# Generated by FakeRAM 2.0 (routing-friendly)
VERSION 5.7 ;
BUSBITCHARS "[]" ;
PROPERTYDEFINITIONS
  MACRO width INTEGER ;
  MACRO depth INTEGER ;
  MACRO banks INTEGER ;
END PROPERTYDEFINITIONS
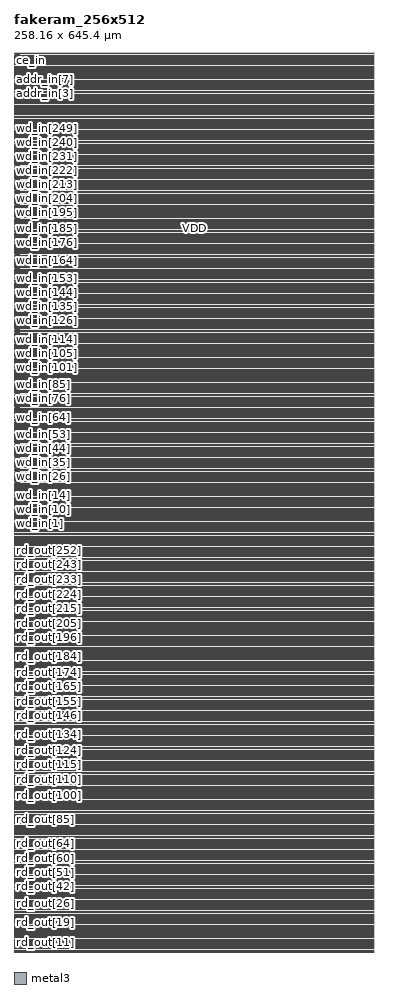
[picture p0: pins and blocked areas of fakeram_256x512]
MACRO fakeram_256x512
  PROPERTY width 256 ;
  PROPERTY depth 512 ;
  PROPERTY banks 2 ;
  FOREIGN fakeram_256x512 0 0 ;
  SYMMETRY X Y R90 ;
  SIZE 258.160 BY 645.400 ;
  CLASS BLOCK ;
  PIN rd_out[0]
    DIRECTION OUTPUT ;
    USE SIGNAL ;
    PORT
      LAYER metal3 ;
      RECT 1.000 0.140 3.000 0.210 ;
    END
    PORT
      LAYER metal3 ;
      RECT 1.000 0.105 4.000 0.245 ;
    END
  END rd_out[0]
  PIN rd_out[1]
    DIRECTION OUTPUT ;
    USE SIGNAL ;
    PORT
      LAYER metal3 ;
      RECT 1.000 1.260 3.000 1.330 ;
    END
    PORT
      LAYER metal3 ;
      RECT 1.000 1.225 4.000 1.365 ;
    END
  END rd_out[1]
  PIN rd_out[2]
    DIRECTION OUTPUT ;
    USE SIGNAL ;
    PORT
      LAYER metal3 ;
      RECT 1.000 2.380 3.000 2.450 ;
    END
    PORT
      LAYER metal3 ;
      RECT 1.000 2.345 4.000 2.485 ;
    END
  END rd_out[2]
  PIN rd_out[3]
    DIRECTION OUTPUT ;
    USE SIGNAL ;
    PORT
      LAYER metal3 ;
      RECT 1.000 3.500 3.000 3.570 ;
    END
    PORT
      LAYER metal3 ;
      RECT 1.000 3.465 4.000 3.605 ;
    END
  END rd_out[3]
  PIN rd_out[4]
    DIRECTION OUTPUT ;
    USE SIGNAL ;
    PORT
      LAYER metal3 ;
      RECT 1.000 4.620 3.000 4.690 ;
    END
    PORT
      LAYER metal3 ;
      RECT 1.000 4.585 4.000 4.725 ;
    END
  END rd_out[4]
  PIN rd_out[5]
    DIRECTION OUTPUT ;
    USE SIGNAL ;
    PORT
      LAYER metal3 ;
      RECT 1.000 5.740 3.000 5.810 ;
    END
    PORT
      LAYER metal3 ;
      RECT 1.000 5.705 4.000 5.845 ;
    END
  END rd_out[5]
  PIN rd_out[6]
    DIRECTION OUTPUT ;
    USE SIGNAL ;
    PORT
      LAYER metal3 ;
      RECT 1.000 6.860 3.000 6.930 ;
    END
    PORT
      LAYER metal3 ;
      RECT 1.000 6.825 4.000 6.965 ;
    END
  END rd_out[6]
  PIN rd_out[7]
    DIRECTION OUTPUT ;
    USE SIGNAL ;
    PORT
      LAYER metal3 ;
      RECT 1.000 7.980 3.000 8.050 ;
    END
    PORT
      LAYER metal3 ;
      RECT 1.000 7.945 4.000 8.085 ;
    END
  END rd_out[7]
  PIN rd_out[8]
    DIRECTION OUTPUT ;
    USE SIGNAL ;
    PORT
      LAYER metal3 ;
      RECT 1.000 9.100 3.000 9.170 ;
    END
    PORT
      LAYER metal3 ;
      RECT 1.000 9.065 4.000 9.205 ;
    END
  END rd_out[8]
  PIN rd_out[9]
    DIRECTION OUTPUT ;
    USE SIGNAL ;
    PORT
      LAYER metal3 ;
      RECT 1.000 10.220 3.000 10.290 ;
    END
    PORT
      LAYER metal3 ;
      RECT 1.000 10.185 4.000 10.325 ;
    END
  END rd_out[9]
  PIN rd_out[10]
    DIRECTION OUTPUT ;
    USE SIGNAL ;
    PORT
      LAYER metal3 ;
      RECT 1.000 11.340 3.000 11.410 ;
    END
    PORT
      LAYER metal3 ;
      RECT 1.000 11.305 4.000 11.445 ;
    END
  END rd_out[10]
  PIN rd_out[11]
    DIRECTION OUTPUT ;
    USE SIGNAL ;
    PORT
      LAYER metal3 ;
      RECT 1.000 12.460 3.000 12.530 ;
    END
    PORT
      LAYER metal3 ;
      RECT 1.000 12.425 4.000 12.565 ;
    END
  END rd_out[11]
  PIN rd_out[12]
    DIRECTION OUTPUT ;
    USE SIGNAL ;
    PORT
      LAYER metal3 ;
      RECT 1.000 13.580 3.000 13.650 ;
    END
    PORT
      LAYER metal3 ;
      RECT 1.000 13.545 4.000 13.685 ;
    END
  END rd_out[12]
  PIN rd_out[13]
    DIRECTION OUTPUT ;
    USE SIGNAL ;
    PORT
      LAYER metal3 ;
      RECT 1.000 14.700 3.000 14.770 ;
    END
    PORT
      LAYER metal3 ;
      RECT 1.000 14.665 4.000 14.805 ;
    END
  END rd_out[13]
  PIN rd_out[14]
    DIRECTION OUTPUT ;
    USE SIGNAL ;
    PORT
      LAYER metal3 ;
      RECT 1.000 15.820 3.000 15.890 ;
    END
    PORT
      LAYER metal3 ;
      RECT 1.000 15.785 4.000 15.925 ;
    END
  END rd_out[14]
  PIN rd_out[15]
    DIRECTION OUTPUT ;
    USE SIGNAL ;
    PORT
      LAYER metal3 ;
      RECT 1.000 16.940 3.000 17.010 ;
    END
    PORT
      LAYER metal3 ;
      RECT 1.000 16.905 4.000 17.045 ;
    END
  END rd_out[15]
  PIN rd_out[16]
    DIRECTION OUTPUT ;
    USE SIGNAL ;
    PORT
      LAYER metal3 ;
      RECT 1.000 18.060 3.000 18.130 ;
    END
    PORT
      LAYER metal3 ;
      RECT 1.000 18.025 4.000 18.165 ;
    END
  END rd_out[16]
  PIN rd_out[17]
    DIRECTION OUTPUT ;
    USE SIGNAL ;
    PORT
      LAYER metal3 ;
      RECT 1.000 19.180 3.000 19.250 ;
    END
    PORT
      LAYER metal3 ;
      RECT 1.000 19.145 4.000 19.285 ;
    END
  END rd_out[17]
  PIN rd_out[18]
    DIRECTION OUTPUT ;
    USE SIGNAL ;
    PORT
      LAYER metal3 ;
      RECT 1.000 20.300 3.000 20.370 ;
    END
    PORT
      LAYER metal3 ;
      RECT 1.000 20.265 4.000 20.405 ;
    END
  END rd_out[18]
  PIN rd_out[19]
    DIRECTION OUTPUT ;
    USE SIGNAL ;
    PORT
      LAYER metal3 ;
      RECT 1.000 21.420 3.000 21.490 ;
    END
    PORT
      LAYER metal3 ;
      RECT 1.000 21.385 4.000 21.525 ;
    END
  END rd_out[19]
  PIN rd_out[20]
    DIRECTION OUTPUT ;
    USE SIGNAL ;
    PORT
      LAYER metal3 ;
      RECT 1.000 22.540 3.000 22.610 ;
    END
    PORT
      LAYER metal3 ;
      RECT 1.000 22.505 4.000 22.645 ;
    END
  END rd_out[20]
  PIN rd_out[21]
    DIRECTION OUTPUT ;
    USE SIGNAL ;
    PORT
      LAYER metal3 ;
      RECT 1.000 23.660 3.000 23.730 ;
    END
    PORT
      LAYER metal3 ;
      RECT 1.000 23.625 4.000 23.765 ;
    END
  END rd_out[21]
  PIN rd_out[22]
    DIRECTION OUTPUT ;
    USE SIGNAL ;
    PORT
      LAYER metal3 ;
      RECT 1.000 24.780 3.000 24.850 ;
    END
    PORT
      LAYER metal3 ;
      RECT 1.000 24.745 4.000 24.885 ;
    END
  END rd_out[22]
  PIN rd_out[23]
    DIRECTION OUTPUT ;
    USE SIGNAL ;
    PORT
      LAYER metal3 ;
      RECT 1.000 25.900 3.000 25.970 ;
    END
    PORT
      LAYER metal3 ;
      RECT 1.000 25.865 4.000 26.005 ;
    END
  END rd_out[23]
  PIN rd_out[24]
    DIRECTION OUTPUT ;
    USE SIGNAL ;
    PORT
      LAYER metal3 ;
      RECT 1.000 27.020 3.000 27.090 ;
    END
    PORT
      LAYER metal3 ;
      RECT 1.000 26.985 4.000 27.125 ;
    END
  END rd_out[24]
  PIN rd_out[25]
    DIRECTION OUTPUT ;
    USE SIGNAL ;
    PORT
      LAYER metal3 ;
      RECT 1.000 28.140 3.000 28.210 ;
    END
    PORT
      LAYER metal3 ;
      RECT 1.000 28.105 4.000 28.245 ;
    END
  END rd_out[25]
  PIN rd_out[26]
    DIRECTION OUTPUT ;
    USE SIGNAL ;
    PORT
      LAYER metal3 ;
      RECT 1.000 29.260 3.000 29.330 ;
    END
    PORT
      LAYER metal3 ;
      RECT 1.000 29.225 4.000 29.365 ;
    END
  END rd_out[26]
  PIN rd_out[27]
    DIRECTION OUTPUT ;
    USE SIGNAL ;
    PORT
      LAYER metal3 ;
      RECT 1.000 30.380 3.000 30.450 ;
    END
    PORT
      LAYER metal3 ;
      RECT 1.000 30.345 4.000 30.485 ;
    END
  END rd_out[27]
  PIN rd_out[28]
    DIRECTION OUTPUT ;
    USE SIGNAL ;
    PORT
      LAYER metal3 ;
      RECT 1.000 31.500 3.000 31.570 ;
    END
    PORT
      LAYER metal3 ;
      RECT 1.000 31.465 4.000 31.605 ;
    END
  END rd_out[28]
  PIN rd_out[29]
    DIRECTION OUTPUT ;
    USE SIGNAL ;
    PORT
      LAYER metal3 ;
      RECT 1.000 32.620 3.000 32.690 ;
    END
    PORT
      LAYER metal3 ;
      RECT 1.000 32.585 4.000 32.725 ;
    END
  END rd_out[29]
  PIN rd_out[30]
    DIRECTION OUTPUT ;
    USE SIGNAL ;
    PORT
      LAYER metal3 ;
      RECT 1.000 33.740 3.000 33.810 ;
    END
    PORT
      LAYER metal3 ;
      RECT 1.000 33.705 4.000 33.845 ;
    END
  END rd_out[30]
  PIN rd_out[31]
    DIRECTION OUTPUT ;
    USE SIGNAL ;
    PORT
      LAYER metal3 ;
      RECT 1.000 34.860 3.000 34.930 ;
    END
    PORT
      LAYER metal3 ;
      RECT 1.000 34.825 4.000 34.965 ;
    END
  END rd_out[31]
  PIN rd_out[32]
    DIRECTION OUTPUT ;
    USE SIGNAL ;
    PORT
      LAYER metal3 ;
      RECT 1.000 35.980 3.000 36.050 ;
    END
    PORT
      LAYER metal3 ;
      RECT 1.000 35.945 4.000 36.085 ;
    END
  END rd_out[32]
  PIN rd_out[33]
    DIRECTION OUTPUT ;
    USE SIGNAL ;
    PORT
      LAYER metal3 ;
      RECT 1.000 37.100 3.000 37.170 ;
    END
    PORT
      LAYER metal3 ;
      RECT 1.000 37.065 4.000 37.205 ;
    END
  END rd_out[33]
  PIN rd_out[34]
    DIRECTION OUTPUT ;
    USE SIGNAL ;
    PORT
      LAYER metal3 ;
      RECT 1.000 38.220 3.000 38.290 ;
    END
    PORT
      LAYER metal3 ;
      RECT 1.000 38.185 4.000 38.325 ;
    END
  END rd_out[34]
  PIN rd_out[35]
    DIRECTION OUTPUT ;
    USE SIGNAL ;
    PORT
      LAYER metal3 ;
      RECT 1.000 39.340 3.000 39.410 ;
    END
    PORT
      LAYER metal3 ;
      RECT 1.000 39.305 4.000 39.445 ;
    END
  END rd_out[35]
  PIN rd_out[36]
    DIRECTION OUTPUT ;
    USE SIGNAL ;
    PORT
      LAYER metal3 ;
      RECT 1.000 40.460 3.000 40.530 ;
    END
    PORT
      LAYER metal3 ;
      RECT 1.000 40.425 4.000 40.565 ;
    END
  END rd_out[36]
  PIN rd_out[37]
    DIRECTION OUTPUT ;
    USE SIGNAL ;
    PORT
      LAYER metal3 ;
      RECT 1.000 41.580 3.000 41.650 ;
    END
    PORT
      LAYER metal3 ;
      RECT 1.000 41.545 4.000 41.685 ;
    END
  END rd_out[37]
  PIN rd_out[38]
    DIRECTION OUTPUT ;
    USE SIGNAL ;
    PORT
      LAYER metal3 ;
      RECT 1.000 42.700 3.000 42.770 ;
    END
    PORT
      LAYER metal3 ;
      RECT 1.000 42.665 4.000 42.805 ;
    END
  END rd_out[38]
  PIN rd_out[39]
    DIRECTION OUTPUT ;
    USE SIGNAL ;
    PORT
      LAYER metal3 ;
      RECT 1.000 43.820 3.000 43.890 ;
    END
    PORT
      LAYER metal3 ;
      RECT 1.000 43.785 4.000 43.925 ;
    END
  END rd_out[39]
  PIN rd_out[40]
    DIRECTION OUTPUT ;
    USE SIGNAL ;
    PORT
      LAYER metal3 ;
      RECT 1.000 44.940 3.000 45.010 ;
    END
    PORT
      LAYER metal3 ;
      RECT 1.000 44.905 4.000 45.045 ;
    END
  END rd_out[40]
  PIN rd_out[41]
    DIRECTION OUTPUT ;
    USE SIGNAL ;
    PORT
      LAYER metal3 ;
      RECT 1.000 46.060 3.000 46.130 ;
    END
    PORT
      LAYER metal3 ;
      RECT 1.000 46.025 4.000 46.165 ;
    END
  END rd_out[41]
  PIN rd_out[42]
    DIRECTION OUTPUT ;
    USE SIGNAL ;
    PORT
      LAYER metal3 ;
      RECT 1.000 47.180 3.000 47.250 ;
    END
    PORT
      LAYER metal3 ;
      RECT 1.000 47.145 4.000 47.285 ;
    END
  END rd_out[42]
  PIN rd_out[43]
    DIRECTION OUTPUT ;
    USE SIGNAL ;
    PORT
      LAYER metal3 ;
      RECT 1.000 48.300 3.000 48.370 ;
    END
    PORT
      LAYER metal3 ;
      RECT 1.000 48.265 4.000 48.405 ;
    END
  END rd_out[43]
  PIN rd_out[44]
    DIRECTION OUTPUT ;
    USE SIGNAL ;
    PORT
      LAYER metal3 ;
      RECT 1.000 49.420 3.000 49.490 ;
    END
    PORT
      LAYER metal3 ;
      RECT 1.000 49.385 4.000 49.525 ;
    END
  END rd_out[44]
  PIN rd_out[45]
    DIRECTION OUTPUT ;
    USE SIGNAL ;
    PORT
      LAYER metal3 ;
      RECT 1.000 50.540 3.000 50.610 ;
    END
    PORT
      LAYER metal3 ;
      RECT 1.000 50.505 4.000 50.645 ;
    END
  END rd_out[45]
  PIN rd_out[46]
    DIRECTION OUTPUT ;
    USE SIGNAL ;
    PORT
      LAYER metal3 ;
      RECT 1.000 51.660 3.000 51.730 ;
    END
    PORT
      LAYER metal3 ;
      RECT 1.000 51.625 4.000 51.765 ;
    END
  END rd_out[46]
  PIN rd_out[47]
    DIRECTION OUTPUT ;
    USE SIGNAL ;
    PORT
      LAYER metal3 ;
      RECT 1.000 52.780 3.000 52.850 ;
    END
    PORT
      LAYER metal3 ;
      RECT 1.000 52.745 4.000 52.885 ;
    END
  END rd_out[47]
  PIN rd_out[48]
    DIRECTION OUTPUT ;
    USE SIGNAL ;
    PORT
      LAYER metal3 ;
      RECT 1.000 53.900 3.000 53.970 ;
    END
    PORT
      LAYER metal3 ;
      RECT 1.000 53.865 4.000 54.005 ;
    END
  END rd_out[48]
  PIN rd_out[49]
    DIRECTION OUTPUT ;
    USE SIGNAL ;
    PORT
      LAYER metal3 ;
      RECT 1.000 55.020 3.000 55.090 ;
    END
    PORT
      LAYER metal3 ;
      RECT 1.000 54.985 4.000 55.125 ;
    END
  END rd_out[49]
  PIN rd_out[50]
    DIRECTION OUTPUT ;
    USE SIGNAL ;
    PORT
      LAYER metal3 ;
      RECT 1.000 56.140 3.000 56.210 ;
    END
    PORT
      LAYER metal3 ;
      RECT 1.000 56.105 4.000 56.245 ;
    END
  END rd_out[50]
  PIN rd_out[51]
    DIRECTION OUTPUT ;
    USE SIGNAL ;
    PORT
      LAYER metal3 ;
      RECT 1.000 57.260 3.000 57.330 ;
    END
    PORT
      LAYER metal3 ;
      RECT 1.000 57.225 4.000 57.365 ;
    END
  END rd_out[51]
  PIN rd_out[52]
    DIRECTION OUTPUT ;
    USE SIGNAL ;
    PORT
      LAYER metal3 ;
      RECT 1.000 58.380 3.000 58.450 ;
    END
    PORT
      LAYER metal3 ;
      RECT 1.000 58.345 4.000 58.485 ;
    END
  END rd_out[52]
  PIN rd_out[53]
    DIRECTION OUTPUT ;
    USE SIGNAL ;
    PORT
      LAYER metal3 ;
      RECT 1.000 59.500 3.000 59.570 ;
    END
    PORT
      LAYER metal3 ;
      RECT 1.000 59.465 4.000 59.605 ;
    END
  END rd_out[53]
  PIN rd_out[54]
    DIRECTION OUTPUT ;
    USE SIGNAL ;
    PORT
      LAYER metal3 ;
      RECT 1.000 60.620 3.000 60.690 ;
    END
    PORT
      LAYER metal3 ;
      RECT 1.000 60.585 4.000 60.725 ;
    END
  END rd_out[54]
  PIN rd_out[55]
    DIRECTION OUTPUT ;
    USE SIGNAL ;
    PORT
      LAYER metal3 ;
      RECT 1.000 61.740 3.000 61.810 ;
    END
    PORT
      LAYER metal3 ;
      RECT 1.000 61.705 4.000 61.845 ;
    END
  END rd_out[55]
  PIN rd_out[56]
    DIRECTION OUTPUT ;
    USE SIGNAL ;
    PORT
      LAYER metal3 ;
      RECT 1.000 62.860 3.000 62.930 ;
    END
    PORT
      LAYER metal3 ;
      RECT 1.000 62.825 4.000 62.965 ;
    END
  END rd_out[56]
  PIN rd_out[57]
    DIRECTION OUTPUT ;
    USE SIGNAL ;
    PORT
      LAYER metal3 ;
      RECT 1.000 63.980 3.000 64.050 ;
    END
    PORT
      LAYER metal3 ;
      RECT 1.000 63.945 4.000 64.085 ;
    END
  END rd_out[57]
  PIN rd_out[58]
    DIRECTION OUTPUT ;
    USE SIGNAL ;
    PORT
      LAYER metal3 ;
      RECT 1.000 65.100 3.000 65.170 ;
    END
    PORT
      LAYER metal3 ;
      RECT 1.000 65.065 4.000 65.205 ;
    END
  END rd_out[58]
  PIN rd_out[59]
    DIRECTION OUTPUT ;
    USE SIGNAL ;
    PORT
      LAYER metal3 ;
      RECT 1.000 66.220 3.000 66.290 ;
    END
    PORT
      LAYER metal3 ;
      RECT 1.000 66.185 4.000 66.325 ;
    END
  END rd_out[59]
  PIN rd_out[60]
    DIRECTION OUTPUT ;
    USE SIGNAL ;
    PORT
      LAYER metal3 ;
      RECT 1.000 67.340 3.000 67.410 ;
    END
    PORT
      LAYER metal3 ;
      RECT 1.000 67.305 4.000 67.445 ;
    END
  END rd_out[60]
  PIN rd_out[61]
    DIRECTION OUTPUT ;
    USE SIGNAL ;
    PORT
      LAYER metal3 ;
      RECT 1.000 68.460 3.000 68.530 ;
    END
    PORT
      LAYER metal3 ;
      RECT 1.000 68.425 4.000 68.565 ;
    END
  END rd_out[61]
  PIN rd_out[62]
    DIRECTION OUTPUT ;
    USE SIGNAL ;
    PORT
      LAYER metal3 ;
      RECT 1.000 69.580 3.000 69.650 ;
    END
    PORT
      LAYER metal3 ;
      RECT 1.000 69.545 4.000 69.685 ;
    END
  END rd_out[62]
  PIN rd_out[63]
    DIRECTION OUTPUT ;
    USE SIGNAL ;
    PORT
      LAYER metal3 ;
      RECT 1.000 70.700 3.000 70.770 ;
    END
    PORT
      LAYER metal3 ;
      RECT 1.000 70.665 4.000 70.805 ;
    END
  END rd_out[63]
  PIN rd_out[64]
    DIRECTION OUTPUT ;
    USE SIGNAL ;
    PORT
      LAYER metal3 ;
      RECT 1.000 71.820 3.000 71.890 ;
    END
    PORT
      LAYER metal3 ;
      RECT 1.000 71.785 4.000 71.925 ;
    END
  END rd_out[64]
  PIN rd_out[65]
    DIRECTION OUTPUT ;
    USE SIGNAL ;
    PORT
      LAYER metal3 ;
      RECT 1.000 72.940 3.000 73.010 ;
    END
    PORT
      LAYER metal3 ;
      RECT 1.000 72.905 4.000 73.045 ;
    END
  END rd_out[65]
  PIN rd_out[66]
    DIRECTION OUTPUT ;
    USE SIGNAL ;
    PORT
      LAYER metal3 ;
      RECT 1.000 74.060 3.000 74.130 ;
    END
    PORT
      LAYER metal3 ;
      RECT 1.000 74.025 4.000 74.165 ;
    END
  END rd_out[66]
  PIN rd_out[67]
    DIRECTION OUTPUT ;
    USE SIGNAL ;
    PORT
      LAYER metal3 ;
      RECT 1.000 75.180 3.000 75.250 ;
    END
    PORT
      LAYER metal3 ;
      RECT 1.000 75.145 4.000 75.285 ;
    END
  END rd_out[67]
  PIN rd_out[68]
    DIRECTION OUTPUT ;
    USE SIGNAL ;
    PORT
      LAYER metal3 ;
      RECT 1.000 76.300 3.000 76.370 ;
    END
    PORT
      LAYER metal3 ;
      RECT 1.000 76.265 4.000 76.405 ;
    END
  END rd_out[68]
  PIN rd_out[69]
    DIRECTION OUTPUT ;
    USE SIGNAL ;
    PORT
      LAYER metal3 ;
      RECT 1.000 77.420 3.000 77.490 ;
    END
    PORT
      LAYER metal3 ;
      RECT 1.000 77.385 4.000 77.525 ;
    END
  END rd_out[69]
  PIN rd_out[70]
    DIRECTION OUTPUT ;
    USE SIGNAL ;
    PORT
      LAYER metal3 ;
      RECT 1.000 78.540 3.000 78.610 ;
    END
    PORT
      LAYER metal3 ;
      RECT 1.000 78.505 4.000 78.645 ;
    END
  END rd_out[70]
  PIN rd_out[71]
    DIRECTION OUTPUT ;
    USE SIGNAL ;
    PORT
      LAYER metal3 ;
      RECT 1.000 79.660 3.000 79.730 ;
    END
    PORT
      LAYER metal3 ;
      RECT 1.000 79.625 4.000 79.765 ;
    END
  END rd_out[71]
  PIN rd_out[72]
    DIRECTION OUTPUT ;
    USE SIGNAL ;
    PORT
      LAYER metal3 ;
      RECT 1.000 80.780 3.000 80.850 ;
    END
    PORT
      LAYER metal3 ;
      RECT 1.000 80.745 4.000 80.885 ;
    END
  END rd_out[72]
  PIN rd_out[73]
    DIRECTION OUTPUT ;
    USE SIGNAL ;
    PORT
      LAYER metal3 ;
      RECT 1.000 81.900 3.000 81.970 ;
    END
    PORT
      LAYER metal3 ;
      RECT 1.000 81.865 4.000 82.005 ;
    END
  END rd_out[73]
  PIN rd_out[74]
    DIRECTION OUTPUT ;
    USE SIGNAL ;
    PORT
      LAYER metal3 ;
      RECT 1.000 83.020 3.000 83.090 ;
    END
    PORT
      LAYER metal3 ;
      RECT 1.000 82.985 4.000 83.125 ;
    END
  END rd_out[74]
  PIN rd_out[75]
    DIRECTION OUTPUT ;
    USE SIGNAL ;
    PORT
      LAYER metal3 ;
      RECT 1.000 84.140 3.000 84.210 ;
    END
    PORT
      LAYER metal3 ;
      RECT 1.000 84.105 4.000 84.245 ;
    END
  END rd_out[75]
  PIN rd_out[76]
    DIRECTION OUTPUT ;
    USE SIGNAL ;
    PORT
      LAYER metal3 ;
      RECT 1.000 85.260 3.000 85.330 ;
    END
    PORT
      LAYER metal3 ;
      RECT 1.000 85.225 4.000 85.365 ;
    END
  END rd_out[76]
  PIN rd_out[77]
    DIRECTION OUTPUT ;
    USE SIGNAL ;
    PORT
      LAYER metal3 ;
      RECT 1.000 86.380 3.000 86.450 ;
    END
    PORT
      LAYER metal3 ;
      RECT 1.000 86.345 4.000 86.485 ;
    END
  END rd_out[77]
  PIN rd_out[78]
    DIRECTION OUTPUT ;
    USE SIGNAL ;
    PORT
      LAYER metal3 ;
      RECT 1.000 87.500 3.000 87.570 ;
    END
    PORT
      LAYER metal3 ;
      RECT 1.000 87.465 4.000 87.605 ;
    END
  END rd_out[78]
  PIN rd_out[79]
    DIRECTION OUTPUT ;
    USE SIGNAL ;
    PORT
      LAYER metal3 ;
      RECT 1.000 88.620 3.000 88.690 ;
    END
    PORT
      LAYER metal3 ;
      RECT 1.000 88.585 4.000 88.725 ;
    END
  END rd_out[79]
  PIN rd_out[80]
    DIRECTION OUTPUT ;
    USE SIGNAL ;
    PORT
      LAYER metal3 ;
      RECT 1.000 89.740 3.000 89.810 ;
    END
    PORT
      LAYER metal3 ;
      RECT 1.000 89.705 4.000 89.845 ;
    END
  END rd_out[80]
  PIN rd_out[81]
    DIRECTION OUTPUT ;
    USE SIGNAL ;
    PORT
      LAYER metal3 ;
      RECT 1.000 90.860 3.000 90.930 ;
    END
    PORT
      LAYER metal3 ;
      RECT 1.000 90.825 4.000 90.965 ;
    END
  END rd_out[81]
  PIN rd_out[82]
    DIRECTION OUTPUT ;
    USE SIGNAL ;
    PORT
      LAYER metal3 ;
      RECT 1.000 91.980 3.000 92.050 ;
    END
    PORT
      LAYER metal3 ;
      RECT 1.000 91.945 4.000 92.085 ;
    END
  END rd_out[82]
  PIN rd_out[83]
    DIRECTION OUTPUT ;
    USE SIGNAL ;
    PORT
      LAYER metal3 ;
      RECT 1.000 93.100 3.000 93.170 ;
    END
    PORT
      LAYER metal3 ;
      RECT 1.000 93.065 4.000 93.205 ;
    END
  END rd_out[83]
  PIN rd_out[84]
    DIRECTION OUTPUT ;
    USE SIGNAL ;
    PORT
      LAYER metal3 ;
      RECT 1.000 94.220 3.000 94.290 ;
    END
    PORT
      LAYER metal3 ;
      RECT 1.000 94.185 4.000 94.325 ;
    END
  END rd_out[84]
  PIN rd_out[85]
    DIRECTION OUTPUT ;
    USE SIGNAL ;
    PORT
      LAYER metal3 ;
      RECT 1.000 95.340 3.000 95.410 ;
    END
    PORT
      LAYER metal3 ;
      RECT 1.000 95.305 4.000 95.445 ;
    END
  END rd_out[85]
  PIN rd_out[86]
    DIRECTION OUTPUT ;
    USE SIGNAL ;
    PORT
      LAYER metal3 ;
      RECT 1.000 96.460 3.000 96.530 ;
    END
    PORT
      LAYER metal3 ;
      RECT 1.000 96.425 4.000 96.565 ;
    END
  END rd_out[86]
  PIN rd_out[87]
    DIRECTION OUTPUT ;
    USE SIGNAL ;
    PORT
      LAYER metal3 ;
      RECT 1.000 97.580 3.000 97.650 ;
    END
    PORT
      LAYER metal3 ;
      RECT 1.000 97.545 4.000 97.685 ;
    END
  END rd_out[87]
  PIN rd_out[88]
    DIRECTION OUTPUT ;
    USE SIGNAL ;
    PORT
      LAYER metal3 ;
      RECT 1.000 98.700 3.000 98.770 ;
    END
    PORT
      LAYER metal3 ;
      RECT 1.000 98.665 4.000 98.805 ;
    END
  END rd_out[88]
  PIN rd_out[89]
    DIRECTION OUTPUT ;
    USE SIGNAL ;
    PORT
      LAYER metal3 ;
      RECT 1.000 99.820 3.000 99.890 ;
    END
    PORT
      LAYER metal3 ;
      RECT 1.000 99.785 4.000 99.925 ;
    END
  END rd_out[89]
  PIN rd_out[90]
    DIRECTION OUTPUT ;
    USE SIGNAL ;
    PORT
      LAYER metal3 ;
      RECT 1.000 100.940 3.000 101.010 ;
    END
    PORT
      LAYER metal3 ;
      RECT 1.000 100.905 4.000 101.045 ;
    END
  END rd_out[90]
  PIN rd_out[91]
    DIRECTION OUTPUT ;
    USE SIGNAL ;
    PORT
      LAYER metal3 ;
      RECT 1.000 102.060 3.000 102.130 ;
    END
    PORT
      LAYER metal3 ;
      RECT 1.000 102.025 4.000 102.165 ;
    END
  END rd_out[91]
  PIN rd_out[92]
    DIRECTION OUTPUT ;
    USE SIGNAL ;
    PORT
      LAYER metal3 ;
      RECT 1.000 103.180 3.000 103.250 ;
    END
    PORT
      LAYER metal3 ;
      RECT 1.000 103.145 4.000 103.285 ;
    END
  END rd_out[92]
  PIN rd_out[93]
    DIRECTION OUTPUT ;
    USE SIGNAL ;
    PORT
      LAYER metal3 ;
      RECT 1.000 104.300 3.000 104.370 ;
    END
    PORT
      LAYER metal3 ;
      RECT 1.000 104.265 4.000 104.405 ;
    END
  END rd_out[93]
  PIN rd_out[94]
    DIRECTION OUTPUT ;
    USE SIGNAL ;
    PORT
      LAYER metal3 ;
      RECT 1.000 105.420 3.000 105.490 ;
    END
    PORT
      LAYER metal3 ;
      RECT 1.000 105.385 4.000 105.525 ;
    END
  END rd_out[94]
  PIN rd_out[95]
    DIRECTION OUTPUT ;
    USE SIGNAL ;
    PORT
      LAYER metal3 ;
      RECT 1.000 106.540 3.000 106.610 ;
    END
    PORT
      LAYER metal3 ;
      RECT 1.000 106.505 4.000 106.645 ;
    END
  END rd_out[95]
  PIN rd_out[96]
    DIRECTION OUTPUT ;
    USE SIGNAL ;
    PORT
      LAYER metal3 ;
      RECT 1.000 107.660 3.000 107.730 ;
    END
    PORT
      LAYER metal3 ;
      RECT 1.000 107.625 4.000 107.765 ;
    END
  END rd_out[96]
  PIN rd_out[97]
    DIRECTION OUTPUT ;
    USE SIGNAL ;
    PORT
      LAYER metal3 ;
      RECT 1.000 108.780 3.000 108.850 ;
    END
    PORT
      LAYER metal3 ;
      RECT 1.000 108.745 4.000 108.885 ;
    END
  END rd_out[97]
  PIN rd_out[98]
    DIRECTION OUTPUT ;
    USE SIGNAL ;
    PORT
      LAYER metal3 ;
      RECT 1.000 109.900 3.000 109.970 ;
    END
    PORT
      LAYER metal3 ;
      RECT 1.000 109.865 4.000 110.005 ;
    END
  END rd_out[98]
  PIN rd_out[99]
    DIRECTION OUTPUT ;
    USE SIGNAL ;
    PORT
      LAYER metal3 ;
      RECT 1.000 111.020 3.000 111.090 ;
    END
    PORT
      LAYER metal3 ;
      RECT 1.000 110.985 4.000 111.125 ;
    END
  END rd_out[99]
  PIN rd_out[100]
    DIRECTION OUTPUT ;
    USE SIGNAL ;
    PORT
      LAYER metal3 ;
      RECT 1.000 112.140 3.000 112.210 ;
    END
    PORT
      LAYER metal3 ;
      RECT 1.000 112.105 4.000 112.245 ;
    END
  END rd_out[100]
  PIN rd_out[101]
    DIRECTION OUTPUT ;
    USE SIGNAL ;
    PORT
      LAYER metal3 ;
      RECT 1.000 113.260 3.000 113.330 ;
    END
    PORT
      LAYER metal3 ;
      RECT 1.000 113.225 4.000 113.365 ;
    END
  END rd_out[101]
  PIN rd_out[102]
    DIRECTION OUTPUT ;
    USE SIGNAL ;
    PORT
      LAYER metal3 ;
      RECT 1.000 114.380 3.000 114.450 ;
    END
    PORT
      LAYER metal3 ;
      RECT 1.000 114.345 4.000 114.485 ;
    END
  END rd_out[102]
  PIN rd_out[103]
    DIRECTION OUTPUT ;
    USE SIGNAL ;
    PORT
      LAYER metal3 ;
      RECT 1.000 115.500 3.000 115.570 ;
    END
    PORT
      LAYER metal3 ;
      RECT 1.000 115.465 4.000 115.605 ;
    END
  END rd_out[103]
  PIN rd_out[104]
    DIRECTION OUTPUT ;
    USE SIGNAL ;
    PORT
      LAYER metal3 ;
      RECT 1.000 116.620 3.000 116.690 ;
    END
    PORT
      LAYER metal3 ;
      RECT 1.000 116.585 4.000 116.725 ;
    END
  END rd_out[104]
  PIN rd_out[105]
    DIRECTION OUTPUT ;
    USE SIGNAL ;
    PORT
      LAYER metal3 ;
      RECT 1.000 117.740 3.000 117.810 ;
    END
    PORT
      LAYER metal3 ;
      RECT 1.000 117.705 4.000 117.845 ;
    END
  END rd_out[105]
  PIN rd_out[106]
    DIRECTION OUTPUT ;
    USE SIGNAL ;
    PORT
      LAYER metal3 ;
      RECT 1.000 118.860 3.000 118.930 ;
    END
    PORT
      LAYER metal3 ;
      RECT 1.000 118.825 4.000 118.965 ;
    END
  END rd_out[106]
  PIN rd_out[107]
    DIRECTION OUTPUT ;
    USE SIGNAL ;
    PORT
      LAYER metal3 ;
      RECT 1.000 119.980 3.000 120.050 ;
    END
    PORT
      LAYER metal3 ;
      RECT 1.000 119.945 4.000 120.085 ;
    END
  END rd_out[107]
  PIN rd_out[108]
    DIRECTION OUTPUT ;
    USE SIGNAL ;
    PORT
      LAYER metal3 ;
      RECT 1.000 121.100 3.000 121.170 ;
    END
    PORT
      LAYER metal3 ;
      RECT 1.000 121.065 4.000 121.205 ;
    END
  END rd_out[108]
  PIN rd_out[109]
    DIRECTION OUTPUT ;
    USE SIGNAL ;
    PORT
      LAYER metal3 ;
      RECT 1.000 122.220 3.000 122.290 ;
    END
    PORT
      LAYER metal3 ;
      RECT 1.000 122.185 4.000 122.325 ;
    END
  END rd_out[109]
  PIN rd_out[110]
    DIRECTION OUTPUT ;
    USE SIGNAL ;
    PORT
      LAYER metal3 ;
      RECT 1.000 123.340 3.000 123.410 ;
    END
    PORT
      LAYER metal3 ;
      RECT 1.000 123.305 4.000 123.445 ;
    END
  END rd_out[110]
  PIN rd_out[111]
    DIRECTION OUTPUT ;
    USE SIGNAL ;
    PORT
      LAYER metal3 ;
      RECT 1.000 124.460 3.000 124.530 ;
    END
    PORT
      LAYER metal3 ;
      RECT 1.000 124.425 4.000 124.565 ;
    END
  END rd_out[111]
  PIN rd_out[112]
    DIRECTION OUTPUT ;
    USE SIGNAL ;
    PORT
      LAYER metal3 ;
      RECT 1.000 125.580 3.000 125.650 ;
    END
    PORT
      LAYER metal3 ;
      RECT 1.000 125.545 4.000 125.685 ;
    END
  END rd_out[112]
  PIN rd_out[113]
    DIRECTION OUTPUT ;
    USE SIGNAL ;
    PORT
      LAYER metal3 ;
      RECT 1.000 126.700 3.000 126.770 ;
    END
    PORT
      LAYER metal3 ;
      RECT 1.000 126.665 4.000 126.805 ;
    END
  END rd_out[113]
  PIN rd_out[114]
    DIRECTION OUTPUT ;
    USE SIGNAL ;
    PORT
      LAYER metal3 ;
      RECT 1.000 127.820 3.000 127.890 ;
    END
    PORT
      LAYER metal3 ;
      RECT 1.000 127.785 4.000 127.925 ;
    END
  END rd_out[114]
  PIN rd_out[115]
    DIRECTION OUTPUT ;
    USE SIGNAL ;
    PORT
      LAYER metal3 ;
      RECT 1.000 128.940 3.000 129.010 ;
    END
    PORT
      LAYER metal3 ;
      RECT 1.000 128.905 4.000 129.045 ;
    END
  END rd_out[115]
  PIN rd_out[116]
    DIRECTION OUTPUT ;
    USE SIGNAL ;
    PORT
      LAYER metal3 ;
      RECT 1.000 130.060 3.000 130.130 ;
    END
    PORT
      LAYER metal3 ;
      RECT 1.000 130.025 4.000 130.165 ;
    END
  END rd_out[116]
  PIN rd_out[117]
    DIRECTION OUTPUT ;
    USE SIGNAL ;
    PORT
      LAYER metal3 ;
      RECT 1.000 131.180 3.000 131.250 ;
    END
    PORT
      LAYER metal3 ;
      RECT 1.000 131.145 4.000 131.285 ;
    END
  END rd_out[117]
  PIN rd_out[118]
    DIRECTION OUTPUT ;
    USE SIGNAL ;
    PORT
      LAYER metal3 ;
      RECT 1.000 132.300 3.000 132.370 ;
    END
    PORT
      LAYER metal3 ;
      RECT 1.000 132.265 4.000 132.405 ;
    END
  END rd_out[118]
  PIN rd_out[119]
    DIRECTION OUTPUT ;
    USE SIGNAL ;
    PORT
      LAYER metal3 ;
      RECT 1.000 133.420 3.000 133.490 ;
    END
    PORT
      LAYER metal3 ;
      RECT 1.000 133.385 4.000 133.525 ;
    END
  END rd_out[119]
  PIN rd_out[120]
    DIRECTION OUTPUT ;
    USE SIGNAL ;
    PORT
      LAYER metal3 ;
      RECT 1.000 134.540 3.000 134.610 ;
    END
    PORT
      LAYER metal3 ;
      RECT 1.000 134.505 4.000 134.645 ;
    END
  END rd_out[120]
  PIN rd_out[121]
    DIRECTION OUTPUT ;
    USE SIGNAL ;
    PORT
      LAYER metal3 ;
      RECT 1.000 135.660 3.000 135.730 ;
    END
    PORT
      LAYER metal3 ;
      RECT 1.000 135.625 4.000 135.765 ;
    END
  END rd_out[121]
  PIN rd_out[122]
    DIRECTION OUTPUT ;
    USE SIGNAL ;
    PORT
      LAYER metal3 ;
      RECT 1.000 136.780 3.000 136.850 ;
    END
    PORT
      LAYER metal3 ;
      RECT 1.000 136.745 4.000 136.885 ;
    END
  END rd_out[122]
  PIN rd_out[123]
    DIRECTION OUTPUT ;
    USE SIGNAL ;
    PORT
      LAYER metal3 ;
      RECT 1.000 137.900 3.000 137.970 ;
    END
    PORT
      LAYER metal3 ;
      RECT 1.000 137.865 4.000 138.005 ;
    END
  END rd_out[123]
  PIN rd_out[124]
    DIRECTION OUTPUT ;
    USE SIGNAL ;
    PORT
      LAYER metal3 ;
      RECT 1.000 139.020 3.000 139.090 ;
    END
    PORT
      LAYER metal3 ;
      RECT 1.000 138.985 4.000 139.125 ;
    END
  END rd_out[124]
  PIN rd_out[125]
    DIRECTION OUTPUT ;
    USE SIGNAL ;
    PORT
      LAYER metal3 ;
      RECT 1.000 140.140 3.000 140.210 ;
    END
    PORT
      LAYER metal3 ;
      RECT 1.000 140.105 4.000 140.245 ;
    END
  END rd_out[125]
  PIN rd_out[126]
    DIRECTION OUTPUT ;
    USE SIGNAL ;
    PORT
      LAYER metal3 ;
      RECT 1.000 141.260 3.000 141.330 ;
    END
    PORT
      LAYER metal3 ;
      RECT 1.000 141.225 4.000 141.365 ;
    END
  END rd_out[126]
  PIN rd_out[127]
    DIRECTION OUTPUT ;
    USE SIGNAL ;
    PORT
      LAYER metal3 ;
      RECT 1.000 142.380 3.000 142.450 ;
    END
    PORT
      LAYER metal3 ;
      RECT 1.000 142.345 4.000 142.485 ;
    END
  END rd_out[127]
  PIN rd_out[128]
    DIRECTION OUTPUT ;
    USE SIGNAL ;
    PORT
      LAYER metal3 ;
      RECT 1.000 143.500 3.000 143.570 ;
    END
    PORT
      LAYER metal3 ;
      RECT 1.000 143.465 4.000 143.605 ;
    END
  END rd_out[128]
  PIN rd_out[129]
    DIRECTION OUTPUT ;
    USE SIGNAL ;
    PORT
      LAYER metal3 ;
      RECT 1.000 144.620 3.000 144.690 ;
    END
    PORT
      LAYER metal3 ;
      RECT 1.000 144.585 4.000 144.725 ;
    END
  END rd_out[129]
  PIN rd_out[130]
    DIRECTION OUTPUT ;
    USE SIGNAL ;
    PORT
      LAYER metal3 ;
      RECT 1.000 145.740 3.000 145.810 ;
    END
    PORT
      LAYER metal3 ;
      RECT 1.000 145.705 4.000 145.845 ;
    END
  END rd_out[130]
  PIN rd_out[131]
    DIRECTION OUTPUT ;
    USE SIGNAL ;
    PORT
      LAYER metal3 ;
      RECT 1.000 146.860 3.000 146.930 ;
    END
    PORT
      LAYER metal3 ;
      RECT 1.000 146.825 4.000 146.965 ;
    END
  END rd_out[131]
  PIN rd_out[132]
    DIRECTION OUTPUT ;
    USE SIGNAL ;
    PORT
      LAYER metal3 ;
      RECT 1.000 147.980 3.000 148.050 ;
    END
    PORT
      LAYER metal3 ;
      RECT 1.000 147.945 4.000 148.085 ;
    END
  END rd_out[132]
  PIN rd_out[133]
    DIRECTION OUTPUT ;
    USE SIGNAL ;
    PORT
      LAYER metal3 ;
      RECT 1.000 149.100 3.000 149.170 ;
    END
    PORT
      LAYER metal3 ;
      RECT 1.000 149.065 4.000 149.205 ;
    END
  END rd_out[133]
  PIN rd_out[134]
    DIRECTION OUTPUT ;
    USE SIGNAL ;
    PORT
      LAYER metal3 ;
      RECT 1.000 150.220 3.000 150.290 ;
    END
    PORT
      LAYER metal3 ;
      RECT 1.000 150.185 4.000 150.325 ;
    END
  END rd_out[134]
  PIN rd_out[135]
    DIRECTION OUTPUT ;
    USE SIGNAL ;
    PORT
      LAYER metal3 ;
      RECT 1.000 151.340 3.000 151.410 ;
    END
    PORT
      LAYER metal3 ;
      RECT 1.000 151.305 4.000 151.445 ;
    END
  END rd_out[135]
  PIN rd_out[136]
    DIRECTION OUTPUT ;
    USE SIGNAL ;
    PORT
      LAYER metal3 ;
      RECT 1.000 152.460 3.000 152.530 ;
    END
    PORT
      LAYER metal3 ;
      RECT 1.000 152.425 4.000 152.565 ;
    END
  END rd_out[136]
  PIN rd_out[137]
    DIRECTION OUTPUT ;
    USE SIGNAL ;
    PORT
      LAYER metal3 ;
      RECT 1.000 153.580 3.000 153.650 ;
    END
    PORT
      LAYER metal3 ;
      RECT 1.000 153.545 4.000 153.685 ;
    END
  END rd_out[137]
  PIN rd_out[138]
    DIRECTION OUTPUT ;
    USE SIGNAL ;
    PORT
      LAYER metal3 ;
      RECT 1.000 154.700 3.000 154.770 ;
    END
    PORT
      LAYER metal3 ;
      RECT 1.000 154.665 4.000 154.805 ;
    END
  END rd_out[138]
  PIN rd_out[139]
    DIRECTION OUTPUT ;
    USE SIGNAL ;
    PORT
      LAYER metal3 ;
      RECT 1.000 155.820 3.000 155.890 ;
    END
    PORT
      LAYER metal3 ;
      RECT 1.000 155.785 4.000 155.925 ;
    END
  END rd_out[139]
  PIN rd_out[140]
    DIRECTION OUTPUT ;
    USE SIGNAL ;
    PORT
      LAYER metal3 ;
      RECT 1.000 156.940 3.000 157.010 ;
    END
    PORT
      LAYER metal3 ;
      RECT 1.000 156.905 4.000 157.045 ;
    END
  END rd_out[140]
  PIN rd_out[141]
    DIRECTION OUTPUT ;
    USE SIGNAL ;
    PORT
      LAYER metal3 ;
      RECT 1.000 158.060 3.000 158.130 ;
    END
    PORT
      LAYER metal3 ;
      RECT 1.000 158.025 4.000 158.165 ;
    END
  END rd_out[141]
  PIN rd_out[142]
    DIRECTION OUTPUT ;
    USE SIGNAL ;
    PORT
      LAYER metal3 ;
      RECT 1.000 159.180 3.000 159.250 ;
    END
    PORT
      LAYER metal3 ;
      RECT 1.000 159.145 4.000 159.285 ;
    END
  END rd_out[142]
  PIN rd_out[143]
    DIRECTION OUTPUT ;
    USE SIGNAL ;
    PORT
      LAYER metal3 ;
      RECT 1.000 160.300 3.000 160.370 ;
    END
    PORT
      LAYER metal3 ;
      RECT 1.000 160.265 4.000 160.405 ;
    END
  END rd_out[143]
  PIN rd_out[144]
    DIRECTION OUTPUT ;
    USE SIGNAL ;
    PORT
      LAYER metal3 ;
      RECT 1.000 161.420 3.000 161.490 ;
    END
    PORT
      LAYER metal3 ;
      RECT 1.000 161.385 4.000 161.525 ;
    END
  END rd_out[144]
  PIN rd_out[145]
    DIRECTION OUTPUT ;
    USE SIGNAL ;
    PORT
      LAYER metal3 ;
      RECT 1.000 162.540 3.000 162.610 ;
    END
    PORT
      LAYER metal3 ;
      RECT 1.000 162.505 4.000 162.645 ;
    END
  END rd_out[145]
  PIN rd_out[146]
    DIRECTION OUTPUT ;
    USE SIGNAL ;
    PORT
      LAYER metal3 ;
      RECT 1.000 163.660 3.000 163.730 ;
    END
    PORT
      LAYER metal3 ;
      RECT 1.000 163.625 4.000 163.765 ;
    END
  END rd_out[146]
  PIN rd_out[147]
    DIRECTION OUTPUT ;
    USE SIGNAL ;
    PORT
      LAYER metal3 ;
      RECT 1.000 164.780 3.000 164.850 ;
    END
    PORT
      LAYER metal3 ;
      RECT 1.000 164.745 4.000 164.885 ;
    END
  END rd_out[147]
  PIN rd_out[148]
    DIRECTION OUTPUT ;
    USE SIGNAL ;
    PORT
      LAYER metal3 ;
      RECT 1.000 165.900 3.000 165.970 ;
    END
    PORT
      LAYER metal3 ;
      RECT 1.000 165.865 4.000 166.005 ;
    END
  END rd_out[148]
  PIN rd_out[149]
    DIRECTION OUTPUT ;
    USE SIGNAL ;
    PORT
      LAYER metal3 ;
      RECT 1.000 167.020 3.000 167.090 ;
    END
    PORT
      LAYER metal3 ;
      RECT 1.000 166.985 4.000 167.125 ;
    END
  END rd_out[149]
  PIN rd_out[150]
    DIRECTION OUTPUT ;
    USE SIGNAL ;
    PORT
      LAYER metal3 ;
      RECT 1.000 168.140 3.000 168.210 ;
    END
    PORT
      LAYER metal3 ;
      RECT 1.000 168.105 4.000 168.245 ;
    END
  END rd_out[150]
  PIN rd_out[151]
    DIRECTION OUTPUT ;
    USE SIGNAL ;
    PORT
      LAYER metal3 ;
      RECT 1.000 169.260 3.000 169.330 ;
    END
    PORT
      LAYER metal3 ;
      RECT 1.000 169.225 4.000 169.365 ;
    END
  END rd_out[151]
  PIN rd_out[152]
    DIRECTION OUTPUT ;
    USE SIGNAL ;
    PORT
      LAYER metal3 ;
      RECT 1.000 170.380 3.000 170.450 ;
    END
    PORT
      LAYER metal3 ;
      RECT 1.000 170.345 4.000 170.485 ;
    END
  END rd_out[152]
  PIN rd_out[153]
    DIRECTION OUTPUT ;
    USE SIGNAL ;
    PORT
      LAYER metal3 ;
      RECT 1.000 171.500 3.000 171.570 ;
    END
    PORT
      LAYER metal3 ;
      RECT 1.000 171.465 4.000 171.605 ;
    END
  END rd_out[153]
  PIN rd_out[154]
    DIRECTION OUTPUT ;
    USE SIGNAL ;
    PORT
      LAYER metal3 ;
      RECT 1.000 172.620 3.000 172.690 ;
    END
    PORT
      LAYER metal3 ;
      RECT 1.000 172.585 4.000 172.725 ;
    END
  END rd_out[154]
  PIN rd_out[155]
    DIRECTION OUTPUT ;
    USE SIGNAL ;
    PORT
      LAYER metal3 ;
      RECT 1.000 173.740 3.000 173.810 ;
    END
    PORT
      LAYER metal3 ;
      RECT 1.000 173.705 4.000 173.845 ;
    END
  END rd_out[155]
  PIN rd_out[156]
    DIRECTION OUTPUT ;
    USE SIGNAL ;
    PORT
      LAYER metal3 ;
      RECT 1.000 174.860 3.000 174.930 ;
    END
    PORT
      LAYER metal3 ;
      RECT 1.000 174.825 4.000 174.965 ;
    END
  END rd_out[156]
  PIN rd_out[157]
    DIRECTION OUTPUT ;
    USE SIGNAL ;
    PORT
      LAYER metal3 ;
      RECT 1.000 175.980 3.000 176.050 ;
    END
    PORT
      LAYER metal3 ;
      RECT 1.000 175.945 4.000 176.085 ;
    END
  END rd_out[157]
  PIN rd_out[158]
    DIRECTION OUTPUT ;
    USE SIGNAL ;
    PORT
      LAYER metal3 ;
      RECT 1.000 177.100 3.000 177.170 ;
    END
    PORT
      LAYER metal3 ;
      RECT 1.000 177.065 4.000 177.205 ;
    END
  END rd_out[158]
  PIN rd_out[159]
    DIRECTION OUTPUT ;
    USE SIGNAL ;
    PORT
      LAYER metal3 ;
      RECT 1.000 178.220 3.000 178.290 ;
    END
    PORT
      LAYER metal3 ;
      RECT 1.000 178.185 4.000 178.325 ;
    END
  END rd_out[159]
  PIN rd_out[160]
    DIRECTION OUTPUT ;
    USE SIGNAL ;
    PORT
      LAYER metal3 ;
      RECT 1.000 179.340 3.000 179.410 ;
    END
    PORT
      LAYER metal3 ;
      RECT 1.000 179.305 4.000 179.445 ;
    END
  END rd_out[160]
  PIN rd_out[161]
    DIRECTION OUTPUT ;
    USE SIGNAL ;
    PORT
      LAYER metal3 ;
      RECT 1.000 180.460 3.000 180.530 ;
    END
    PORT
      LAYER metal3 ;
      RECT 1.000 180.425 4.000 180.565 ;
    END
  END rd_out[161]
  PIN rd_out[162]
    DIRECTION OUTPUT ;
    USE SIGNAL ;
    PORT
      LAYER metal3 ;
      RECT 1.000 181.580 3.000 181.650 ;
    END
    PORT
      LAYER metal3 ;
      RECT 1.000 181.545 4.000 181.685 ;
    END
  END rd_out[162]
  PIN rd_out[163]
    DIRECTION OUTPUT ;
    USE SIGNAL ;
    PORT
      LAYER metal3 ;
      RECT 1.000 182.700 3.000 182.770 ;
    END
    PORT
      LAYER metal3 ;
      RECT 1.000 182.665 4.000 182.805 ;
    END
  END rd_out[163]
  PIN rd_out[164]
    DIRECTION OUTPUT ;
    USE SIGNAL ;
    PORT
      LAYER metal3 ;
      RECT 1.000 183.820 3.000 183.890 ;
    END
    PORT
      LAYER metal3 ;
      RECT 1.000 183.785 4.000 183.925 ;
    END
  END rd_out[164]
  PIN rd_out[165]
    DIRECTION OUTPUT ;
    USE SIGNAL ;
    PORT
      LAYER metal3 ;
      RECT 1.000 184.940 3.000 185.010 ;
    END
    PORT
      LAYER metal3 ;
      RECT 1.000 184.905 4.000 185.045 ;
    END
  END rd_out[165]
  PIN rd_out[166]
    DIRECTION OUTPUT ;
    USE SIGNAL ;
    PORT
      LAYER metal3 ;
      RECT 1.000 186.060 3.000 186.130 ;
    END
    PORT
      LAYER metal3 ;
      RECT 1.000 186.025 4.000 186.165 ;
    END
  END rd_out[166]
  PIN rd_out[167]
    DIRECTION OUTPUT ;
    USE SIGNAL ;
    PORT
      LAYER metal3 ;
      RECT 1.000 187.180 3.000 187.250 ;
    END
    PORT
      LAYER metal3 ;
      RECT 1.000 187.145 4.000 187.285 ;
    END
  END rd_out[167]
  PIN rd_out[168]
    DIRECTION OUTPUT ;
    USE SIGNAL ;
    PORT
      LAYER metal3 ;
      RECT 1.000 188.300 3.000 188.370 ;
    END
    PORT
      LAYER metal3 ;
      RECT 1.000 188.265 4.000 188.405 ;
    END
  END rd_out[168]
  PIN rd_out[169]
    DIRECTION OUTPUT ;
    USE SIGNAL ;
    PORT
      LAYER metal3 ;
      RECT 1.000 189.420 3.000 189.490 ;
    END
    PORT
      LAYER metal3 ;
      RECT 1.000 189.385 4.000 189.525 ;
    END
  END rd_out[169]
  PIN rd_out[170]
    DIRECTION OUTPUT ;
    USE SIGNAL ;
    PORT
      LAYER metal3 ;
      RECT 1.000 190.540 3.000 190.610 ;
    END
    PORT
      LAYER metal3 ;
      RECT 1.000 190.505 4.000 190.645 ;
    END
  END rd_out[170]
  PIN rd_out[171]
    DIRECTION OUTPUT ;
    USE SIGNAL ;
    PORT
      LAYER metal3 ;
      RECT 1.000 191.660 3.000 191.730 ;
    END
    PORT
      LAYER metal3 ;
      RECT 1.000 191.625 4.000 191.765 ;
    END
  END rd_out[171]
  PIN rd_out[172]
    DIRECTION OUTPUT ;
    USE SIGNAL ;
    PORT
      LAYER metal3 ;
      RECT 1.000 192.780 3.000 192.850 ;
    END
    PORT
      LAYER metal3 ;
      RECT 1.000 192.745 4.000 192.885 ;
    END
  END rd_out[172]
  PIN rd_out[173]
    DIRECTION OUTPUT ;
    USE SIGNAL ;
    PORT
      LAYER metal3 ;
      RECT 1.000 193.900 3.000 193.970 ;
    END
    PORT
      LAYER metal3 ;
      RECT 1.000 193.865 4.000 194.005 ;
    END
  END rd_out[173]
  PIN rd_out[174]
    DIRECTION OUTPUT ;
    USE SIGNAL ;
    PORT
      LAYER metal3 ;
      RECT 1.000 195.020 3.000 195.090 ;
    END
    PORT
      LAYER metal3 ;
      RECT 1.000 194.985 4.000 195.125 ;
    END
  END rd_out[174]
  PIN rd_out[175]
    DIRECTION OUTPUT ;
    USE SIGNAL ;
    PORT
      LAYER metal3 ;
      RECT 1.000 196.140 3.000 196.210 ;
    END
    PORT
      LAYER metal3 ;
      RECT 1.000 196.105 4.000 196.245 ;
    END
  END rd_out[175]
  PIN rd_out[176]
    DIRECTION OUTPUT ;
    USE SIGNAL ;
    PORT
      LAYER metal3 ;
      RECT 1.000 197.260 3.000 197.330 ;
    END
    PORT
      LAYER metal3 ;
      RECT 1.000 197.225 4.000 197.365 ;
    END
  END rd_out[176]
  PIN rd_out[177]
    DIRECTION OUTPUT ;
    USE SIGNAL ;
    PORT
      LAYER metal3 ;
      RECT 1.000 198.380 3.000 198.450 ;
    END
    PORT
      LAYER metal3 ;
      RECT 1.000 198.345 4.000 198.485 ;
    END
  END rd_out[177]
  PIN rd_out[178]
    DIRECTION OUTPUT ;
    USE SIGNAL ;
    PORT
      LAYER metal3 ;
      RECT 1.000 199.500 3.000 199.570 ;
    END
    PORT
      LAYER metal3 ;
      RECT 1.000 199.465 4.000 199.605 ;
    END
  END rd_out[178]
  PIN rd_out[179]
    DIRECTION OUTPUT ;
    USE SIGNAL ;
    PORT
      LAYER metal3 ;
      RECT 1.000 200.620 3.000 200.690 ;
    END
    PORT
      LAYER metal3 ;
      RECT 1.000 200.585 4.000 200.725 ;
    END
  END rd_out[179]
  PIN rd_out[180]
    DIRECTION OUTPUT ;
    USE SIGNAL ;
    PORT
      LAYER metal3 ;
      RECT 1.000 201.740 3.000 201.810 ;
    END
    PORT
      LAYER metal3 ;
      RECT 1.000 201.705 4.000 201.845 ;
    END
  END rd_out[180]
  PIN rd_out[181]
    DIRECTION OUTPUT ;
    USE SIGNAL ;
    PORT
      LAYER metal3 ;
      RECT 1.000 202.860 3.000 202.930 ;
    END
    PORT
      LAYER metal3 ;
      RECT 1.000 202.825 4.000 202.965 ;
    END
  END rd_out[181]
  PIN rd_out[182]
    DIRECTION OUTPUT ;
    USE SIGNAL ;
    PORT
      LAYER metal3 ;
      RECT 1.000 203.980 3.000 204.050 ;
    END
    PORT
      LAYER metal3 ;
      RECT 1.000 203.945 4.000 204.085 ;
    END
  END rd_out[182]
  PIN rd_out[183]
    DIRECTION OUTPUT ;
    USE SIGNAL ;
    PORT
      LAYER metal3 ;
      RECT 1.000 205.100 3.000 205.170 ;
    END
    PORT
      LAYER metal3 ;
      RECT 1.000 205.065 4.000 205.205 ;
    END
  END rd_out[183]
  PIN rd_out[184]
    DIRECTION OUTPUT ;
    USE SIGNAL ;
    PORT
      LAYER metal3 ;
      RECT 1.000 206.220 3.000 206.290 ;
    END
    PORT
      LAYER metal3 ;
      RECT 1.000 206.185 4.000 206.325 ;
    END
  END rd_out[184]
  PIN rd_out[185]
    DIRECTION OUTPUT ;
    USE SIGNAL ;
    PORT
      LAYER metal3 ;
      RECT 1.000 207.340 3.000 207.410 ;
    END
    PORT
      LAYER metal3 ;
      RECT 1.000 207.305 4.000 207.445 ;
    END
  END rd_out[185]
  PIN rd_out[186]
    DIRECTION OUTPUT ;
    USE SIGNAL ;
    PORT
      LAYER metal3 ;
      RECT 1.000 208.460 3.000 208.530 ;
    END
    PORT
      LAYER metal3 ;
      RECT 1.000 208.425 4.000 208.565 ;
    END
  END rd_out[186]
  PIN rd_out[187]
    DIRECTION OUTPUT ;
    USE SIGNAL ;
    PORT
      LAYER metal3 ;
      RECT 1.000 209.580 3.000 209.650 ;
    END
    PORT
      LAYER metal3 ;
      RECT 1.000 209.545 4.000 209.685 ;
    END
  END rd_out[187]
  PIN rd_out[188]
    DIRECTION OUTPUT ;
    USE SIGNAL ;
    PORT
      LAYER metal3 ;
      RECT 1.000 210.700 3.000 210.770 ;
    END
    PORT
      LAYER metal3 ;
      RECT 1.000 210.665 4.000 210.805 ;
    END
  END rd_out[188]
  PIN rd_out[189]
    DIRECTION OUTPUT ;
    USE SIGNAL ;
    PORT
      LAYER metal3 ;
      RECT 1.000 211.820 3.000 211.890 ;
    END
    PORT
      LAYER metal3 ;
      RECT 1.000 211.785 4.000 211.925 ;
    END
  END rd_out[189]
  PIN rd_out[190]
    DIRECTION OUTPUT ;
    USE SIGNAL ;
    PORT
      LAYER metal3 ;
      RECT 1.000 212.940 3.000 213.010 ;
    END
    PORT
      LAYER metal3 ;
      RECT 1.000 212.905 4.000 213.045 ;
    END
  END rd_out[190]
  PIN rd_out[191]
    DIRECTION OUTPUT ;
    USE SIGNAL ;
    PORT
      LAYER metal3 ;
      RECT 1.000 214.060 3.000 214.130 ;
    END
    PORT
      LAYER metal3 ;
      RECT 1.000 214.025 4.000 214.165 ;
    END
  END rd_out[191]
  PIN rd_out[192]
    DIRECTION OUTPUT ;
    USE SIGNAL ;
    PORT
      LAYER metal3 ;
      RECT 1.000 215.180 3.000 215.250 ;
    END
    PORT
      LAYER metal3 ;
      RECT 1.000 215.145 4.000 215.285 ;
    END
  END rd_out[192]
  PIN rd_out[193]
    DIRECTION OUTPUT ;
    USE SIGNAL ;
    PORT
      LAYER metal3 ;
      RECT 1.000 216.300 3.000 216.370 ;
    END
    PORT
      LAYER metal3 ;
      RECT 1.000 216.265 4.000 216.405 ;
    END
  END rd_out[193]
  PIN rd_out[194]
    DIRECTION OUTPUT ;
    USE SIGNAL ;
    PORT
      LAYER metal3 ;
      RECT 1.000 217.420 3.000 217.490 ;
    END
    PORT
      LAYER metal3 ;
      RECT 1.000 217.385 4.000 217.525 ;
    END
  END rd_out[194]
  PIN rd_out[195]
    DIRECTION OUTPUT ;
    USE SIGNAL ;
    PORT
      LAYER metal3 ;
      RECT 1.000 218.540 3.000 218.610 ;
    END
    PORT
      LAYER metal3 ;
      RECT 1.000 218.505 4.000 218.645 ;
    END
  END rd_out[195]
  PIN rd_out[196]
    DIRECTION OUTPUT ;
    USE SIGNAL ;
    PORT
      LAYER metal3 ;
      RECT 1.000 219.660 3.000 219.730 ;
    END
    PORT
      LAYER metal3 ;
      RECT 1.000 219.625 4.000 219.765 ;
    END
  END rd_out[196]
  PIN rd_out[197]
    DIRECTION OUTPUT ;
    USE SIGNAL ;
    PORT
      LAYER metal3 ;
      RECT 1.000 220.780 3.000 220.850 ;
    END
    PORT
      LAYER metal3 ;
      RECT 1.000 220.745 4.000 220.885 ;
    END
  END rd_out[197]
  PIN rd_out[198]
    DIRECTION OUTPUT ;
    USE SIGNAL ;
    PORT
      LAYER metal3 ;
      RECT 1.000 221.900 3.000 221.970 ;
    END
    PORT
      LAYER metal3 ;
      RECT 1.000 221.865 4.000 222.005 ;
    END
  END rd_out[198]
  PIN rd_out[199]
    DIRECTION OUTPUT ;
    USE SIGNAL ;
    PORT
      LAYER metal3 ;
      RECT 1.000 223.020 3.000 223.090 ;
    END
    PORT
      LAYER metal3 ;
      RECT 1.000 222.985 4.000 223.125 ;
    END
  END rd_out[199]
  PIN rd_out[200]
    DIRECTION OUTPUT ;
    USE SIGNAL ;
    PORT
      LAYER metal3 ;
      RECT 1.000 224.140 3.000 224.210 ;
    END
    PORT
      LAYER metal3 ;
      RECT 1.000 224.105 4.000 224.245 ;
    END
  END rd_out[200]
  PIN rd_out[201]
    DIRECTION OUTPUT ;
    USE SIGNAL ;
    PORT
      LAYER metal3 ;
      RECT 1.000 225.260 3.000 225.330 ;
    END
    PORT
      LAYER metal3 ;
      RECT 1.000 225.225 4.000 225.365 ;
    END
  END rd_out[201]
  PIN rd_out[202]
    DIRECTION OUTPUT ;
    USE SIGNAL ;
    PORT
      LAYER metal3 ;
      RECT 1.000 226.380 3.000 226.450 ;
    END
    PORT
      LAYER metal3 ;
      RECT 1.000 226.345 4.000 226.485 ;
    END
  END rd_out[202]
  PIN rd_out[203]
    DIRECTION OUTPUT ;
    USE SIGNAL ;
    PORT
      LAYER metal3 ;
      RECT 1.000 227.500 3.000 227.570 ;
    END
    PORT
      LAYER metal3 ;
      RECT 1.000 227.465 4.000 227.605 ;
    END
  END rd_out[203]
  PIN rd_out[204]
    DIRECTION OUTPUT ;
    USE SIGNAL ;
    PORT
      LAYER metal3 ;
      RECT 1.000 228.620 3.000 228.690 ;
    END
    PORT
      LAYER metal3 ;
      RECT 1.000 228.585 4.000 228.725 ;
    END
  END rd_out[204]
  PIN rd_out[205]
    DIRECTION OUTPUT ;
    USE SIGNAL ;
    PORT
      LAYER metal3 ;
      RECT 1.000 229.740 3.000 229.810 ;
    END
    PORT
      LAYER metal3 ;
      RECT 1.000 229.705 4.000 229.845 ;
    END
  END rd_out[205]
  PIN rd_out[206]
    DIRECTION OUTPUT ;
    USE SIGNAL ;
    PORT
      LAYER metal3 ;
      RECT 1.000 230.860 3.000 230.930 ;
    END
    PORT
      LAYER metal3 ;
      RECT 1.000 230.825 4.000 230.965 ;
    END
  END rd_out[206]
  PIN rd_out[207]
    DIRECTION OUTPUT ;
    USE SIGNAL ;
    PORT
      LAYER metal3 ;
      RECT 1.000 231.980 3.000 232.050 ;
    END
    PORT
      LAYER metal3 ;
      RECT 1.000 231.945 4.000 232.085 ;
    END
  END rd_out[207]
  PIN rd_out[208]
    DIRECTION OUTPUT ;
    USE SIGNAL ;
    PORT
      LAYER metal3 ;
      RECT 1.000 233.100 3.000 233.170 ;
    END
    PORT
      LAYER metal3 ;
      RECT 1.000 233.065 4.000 233.205 ;
    END
  END rd_out[208]
  PIN rd_out[209]
    DIRECTION OUTPUT ;
    USE SIGNAL ;
    PORT
      LAYER metal3 ;
      RECT 1.000 234.220 3.000 234.290 ;
    END
    PORT
      LAYER metal3 ;
      RECT 1.000 234.185 4.000 234.325 ;
    END
  END rd_out[209]
  PIN rd_out[210]
    DIRECTION OUTPUT ;
    USE SIGNAL ;
    PORT
      LAYER metal3 ;
      RECT 1.000 235.340 3.000 235.410 ;
    END
    PORT
      LAYER metal3 ;
      RECT 1.000 235.305 4.000 235.445 ;
    END
  END rd_out[210]
  PIN rd_out[211]
    DIRECTION OUTPUT ;
    USE SIGNAL ;
    PORT
      LAYER metal3 ;
      RECT 1.000 236.460 3.000 236.530 ;
    END
    PORT
      LAYER metal3 ;
      RECT 1.000 236.425 4.000 236.565 ;
    END
  END rd_out[211]
  PIN rd_out[212]
    DIRECTION OUTPUT ;
    USE SIGNAL ;
    PORT
      LAYER metal3 ;
      RECT 1.000 237.580 3.000 237.650 ;
    END
    PORT
      LAYER metal3 ;
      RECT 1.000 237.545 4.000 237.685 ;
    END
  END rd_out[212]
  PIN rd_out[213]
    DIRECTION OUTPUT ;
    USE SIGNAL ;
    PORT
      LAYER metal3 ;
      RECT 1.000 238.700 3.000 238.770 ;
    END
    PORT
      LAYER metal3 ;
      RECT 1.000 238.665 4.000 238.805 ;
    END
  END rd_out[213]
  PIN rd_out[214]
    DIRECTION OUTPUT ;
    USE SIGNAL ;
    PORT
      LAYER metal3 ;
      RECT 1.000 239.820 3.000 239.890 ;
    END
    PORT
      LAYER metal3 ;
      RECT 1.000 239.785 4.000 239.925 ;
    END
  END rd_out[214]
  PIN rd_out[215]
    DIRECTION OUTPUT ;
    USE SIGNAL ;
    PORT
      LAYER metal3 ;
      RECT 1.000 240.940 3.000 241.010 ;
    END
    PORT
      LAYER metal3 ;
      RECT 1.000 240.905 4.000 241.045 ;
    END
  END rd_out[215]
  PIN rd_out[216]
    DIRECTION OUTPUT ;
    USE SIGNAL ;
    PORT
      LAYER metal3 ;
      RECT 1.000 242.060 3.000 242.130 ;
    END
    PORT
      LAYER metal3 ;
      RECT 1.000 242.025 4.000 242.165 ;
    END
  END rd_out[216]
  PIN rd_out[217]
    DIRECTION OUTPUT ;
    USE SIGNAL ;
    PORT
      LAYER metal3 ;
      RECT 1.000 243.180 3.000 243.250 ;
    END
    PORT
      LAYER metal3 ;
      RECT 1.000 243.145 4.000 243.285 ;
    END
  END rd_out[217]
  PIN rd_out[218]
    DIRECTION OUTPUT ;
    USE SIGNAL ;
    PORT
      LAYER metal3 ;
      RECT 1.000 244.300 3.000 244.370 ;
    END
    PORT
      LAYER metal3 ;
      RECT 1.000 244.265 4.000 244.405 ;
    END
  END rd_out[218]
  PIN rd_out[219]
    DIRECTION OUTPUT ;
    USE SIGNAL ;
    PORT
      LAYER metal3 ;
      RECT 1.000 245.420 3.000 245.490 ;
    END
    PORT
      LAYER metal3 ;
      RECT 1.000 245.385 4.000 245.525 ;
    END
  END rd_out[219]
  PIN rd_out[220]
    DIRECTION OUTPUT ;
    USE SIGNAL ;
    PORT
      LAYER metal3 ;
      RECT 1.000 246.540 3.000 246.610 ;
    END
    PORT
      LAYER metal3 ;
      RECT 1.000 246.505 4.000 246.645 ;
    END
  END rd_out[220]
  PIN rd_out[221]
    DIRECTION OUTPUT ;
    USE SIGNAL ;
    PORT
      LAYER metal3 ;
      RECT 1.000 247.660 3.000 247.730 ;
    END
    PORT
      LAYER metal3 ;
      RECT 1.000 247.625 4.000 247.765 ;
    END
  END rd_out[221]
  PIN rd_out[222]
    DIRECTION OUTPUT ;
    USE SIGNAL ;
    PORT
      LAYER metal3 ;
      RECT 1.000 248.780 3.000 248.850 ;
    END
    PORT
      LAYER metal3 ;
      RECT 1.000 248.745 4.000 248.885 ;
    END
  END rd_out[222]
  PIN rd_out[223]
    DIRECTION OUTPUT ;
    USE SIGNAL ;
    PORT
      LAYER metal3 ;
      RECT 1.000 249.900 3.000 249.970 ;
    END
    PORT
      LAYER metal3 ;
      RECT 1.000 249.865 4.000 250.005 ;
    END
  END rd_out[223]
  PIN rd_out[224]
    DIRECTION OUTPUT ;
    USE SIGNAL ;
    PORT
      LAYER metal3 ;
      RECT 1.000 251.020 3.000 251.090 ;
    END
    PORT
      LAYER metal3 ;
      RECT 1.000 250.985 4.000 251.125 ;
    END
  END rd_out[224]
  PIN rd_out[225]
    DIRECTION OUTPUT ;
    USE SIGNAL ;
    PORT
      LAYER metal3 ;
      RECT 1.000 252.140 3.000 252.210 ;
    END
    PORT
      LAYER metal3 ;
      RECT 1.000 252.105 4.000 252.245 ;
    END
  END rd_out[225]
  PIN rd_out[226]
    DIRECTION OUTPUT ;
    USE SIGNAL ;
    PORT
      LAYER metal3 ;
      RECT 1.000 253.260 3.000 253.330 ;
    END
    PORT
      LAYER metal3 ;
      RECT 1.000 253.225 4.000 253.365 ;
    END
  END rd_out[226]
  PIN rd_out[227]
    DIRECTION OUTPUT ;
    USE SIGNAL ;
    PORT
      LAYER metal3 ;
      RECT 1.000 254.380 3.000 254.450 ;
    END
    PORT
      LAYER metal3 ;
      RECT 1.000 254.345 4.000 254.485 ;
    END
  END rd_out[227]
  PIN rd_out[228]
    DIRECTION OUTPUT ;
    USE SIGNAL ;
    PORT
      LAYER metal3 ;
      RECT 1.000 255.500 3.000 255.570 ;
    END
    PORT
      LAYER metal3 ;
      RECT 1.000 255.465 4.000 255.605 ;
    END
  END rd_out[228]
  PIN rd_out[229]
    DIRECTION OUTPUT ;
    USE SIGNAL ;
    PORT
      LAYER metal3 ;
      RECT 1.000 256.620 3.000 256.690 ;
    END
    PORT
      LAYER metal3 ;
      RECT 1.000 256.585 4.000 256.725 ;
    END
  END rd_out[229]
  PIN rd_out[230]
    DIRECTION OUTPUT ;
    USE SIGNAL ;
    PORT
      LAYER metal3 ;
      RECT 1.000 257.740 3.000 257.810 ;
    END
    PORT
      LAYER metal3 ;
      RECT 1.000 257.705 4.000 257.845 ;
    END
  END rd_out[230]
  PIN rd_out[231]
    DIRECTION OUTPUT ;
    USE SIGNAL ;
    PORT
      LAYER metal3 ;
      RECT 1.000 258.860 3.000 258.930 ;
    END
    PORT
      LAYER metal3 ;
      RECT 1.000 258.825 4.000 258.965 ;
    END
  END rd_out[231]
  PIN rd_out[232]
    DIRECTION OUTPUT ;
    USE SIGNAL ;
    PORT
      LAYER metal3 ;
      RECT 1.000 259.980 3.000 260.050 ;
    END
    PORT
      LAYER metal3 ;
      RECT 1.000 259.945 4.000 260.085 ;
    END
  END rd_out[232]
  PIN rd_out[233]
    DIRECTION OUTPUT ;
    USE SIGNAL ;
    PORT
      LAYER metal3 ;
      RECT 1.000 261.100 3.000 261.170 ;
    END
    PORT
      LAYER metal3 ;
      RECT 1.000 261.065 4.000 261.205 ;
    END
  END rd_out[233]
  PIN rd_out[234]
    DIRECTION OUTPUT ;
    USE SIGNAL ;
    PORT
      LAYER metal3 ;
      RECT 1.000 262.220 3.000 262.290 ;
    END
    PORT
      LAYER metal3 ;
      RECT 1.000 262.185 4.000 262.325 ;
    END
  END rd_out[234]
  PIN rd_out[235]
    DIRECTION OUTPUT ;
    USE SIGNAL ;
    PORT
      LAYER metal3 ;
      RECT 1.000 263.340 3.000 263.410 ;
    END
    PORT
      LAYER metal3 ;
      RECT 1.000 263.305 4.000 263.445 ;
    END
  END rd_out[235]
  PIN rd_out[236]
    DIRECTION OUTPUT ;
    USE SIGNAL ;
    PORT
      LAYER metal3 ;
      RECT 1.000 264.460 3.000 264.530 ;
    END
    PORT
      LAYER metal3 ;
      RECT 1.000 264.425 4.000 264.565 ;
    END
  END rd_out[236]
  PIN rd_out[237]
    DIRECTION OUTPUT ;
    USE SIGNAL ;
    PORT
      LAYER metal3 ;
      RECT 1.000 265.580 3.000 265.650 ;
    END
    PORT
      LAYER metal3 ;
      RECT 1.000 265.545 4.000 265.685 ;
    END
  END rd_out[237]
  PIN rd_out[238]
    DIRECTION OUTPUT ;
    USE SIGNAL ;
    PORT
      LAYER metal3 ;
      RECT 1.000 266.700 3.000 266.770 ;
    END
    PORT
      LAYER metal3 ;
      RECT 1.000 266.665 4.000 266.805 ;
    END
  END rd_out[238]
  PIN rd_out[239]
    DIRECTION OUTPUT ;
    USE SIGNAL ;
    PORT
      LAYER metal3 ;
      RECT 1.000 267.820 3.000 267.890 ;
    END
    PORT
      LAYER metal3 ;
      RECT 1.000 267.785 4.000 267.925 ;
    END
  END rd_out[239]
  PIN rd_out[240]
    DIRECTION OUTPUT ;
    USE SIGNAL ;
    PORT
      LAYER metal3 ;
      RECT 1.000 268.940 3.000 269.010 ;
    END
    PORT
      LAYER metal3 ;
      RECT 1.000 268.905 4.000 269.045 ;
    END
  END rd_out[240]
  PIN rd_out[241]
    DIRECTION OUTPUT ;
    USE SIGNAL ;
    PORT
      LAYER metal3 ;
      RECT 1.000 270.060 3.000 270.130 ;
    END
    PORT
      LAYER metal3 ;
      RECT 1.000 270.025 4.000 270.165 ;
    END
  END rd_out[241]
  PIN rd_out[242]
    DIRECTION OUTPUT ;
    USE SIGNAL ;
    PORT
      LAYER metal3 ;
      RECT 1.000 271.180 3.000 271.250 ;
    END
    PORT
      LAYER metal3 ;
      RECT 1.000 271.145 4.000 271.285 ;
    END
  END rd_out[242]
  PIN rd_out[243]
    DIRECTION OUTPUT ;
    USE SIGNAL ;
    PORT
      LAYER metal3 ;
      RECT 1.000 272.300 3.000 272.370 ;
    END
    PORT
      LAYER metal3 ;
      RECT 1.000 272.265 4.000 272.405 ;
    END
  END rd_out[243]
  PIN rd_out[244]
    DIRECTION OUTPUT ;
    USE SIGNAL ;
    PORT
      LAYER metal3 ;
      RECT 1.000 273.420 3.000 273.490 ;
    END
    PORT
      LAYER metal3 ;
      RECT 1.000 273.385 4.000 273.525 ;
    END
  END rd_out[244]
  PIN rd_out[245]
    DIRECTION OUTPUT ;
    USE SIGNAL ;
    PORT
      LAYER metal3 ;
      RECT 1.000 274.540 3.000 274.610 ;
    END
    PORT
      LAYER metal3 ;
      RECT 1.000 274.505 4.000 274.645 ;
    END
  END rd_out[245]
  PIN rd_out[246]
    DIRECTION OUTPUT ;
    USE SIGNAL ;
    PORT
      LAYER metal3 ;
      RECT 1.000 275.660 3.000 275.730 ;
    END
    PORT
      LAYER metal3 ;
      RECT 1.000 275.625 4.000 275.765 ;
    END
  END rd_out[246]
  PIN rd_out[247]
    DIRECTION OUTPUT ;
    USE SIGNAL ;
    PORT
      LAYER metal3 ;
      RECT 1.000 276.780 3.000 276.850 ;
    END
    PORT
      LAYER metal3 ;
      RECT 1.000 276.745 4.000 276.885 ;
    END
  END rd_out[247]
  PIN rd_out[248]
    DIRECTION OUTPUT ;
    USE SIGNAL ;
    PORT
      LAYER metal3 ;
      RECT 1.000 277.900 3.000 277.970 ;
    END
    PORT
      LAYER metal3 ;
      RECT 1.000 277.865 4.000 278.005 ;
    END
  END rd_out[248]
  PIN rd_out[249]
    DIRECTION OUTPUT ;
    USE SIGNAL ;
    PORT
      LAYER metal3 ;
      RECT 1.000 279.020 3.000 279.090 ;
    END
    PORT
      LAYER metal3 ;
      RECT 1.000 278.985 4.000 279.125 ;
    END
  END rd_out[249]
  PIN rd_out[250]
    DIRECTION OUTPUT ;
    USE SIGNAL ;
    PORT
      LAYER metal3 ;
      RECT 1.000 280.140 3.000 280.210 ;
    END
    PORT
      LAYER metal3 ;
      RECT 1.000 280.105 4.000 280.245 ;
    END
  END rd_out[250]
  PIN rd_out[251]
    DIRECTION OUTPUT ;
    USE SIGNAL ;
    PORT
      LAYER metal3 ;
      RECT 1.000 281.260 3.000 281.330 ;
    END
    PORT
      LAYER metal3 ;
      RECT 1.000 281.225 4.000 281.365 ;
    END
  END rd_out[251]
  PIN rd_out[252]
    DIRECTION OUTPUT ;
    USE SIGNAL ;
    PORT
      LAYER metal3 ;
      RECT 1.000 282.380 3.000 282.450 ;
    END
    PORT
      LAYER metal3 ;
      RECT 1.000 282.345 4.000 282.485 ;
    END
  END rd_out[252]
  PIN rd_out[253]
    DIRECTION OUTPUT ;
    USE SIGNAL ;
    PORT
      LAYER metal3 ;
      RECT 1.000 283.500 3.000 283.570 ;
    END
    PORT
      LAYER metal3 ;
      RECT 1.000 283.465 4.000 283.605 ;
    END
  END rd_out[253]
  PIN rd_out[254]
    DIRECTION OUTPUT ;
    USE SIGNAL ;
    PORT
      LAYER metal3 ;
      RECT 1.000 284.620 3.000 284.690 ;
    END
    PORT
      LAYER metal3 ;
      RECT 1.000 284.585 4.000 284.725 ;
    END
  END rd_out[254]
  PIN rd_out[255]
    DIRECTION OUTPUT ;
    USE SIGNAL ;
    PORT
      LAYER metal3 ;
      RECT 1.000 285.740 3.000 285.810 ;
    END
    PORT
      LAYER metal3 ;
      RECT 1.000 285.705 4.000 285.845 ;
    END
  END rd_out[255]
  PIN wd_in[0]
    DIRECTION INPUT ;
    USE SIGNAL ;
    PORT
      LAYER metal3 ;
      RECT 1.000 306.180 3.000 306.250 ;
    END
    PORT
      LAYER metal3 ;
      RECT 1.000 306.145 4.000 306.285 ;
    END
  END wd_in[0]
  PIN wd_in[1]
    DIRECTION INPUT ;
    USE SIGNAL ;
    PORT
      LAYER metal3 ;
      RECT 1.000 307.300 3.000 307.370 ;
    END
    PORT
      LAYER metal3 ;
      RECT 1.000 307.265 4.000 307.405 ;
    END
  END wd_in[1]
  PIN wd_in[2]
    DIRECTION INPUT ;
    USE SIGNAL ;
    PORT
      LAYER metal3 ;
      RECT 1.000 308.420 3.000 308.490 ;
    END
    PORT
      LAYER metal3 ;
      RECT 1.000 308.385 4.000 308.525 ;
    END
  END wd_in[2]
  PIN wd_in[3]
    DIRECTION INPUT ;
    USE SIGNAL ;
    PORT
      LAYER metal3 ;
      RECT 1.000 309.540 3.000 309.610 ;
    END
    PORT
      LAYER metal3 ;
      RECT 1.000 309.505 4.000 309.645 ;
    END
  END wd_in[3]
  PIN wd_in[4]
    DIRECTION INPUT ;
    USE SIGNAL ;
    PORT
      LAYER metal3 ;
      RECT 1.000 310.660 3.000 310.730 ;
    END
    PORT
      LAYER metal3 ;
      RECT 1.000 310.625 4.000 310.765 ;
    END
  END wd_in[4]
  PIN wd_in[5]
    DIRECTION INPUT ;
    USE SIGNAL ;
    PORT
      LAYER metal3 ;
      RECT 1.000 311.780 3.000 311.850 ;
    END
    PORT
      LAYER metal3 ;
      RECT 1.000 311.745 4.000 311.885 ;
    END
  END wd_in[5]
  PIN wd_in[6]
    DIRECTION INPUT ;
    USE SIGNAL ;
    PORT
      LAYER metal3 ;
      RECT 1.000 312.900 3.000 312.970 ;
    END
    PORT
      LAYER metal3 ;
      RECT 1.000 312.865 4.000 313.005 ;
    END
  END wd_in[6]
  PIN wd_in[7]
    DIRECTION INPUT ;
    USE SIGNAL ;
    PORT
      LAYER metal3 ;
      RECT 1.000 314.020 3.000 314.090 ;
    END
    PORT
      LAYER metal3 ;
      RECT 1.000 313.985 4.000 314.125 ;
    END
  END wd_in[7]
  PIN wd_in[8]
    DIRECTION INPUT ;
    USE SIGNAL ;
    PORT
      LAYER metal3 ;
      RECT 1.000 315.140 3.000 315.210 ;
    END
    PORT
      LAYER metal3 ;
      RECT 1.000 315.105 4.000 315.245 ;
    END
  END wd_in[8]
  PIN wd_in[9]
    DIRECTION INPUT ;
    USE SIGNAL ;
    PORT
      LAYER metal3 ;
      RECT 1.000 316.260 3.000 316.330 ;
    END
    PORT
      LAYER metal3 ;
      RECT 1.000 316.225 4.000 316.365 ;
    END
  END wd_in[9]
  PIN wd_in[10]
    DIRECTION INPUT ;
    USE SIGNAL ;
    PORT
      LAYER metal3 ;
      RECT 1.000 317.380 3.000 317.450 ;
    END
    PORT
      LAYER metal3 ;
      RECT 1.000 317.345 4.000 317.485 ;
    END
  END wd_in[10]
  PIN wd_in[11]
    DIRECTION INPUT ;
    USE SIGNAL ;
    PORT
      LAYER metal3 ;
      RECT 1.000 318.500 3.000 318.570 ;
    END
    PORT
      LAYER metal3 ;
      RECT 1.000 318.465 4.000 318.605 ;
    END
  END wd_in[11]
  PIN wd_in[12]
    DIRECTION INPUT ;
    USE SIGNAL ;
    PORT
      LAYER metal3 ;
      RECT 1.000 319.620 3.000 319.690 ;
    END
    PORT
      LAYER metal3 ;
      RECT 1.000 319.585 4.000 319.725 ;
    END
  END wd_in[12]
  PIN wd_in[13]
    DIRECTION INPUT ;
    USE SIGNAL ;
    PORT
      LAYER metal3 ;
      RECT 1.000 320.740 3.000 320.810 ;
    END
    PORT
      LAYER metal3 ;
      RECT 1.000 320.705 4.000 320.845 ;
    END
  END wd_in[13]
  PIN wd_in[14]
    DIRECTION INPUT ;
    USE SIGNAL ;
    PORT
      LAYER metal3 ;
      RECT 1.000 321.860 3.000 321.930 ;
    END
    PORT
      LAYER metal3 ;
      RECT 1.000 321.825 4.000 321.965 ;
    END
  END wd_in[14]
  PIN wd_in[15]
    DIRECTION INPUT ;
    USE SIGNAL ;
    PORT
      LAYER metal3 ;
      RECT 1.000 322.980 3.000 323.050 ;
    END
    PORT
      LAYER metal3 ;
      RECT 1.000 322.945 4.000 323.085 ;
    END
  END wd_in[15]
  PIN wd_in[16]
    DIRECTION INPUT ;
    USE SIGNAL ;
    PORT
      LAYER metal3 ;
      RECT 1.000 324.100 3.000 324.170 ;
    END
    PORT
      LAYER metal3 ;
      RECT 1.000 324.065 4.000 324.205 ;
    END
  END wd_in[16]
  PIN wd_in[17]
    DIRECTION INPUT ;
    USE SIGNAL ;
    PORT
      LAYER metal3 ;
      RECT 1.000 325.220 3.000 325.290 ;
    END
    PORT
      LAYER metal3 ;
      RECT 1.000 325.185 4.000 325.325 ;
    END
  END wd_in[17]
  PIN wd_in[18]
    DIRECTION INPUT ;
    USE SIGNAL ;
    PORT
      LAYER metal3 ;
      RECT 1.000 326.340 3.000 326.410 ;
    END
    PORT
      LAYER metal3 ;
      RECT 1.000 326.305 4.000 326.445 ;
    END
  END wd_in[18]
  PIN wd_in[19]
    DIRECTION INPUT ;
    USE SIGNAL ;
    PORT
      LAYER metal3 ;
      RECT 1.000 327.460 3.000 327.530 ;
    END
    PORT
      LAYER metal3 ;
      RECT 1.000 327.425 4.000 327.565 ;
    END
  END wd_in[19]
  PIN wd_in[20]
    DIRECTION INPUT ;
    USE SIGNAL ;
    PORT
      LAYER metal3 ;
      RECT 1.000 328.580 3.000 328.650 ;
    END
    PORT
      LAYER metal3 ;
      RECT 1.000 328.545 4.000 328.685 ;
    END
  END wd_in[20]
  PIN wd_in[21]
    DIRECTION INPUT ;
    USE SIGNAL ;
    PORT
      LAYER metal3 ;
      RECT 1.000 329.700 3.000 329.770 ;
    END
    PORT
      LAYER metal3 ;
      RECT 1.000 329.665 4.000 329.805 ;
    END
  END wd_in[21]
  PIN wd_in[22]
    DIRECTION INPUT ;
    USE SIGNAL ;
    PORT
      LAYER metal3 ;
      RECT 1.000 330.820 3.000 330.890 ;
    END
    PORT
      LAYER metal3 ;
      RECT 1.000 330.785 4.000 330.925 ;
    END
  END wd_in[22]
  PIN wd_in[23]
    DIRECTION INPUT ;
    USE SIGNAL ;
    PORT
      LAYER metal3 ;
      RECT 1.000 331.940 3.000 332.010 ;
    END
    PORT
      LAYER metal3 ;
      RECT 1.000 331.905 4.000 332.045 ;
    END
  END wd_in[23]
  PIN wd_in[24]
    DIRECTION INPUT ;
    USE SIGNAL ;
    PORT
      LAYER metal3 ;
      RECT 1.000 333.060 3.000 333.130 ;
    END
    PORT
      LAYER metal3 ;
      RECT 1.000 333.025 4.000 333.165 ;
    END
  END wd_in[24]
  PIN wd_in[25]
    DIRECTION INPUT ;
    USE SIGNAL ;
    PORT
      LAYER metal3 ;
      RECT 1.000 334.180 3.000 334.250 ;
    END
    PORT
      LAYER metal3 ;
      RECT 1.000 334.145 4.000 334.285 ;
    END
  END wd_in[25]
  PIN wd_in[26]
    DIRECTION INPUT ;
    USE SIGNAL ;
    PORT
      LAYER metal3 ;
      RECT 1.000 335.300 3.000 335.370 ;
    END
    PORT
      LAYER metal3 ;
      RECT 1.000 335.265 4.000 335.405 ;
    END
  END wd_in[26]
  PIN wd_in[27]
    DIRECTION INPUT ;
    USE SIGNAL ;
    PORT
      LAYER metal3 ;
      RECT 1.000 336.420 3.000 336.490 ;
    END
    PORT
      LAYER metal3 ;
      RECT 1.000 336.385 4.000 336.525 ;
    END
  END wd_in[27]
  PIN wd_in[28]
    DIRECTION INPUT ;
    USE SIGNAL ;
    PORT
      LAYER metal3 ;
      RECT 1.000 337.540 3.000 337.610 ;
    END
    PORT
      LAYER metal3 ;
      RECT 1.000 337.505 4.000 337.645 ;
    END
  END wd_in[28]
  PIN wd_in[29]
    DIRECTION INPUT ;
    USE SIGNAL ;
    PORT
      LAYER metal3 ;
      RECT 1.000 338.660 3.000 338.730 ;
    END
    PORT
      LAYER metal3 ;
      RECT 1.000 338.625 4.000 338.765 ;
    END
  END wd_in[29]
  PIN wd_in[30]
    DIRECTION INPUT ;
    USE SIGNAL ;
    PORT
      LAYER metal3 ;
      RECT 1.000 339.780 3.000 339.850 ;
    END
    PORT
      LAYER metal3 ;
      RECT 1.000 339.745 4.000 339.885 ;
    END
  END wd_in[30]
  PIN wd_in[31]
    DIRECTION INPUT ;
    USE SIGNAL ;
    PORT
      LAYER metal3 ;
      RECT 1.000 340.900 3.000 340.970 ;
    END
    PORT
      LAYER metal3 ;
      RECT 1.000 340.865 4.000 341.005 ;
    END
  END wd_in[31]
  PIN wd_in[32]
    DIRECTION INPUT ;
    USE SIGNAL ;
    PORT
      LAYER metal3 ;
      RECT 1.000 342.020 3.000 342.090 ;
    END
    PORT
      LAYER metal3 ;
      RECT 1.000 341.985 4.000 342.125 ;
    END
  END wd_in[32]
  PIN wd_in[33]
    DIRECTION INPUT ;
    USE SIGNAL ;
    PORT
      LAYER metal3 ;
      RECT 1.000 343.140 3.000 343.210 ;
    END
    PORT
      LAYER metal3 ;
      RECT 1.000 343.105 4.000 343.245 ;
    END
  END wd_in[33]
  PIN wd_in[34]
    DIRECTION INPUT ;
    USE SIGNAL ;
    PORT
      LAYER metal3 ;
      RECT 1.000 344.260 3.000 344.330 ;
    END
    PORT
      LAYER metal3 ;
      RECT 1.000 344.225 4.000 344.365 ;
    END
  END wd_in[34]
  PIN wd_in[35]
    DIRECTION INPUT ;
    USE SIGNAL ;
    PORT
      LAYER metal3 ;
      RECT 1.000 345.380 3.000 345.450 ;
    END
    PORT
      LAYER metal3 ;
      RECT 1.000 345.345 4.000 345.485 ;
    END
  END wd_in[35]
  PIN wd_in[36]
    DIRECTION INPUT ;
    USE SIGNAL ;
    PORT
      LAYER metal3 ;
      RECT 1.000 346.500 3.000 346.570 ;
    END
    PORT
      LAYER metal3 ;
      RECT 1.000 346.465 4.000 346.605 ;
    END
  END wd_in[36]
  PIN wd_in[37]
    DIRECTION INPUT ;
    USE SIGNAL ;
    PORT
      LAYER metal3 ;
      RECT 1.000 347.620 3.000 347.690 ;
    END
    PORT
      LAYER metal3 ;
      RECT 1.000 347.585 4.000 347.725 ;
    END
  END wd_in[37]
  PIN wd_in[38]
    DIRECTION INPUT ;
    USE SIGNAL ;
    PORT
      LAYER metal3 ;
      RECT 1.000 348.740 3.000 348.810 ;
    END
    PORT
      LAYER metal3 ;
      RECT 1.000 348.705 4.000 348.845 ;
    END
  END wd_in[38]
  PIN wd_in[39]
    DIRECTION INPUT ;
    USE SIGNAL ;
    PORT
      LAYER metal3 ;
      RECT 1.000 349.860 3.000 349.930 ;
    END
    PORT
      LAYER metal3 ;
      RECT 1.000 349.825 4.000 349.965 ;
    END
  END wd_in[39]
  PIN wd_in[40]
    DIRECTION INPUT ;
    USE SIGNAL ;
    PORT
      LAYER metal3 ;
      RECT 1.000 350.980 3.000 351.050 ;
    END
    PORT
      LAYER metal3 ;
      RECT 1.000 350.945 4.000 351.085 ;
    END
  END wd_in[40]
  PIN wd_in[41]
    DIRECTION INPUT ;
    USE SIGNAL ;
    PORT
      LAYER metal3 ;
      RECT 1.000 352.100 3.000 352.170 ;
    END
    PORT
      LAYER metal3 ;
      RECT 1.000 352.065 4.000 352.205 ;
    END
  END wd_in[41]
  PIN wd_in[42]
    DIRECTION INPUT ;
    USE SIGNAL ;
    PORT
      LAYER metal3 ;
      RECT 1.000 353.220 3.000 353.290 ;
    END
    PORT
      LAYER metal3 ;
      RECT 1.000 353.185 4.000 353.325 ;
    END
  END wd_in[42]
  PIN wd_in[43]
    DIRECTION INPUT ;
    USE SIGNAL ;
    PORT
      LAYER metal3 ;
      RECT 1.000 354.340 3.000 354.410 ;
    END
    PORT
      LAYER metal3 ;
      RECT 1.000 354.305 4.000 354.445 ;
    END
  END wd_in[43]
  PIN wd_in[44]
    DIRECTION INPUT ;
    USE SIGNAL ;
    PORT
      LAYER metal3 ;
      RECT 1.000 355.460 3.000 355.530 ;
    END
    PORT
      LAYER metal3 ;
      RECT 1.000 355.425 4.000 355.565 ;
    END
  END wd_in[44]
  PIN wd_in[45]
    DIRECTION INPUT ;
    USE SIGNAL ;
    PORT
      LAYER metal3 ;
      RECT 1.000 356.580 3.000 356.650 ;
    END
    PORT
      LAYER metal3 ;
      RECT 1.000 356.545 4.000 356.685 ;
    END
  END wd_in[45]
  PIN wd_in[46]
    DIRECTION INPUT ;
    USE SIGNAL ;
    PORT
      LAYER metal3 ;
      RECT 1.000 357.700 3.000 357.770 ;
    END
    PORT
      LAYER metal3 ;
      RECT 1.000 357.665 4.000 357.805 ;
    END
  END wd_in[46]
  PIN wd_in[47]
    DIRECTION INPUT ;
    USE SIGNAL ;
    PORT
      LAYER metal3 ;
      RECT 1.000 358.820 3.000 358.890 ;
    END
    PORT
      LAYER metal3 ;
      RECT 1.000 358.785 4.000 358.925 ;
    END
  END wd_in[47]
  PIN wd_in[48]
    DIRECTION INPUT ;
    USE SIGNAL ;
    PORT
      LAYER metal3 ;
      RECT 1.000 359.940 3.000 360.010 ;
    END
    PORT
      LAYER metal3 ;
      RECT 1.000 359.905 4.000 360.045 ;
    END
  END wd_in[48]
  PIN wd_in[49]
    DIRECTION INPUT ;
    USE SIGNAL ;
    PORT
      LAYER metal3 ;
      RECT 1.000 361.060 3.000 361.130 ;
    END
    PORT
      LAYER metal3 ;
      RECT 1.000 361.025 4.000 361.165 ;
    END
  END wd_in[49]
  PIN wd_in[50]
    DIRECTION INPUT ;
    USE SIGNAL ;
    PORT
      LAYER metal3 ;
      RECT 1.000 362.180 3.000 362.250 ;
    END
    PORT
      LAYER metal3 ;
      RECT 1.000 362.145 4.000 362.285 ;
    END
  END wd_in[50]
  PIN wd_in[51]
    DIRECTION INPUT ;
    USE SIGNAL ;
    PORT
      LAYER metal3 ;
      RECT 1.000 363.300 3.000 363.370 ;
    END
    PORT
      LAYER metal3 ;
      RECT 1.000 363.265 4.000 363.405 ;
    END
  END wd_in[51]
  PIN wd_in[52]
    DIRECTION INPUT ;
    USE SIGNAL ;
    PORT
      LAYER metal3 ;
      RECT 1.000 364.420 3.000 364.490 ;
    END
    PORT
      LAYER metal3 ;
      RECT 1.000 364.385 4.000 364.525 ;
    END
  END wd_in[52]
  PIN wd_in[53]
    DIRECTION INPUT ;
    USE SIGNAL ;
    PORT
      LAYER metal3 ;
      RECT 1.000 365.540 3.000 365.610 ;
    END
    PORT
      LAYER metal3 ;
      RECT 1.000 365.505 4.000 365.645 ;
    END
  END wd_in[53]
  PIN wd_in[54]
    DIRECTION INPUT ;
    USE SIGNAL ;
    PORT
      LAYER metal3 ;
      RECT 1.000 366.660 3.000 366.730 ;
    END
    PORT
      LAYER metal3 ;
      RECT 1.000 366.625 4.000 366.765 ;
    END
  END wd_in[54]
  PIN wd_in[55]
    DIRECTION INPUT ;
    USE SIGNAL ;
    PORT
      LAYER metal3 ;
      RECT 1.000 367.780 3.000 367.850 ;
    END
    PORT
      LAYER metal3 ;
      RECT 1.000 367.745 4.000 367.885 ;
    END
  END wd_in[55]
  PIN wd_in[56]
    DIRECTION INPUT ;
    USE SIGNAL ;
    PORT
      LAYER metal3 ;
      RECT 1.000 368.900 3.000 368.970 ;
    END
    PORT
      LAYER metal3 ;
      RECT 1.000 368.865 4.000 369.005 ;
    END
  END wd_in[56]
  PIN wd_in[57]
    DIRECTION INPUT ;
    USE SIGNAL ;
    PORT
      LAYER metal3 ;
      RECT 1.000 370.020 3.000 370.090 ;
    END
    PORT
      LAYER metal3 ;
      RECT 1.000 369.985 4.000 370.125 ;
    END
  END wd_in[57]
  PIN wd_in[58]
    DIRECTION INPUT ;
    USE SIGNAL ;
    PORT
      LAYER metal3 ;
      RECT 1.000 371.140 3.000 371.210 ;
    END
    PORT
      LAYER metal3 ;
      RECT 1.000 371.105 4.000 371.245 ;
    END
  END wd_in[58]
  PIN wd_in[59]
    DIRECTION INPUT ;
    USE SIGNAL ;
    PORT
      LAYER metal3 ;
      RECT 1.000 372.260 3.000 372.330 ;
    END
    PORT
      LAYER metal3 ;
      RECT 1.000 372.225 4.000 372.365 ;
    END
  END wd_in[59]
  PIN wd_in[60]
    DIRECTION INPUT ;
    USE SIGNAL ;
    PORT
      LAYER metal3 ;
      RECT 1.000 373.380 3.000 373.450 ;
    END
    PORT
      LAYER metal3 ;
      RECT 1.000 373.345 4.000 373.485 ;
    END
  END wd_in[60]
  PIN wd_in[61]
    DIRECTION INPUT ;
    USE SIGNAL ;
    PORT
      LAYER metal3 ;
      RECT 1.000 374.500 3.000 374.570 ;
    END
    PORT
      LAYER metal3 ;
      RECT 1.000 374.465 4.000 374.605 ;
    END
  END wd_in[61]
  PIN wd_in[62]
    DIRECTION INPUT ;
    USE SIGNAL ;
    PORT
      LAYER metal3 ;
      RECT 1.000 375.620 3.000 375.690 ;
    END
    PORT
      LAYER metal3 ;
      RECT 1.000 375.585 4.000 375.725 ;
    END
  END wd_in[62]
  PIN wd_in[63]
    DIRECTION INPUT ;
    USE SIGNAL ;
    PORT
      LAYER metal3 ;
      RECT 1.000 376.740 3.000 376.810 ;
    END
    PORT
      LAYER metal3 ;
      RECT 1.000 376.705 4.000 376.845 ;
    END
  END wd_in[63]
  PIN wd_in[64]
    DIRECTION INPUT ;
    USE SIGNAL ;
    PORT
      LAYER metal3 ;
      RECT 1.000 377.860 3.000 377.930 ;
    END
    PORT
      LAYER metal3 ;
      RECT 1.000 377.825 4.000 377.965 ;
    END
  END wd_in[64]
  PIN wd_in[65]
    DIRECTION INPUT ;
    USE SIGNAL ;
    PORT
      LAYER metal3 ;
      RECT 1.000 378.980 3.000 379.050 ;
    END
    PORT
      LAYER metal3 ;
      RECT 1.000 378.945 4.000 379.085 ;
    END
  END wd_in[65]
  PIN wd_in[66]
    DIRECTION INPUT ;
    USE SIGNAL ;
    PORT
      LAYER metal3 ;
      RECT 1.000 380.100 3.000 380.170 ;
    END
    PORT
      LAYER metal3 ;
      RECT 1.000 380.065 4.000 380.205 ;
    END
  END wd_in[66]
  PIN wd_in[67]
    DIRECTION INPUT ;
    USE SIGNAL ;
    PORT
      LAYER metal3 ;
      RECT 1.000 381.220 3.000 381.290 ;
    END
    PORT
      LAYER metal3 ;
      RECT 1.000 381.185 4.000 381.325 ;
    END
  END wd_in[67]
  PIN wd_in[68]
    DIRECTION INPUT ;
    USE SIGNAL ;
    PORT
      LAYER metal3 ;
      RECT 1.000 382.340 3.000 382.410 ;
    END
    PORT
      LAYER metal3 ;
      RECT 1.000 382.305 4.000 382.445 ;
    END
  END wd_in[68]
  PIN wd_in[69]
    DIRECTION INPUT ;
    USE SIGNAL ;
    PORT
      LAYER metal3 ;
      RECT 1.000 383.460 3.000 383.530 ;
    END
    PORT
      LAYER metal3 ;
      RECT 1.000 383.425 4.000 383.565 ;
    END
  END wd_in[69]
  PIN wd_in[70]
    DIRECTION INPUT ;
    USE SIGNAL ;
    PORT
      LAYER metal3 ;
      RECT 1.000 384.580 3.000 384.650 ;
    END
    PORT
      LAYER metal3 ;
      RECT 1.000 384.545 4.000 384.685 ;
    END
  END wd_in[70]
  PIN wd_in[71]
    DIRECTION INPUT ;
    USE SIGNAL ;
    PORT
      LAYER metal3 ;
      RECT 1.000 385.700 3.000 385.770 ;
    END
    PORT
      LAYER metal3 ;
      RECT 1.000 385.665 4.000 385.805 ;
    END
  END wd_in[71]
  PIN wd_in[72]
    DIRECTION INPUT ;
    USE SIGNAL ;
    PORT
      LAYER metal3 ;
      RECT 1.000 386.820 3.000 386.890 ;
    END
    PORT
      LAYER metal3 ;
      RECT 1.000 386.785 4.000 386.925 ;
    END
  END wd_in[72]
  PIN wd_in[73]
    DIRECTION INPUT ;
    USE SIGNAL ;
    PORT
      LAYER metal3 ;
      RECT 1.000 387.940 3.000 388.010 ;
    END
    PORT
      LAYER metal3 ;
      RECT 1.000 387.905 4.000 388.045 ;
    END
  END wd_in[73]
  PIN wd_in[74]
    DIRECTION INPUT ;
    USE SIGNAL ;
    PORT
      LAYER metal3 ;
      RECT 1.000 389.060 3.000 389.130 ;
    END
    PORT
      LAYER metal3 ;
      RECT 1.000 389.025 4.000 389.165 ;
    END
  END wd_in[74]
  PIN wd_in[75]
    DIRECTION INPUT ;
    USE SIGNAL ;
    PORT
      LAYER metal3 ;
      RECT 1.000 390.180 3.000 390.250 ;
    END
    PORT
      LAYER metal3 ;
      RECT 1.000 390.145 4.000 390.285 ;
    END
  END wd_in[75]
  PIN wd_in[76]
    DIRECTION INPUT ;
    USE SIGNAL ;
    PORT
      LAYER metal3 ;
      RECT 1.000 391.300 3.000 391.370 ;
    END
    PORT
      LAYER metal3 ;
      RECT 1.000 391.265 4.000 391.405 ;
    END
  END wd_in[76]
  PIN wd_in[77]
    DIRECTION INPUT ;
    USE SIGNAL ;
    PORT
      LAYER metal3 ;
      RECT 1.000 392.420 3.000 392.490 ;
    END
    PORT
      LAYER metal3 ;
      RECT 1.000 392.385 4.000 392.525 ;
    END
  END wd_in[77]
  PIN wd_in[78]
    DIRECTION INPUT ;
    USE SIGNAL ;
    PORT
      LAYER metal3 ;
      RECT 1.000 393.540 3.000 393.610 ;
    END
    PORT
      LAYER metal3 ;
      RECT 1.000 393.505 4.000 393.645 ;
    END
  END wd_in[78]
  PIN wd_in[79]
    DIRECTION INPUT ;
    USE SIGNAL ;
    PORT
      LAYER metal3 ;
      RECT 1.000 394.660 3.000 394.730 ;
    END
    PORT
      LAYER metal3 ;
      RECT 1.000 394.625 4.000 394.765 ;
    END
  END wd_in[79]
  PIN wd_in[80]
    DIRECTION INPUT ;
    USE SIGNAL ;
    PORT
      LAYER metal3 ;
      RECT 1.000 395.780 3.000 395.850 ;
    END
    PORT
      LAYER metal3 ;
      RECT 1.000 395.745 4.000 395.885 ;
    END
  END wd_in[80]
  PIN wd_in[81]
    DIRECTION INPUT ;
    USE SIGNAL ;
    PORT
      LAYER metal3 ;
      RECT 1.000 396.900 3.000 396.970 ;
    END
    PORT
      LAYER metal3 ;
      RECT 1.000 396.865 4.000 397.005 ;
    END
  END wd_in[81]
  PIN wd_in[82]
    DIRECTION INPUT ;
    USE SIGNAL ;
    PORT
      LAYER metal3 ;
      RECT 1.000 398.020 3.000 398.090 ;
    END
    PORT
      LAYER metal3 ;
      RECT 1.000 397.985 4.000 398.125 ;
    END
  END wd_in[82]
  PIN wd_in[83]
    DIRECTION INPUT ;
    USE SIGNAL ;
    PORT
      LAYER metal3 ;
      RECT 1.000 399.140 3.000 399.210 ;
    END
    PORT
      LAYER metal3 ;
      RECT 1.000 399.105 4.000 399.245 ;
    END
  END wd_in[83]
  PIN wd_in[84]
    DIRECTION INPUT ;
    USE SIGNAL ;
    PORT
      LAYER metal3 ;
      RECT 1.000 400.260 3.000 400.330 ;
    END
    PORT
      LAYER metal3 ;
      RECT 1.000 400.225 4.000 400.365 ;
    END
  END wd_in[84]
  PIN wd_in[85]
    DIRECTION INPUT ;
    USE SIGNAL ;
    PORT
      LAYER metal3 ;
      RECT 1.000 401.380 3.000 401.450 ;
    END
    PORT
      LAYER metal3 ;
      RECT 1.000 401.345 4.000 401.485 ;
    END
  END wd_in[85]
  PIN wd_in[86]
    DIRECTION INPUT ;
    USE SIGNAL ;
    PORT
      LAYER metal3 ;
      RECT 1.000 402.500 3.000 402.570 ;
    END
    PORT
      LAYER metal3 ;
      RECT 1.000 402.465 4.000 402.605 ;
    END
  END wd_in[86]
  PIN wd_in[87]
    DIRECTION INPUT ;
    USE SIGNAL ;
    PORT
      LAYER metal3 ;
      RECT 1.000 403.620 3.000 403.690 ;
    END
    PORT
      LAYER metal3 ;
      RECT 1.000 403.585 4.000 403.725 ;
    END
  END wd_in[87]
  PIN wd_in[88]
    DIRECTION INPUT ;
    USE SIGNAL ;
    PORT
      LAYER metal3 ;
      RECT 1.000 404.740 3.000 404.810 ;
    END
    PORT
      LAYER metal3 ;
      RECT 1.000 404.705 4.000 404.845 ;
    END
  END wd_in[88]
  PIN wd_in[89]
    DIRECTION INPUT ;
    USE SIGNAL ;
    PORT
      LAYER metal3 ;
      RECT 1.000 405.860 3.000 405.930 ;
    END
    PORT
      LAYER metal3 ;
      RECT 1.000 405.825 4.000 405.965 ;
    END
  END wd_in[89]
  PIN wd_in[90]
    DIRECTION INPUT ;
    USE SIGNAL ;
    PORT
      LAYER metal3 ;
      RECT 1.000 406.980 3.000 407.050 ;
    END
    PORT
      LAYER metal3 ;
      RECT 1.000 406.945 4.000 407.085 ;
    END
  END wd_in[90]
  PIN wd_in[91]
    DIRECTION INPUT ;
    USE SIGNAL ;
    PORT
      LAYER metal3 ;
      RECT 1.000 408.100 3.000 408.170 ;
    END
    PORT
      LAYER metal3 ;
      RECT 1.000 408.065 4.000 408.205 ;
    END
  END wd_in[91]
  PIN wd_in[92]
    DIRECTION INPUT ;
    USE SIGNAL ;
    PORT
      LAYER metal3 ;
      RECT 1.000 409.220 3.000 409.290 ;
    END
    PORT
      LAYER metal3 ;
      RECT 1.000 409.185 4.000 409.325 ;
    END
  END wd_in[92]
  PIN wd_in[93]
    DIRECTION INPUT ;
    USE SIGNAL ;
    PORT
      LAYER metal3 ;
      RECT 1.000 410.340 3.000 410.410 ;
    END
    PORT
      LAYER metal3 ;
      RECT 1.000 410.305 4.000 410.445 ;
    END
  END wd_in[93]
  PIN wd_in[94]
    DIRECTION INPUT ;
    USE SIGNAL ;
    PORT
      LAYER metal3 ;
      RECT 1.000 411.460 3.000 411.530 ;
    END
    PORT
      LAYER metal3 ;
      RECT 1.000 411.425 4.000 411.565 ;
    END
  END wd_in[94]
  PIN wd_in[95]
    DIRECTION INPUT ;
    USE SIGNAL ;
    PORT
      LAYER metal3 ;
      RECT 1.000 412.580 3.000 412.650 ;
    END
    PORT
      LAYER metal3 ;
      RECT 1.000 412.545 4.000 412.685 ;
    END
  END wd_in[95]
  PIN wd_in[96]
    DIRECTION INPUT ;
    USE SIGNAL ;
    PORT
      LAYER metal3 ;
      RECT 1.000 413.700 3.000 413.770 ;
    END
    PORT
      LAYER metal3 ;
      RECT 1.000 413.665 4.000 413.805 ;
    END
  END wd_in[96]
  PIN wd_in[97]
    DIRECTION INPUT ;
    USE SIGNAL ;
    PORT
      LAYER metal3 ;
      RECT 1.000 414.820 3.000 414.890 ;
    END
    PORT
      LAYER metal3 ;
      RECT 1.000 414.785 4.000 414.925 ;
    END
  END wd_in[97]
  PIN wd_in[98]
    DIRECTION INPUT ;
    USE SIGNAL ;
    PORT
      LAYER metal3 ;
      RECT 1.000 415.940 3.000 416.010 ;
    END
    PORT
      LAYER metal3 ;
      RECT 1.000 415.905 4.000 416.045 ;
    END
  END wd_in[98]
  PIN wd_in[99]
    DIRECTION INPUT ;
    USE SIGNAL ;
    PORT
      LAYER metal3 ;
      RECT 1.000 417.060 3.000 417.130 ;
    END
    PORT
      LAYER metal3 ;
      RECT 1.000 417.025 4.000 417.165 ;
    END
  END wd_in[99]
  PIN wd_in[100]
    DIRECTION INPUT ;
    USE SIGNAL ;
    PORT
      LAYER metal3 ;
      RECT 1.000 418.180 3.000 418.250 ;
    END
    PORT
      LAYER metal3 ;
      RECT 1.000 418.145 4.000 418.285 ;
    END
  END wd_in[100]
  PIN wd_in[101]
    DIRECTION INPUT ;
    USE SIGNAL ;
    PORT
      LAYER metal3 ;
      RECT 1.000 419.300 3.000 419.370 ;
    END
    PORT
      LAYER metal3 ;
      RECT 1.000 419.265 4.000 419.405 ;
    END
  END wd_in[101]
  PIN wd_in[102]
    DIRECTION INPUT ;
    USE SIGNAL ;
    PORT
      LAYER metal3 ;
      RECT 1.000 420.420 3.000 420.490 ;
    END
    PORT
      LAYER metal3 ;
      RECT 1.000 420.385 4.000 420.525 ;
    END
  END wd_in[102]
  PIN wd_in[103]
    DIRECTION INPUT ;
    USE SIGNAL ;
    PORT
      LAYER metal3 ;
      RECT 1.000 421.540 3.000 421.610 ;
    END
    PORT
      LAYER metal3 ;
      RECT 1.000 421.505 4.000 421.645 ;
    END
  END wd_in[103]
  PIN wd_in[104]
    DIRECTION INPUT ;
    USE SIGNAL ;
    PORT
      LAYER metal3 ;
      RECT 1.000 422.660 3.000 422.730 ;
    END
    PORT
      LAYER metal3 ;
      RECT 1.000 422.625 4.000 422.765 ;
    END
  END wd_in[104]
  PIN wd_in[105]
    DIRECTION INPUT ;
    USE SIGNAL ;
    PORT
      LAYER metal3 ;
      RECT 1.000 423.780 3.000 423.850 ;
    END
    PORT
      LAYER metal3 ;
      RECT 1.000 423.745 4.000 423.885 ;
    END
  END wd_in[105]
  PIN wd_in[106]
    DIRECTION INPUT ;
    USE SIGNAL ;
    PORT
      LAYER metal3 ;
      RECT 1.000 424.900 3.000 424.970 ;
    END
    PORT
      LAYER metal3 ;
      RECT 1.000 424.865 4.000 425.005 ;
    END
  END wd_in[106]
  PIN wd_in[107]
    DIRECTION INPUT ;
    USE SIGNAL ;
    PORT
      LAYER metal3 ;
      RECT 1.000 426.020 3.000 426.090 ;
    END
    PORT
      LAYER metal3 ;
      RECT 1.000 425.985 4.000 426.125 ;
    END
  END wd_in[107]
  PIN wd_in[108]
    DIRECTION INPUT ;
    USE SIGNAL ;
    PORT
      LAYER metal3 ;
      RECT 1.000 427.140 3.000 427.210 ;
    END
    PORT
      LAYER metal3 ;
      RECT 1.000 427.105 4.000 427.245 ;
    END
  END wd_in[108]
  PIN wd_in[109]
    DIRECTION INPUT ;
    USE SIGNAL ;
    PORT
      LAYER metal3 ;
      RECT 1.000 428.260 3.000 428.330 ;
    END
    PORT
      LAYER metal3 ;
      RECT 1.000 428.225 4.000 428.365 ;
    END
  END wd_in[109]
  PIN wd_in[110]
    DIRECTION INPUT ;
    USE SIGNAL ;
    PORT
      LAYER metal3 ;
      RECT 1.000 429.380 3.000 429.450 ;
    END
    PORT
      LAYER metal3 ;
      RECT 1.000 429.345 4.000 429.485 ;
    END
  END wd_in[110]
  PIN wd_in[111]
    DIRECTION INPUT ;
    USE SIGNAL ;
    PORT
      LAYER metal3 ;
      RECT 1.000 430.500 3.000 430.570 ;
    END
    PORT
      LAYER metal3 ;
      RECT 1.000 430.465 4.000 430.605 ;
    END
  END wd_in[111]
  PIN wd_in[112]
    DIRECTION INPUT ;
    USE SIGNAL ;
    PORT
      LAYER metal3 ;
      RECT 1.000 431.620 3.000 431.690 ;
    END
    PORT
      LAYER metal3 ;
      RECT 1.000 431.585 4.000 431.725 ;
    END
  END wd_in[112]
  PIN wd_in[113]
    DIRECTION INPUT ;
    USE SIGNAL ;
    PORT
      LAYER metal3 ;
      RECT 1.000 432.740 3.000 432.810 ;
    END
    PORT
      LAYER metal3 ;
      RECT 1.000 432.705 4.000 432.845 ;
    END
  END wd_in[113]
  PIN wd_in[114]
    DIRECTION INPUT ;
    USE SIGNAL ;
    PORT
      LAYER metal3 ;
      RECT 1.000 433.860 3.000 433.930 ;
    END
    PORT
      LAYER metal3 ;
      RECT 1.000 433.825 4.000 433.965 ;
    END
  END wd_in[114]
  PIN wd_in[115]
    DIRECTION INPUT ;
    USE SIGNAL ;
    PORT
      LAYER metal3 ;
      RECT 1.000 434.980 3.000 435.050 ;
    END
    PORT
      LAYER metal3 ;
      RECT 1.000 434.945 4.000 435.085 ;
    END
  END wd_in[115]
  PIN wd_in[116]
    DIRECTION INPUT ;
    USE SIGNAL ;
    PORT
      LAYER metal3 ;
      RECT 1.000 436.100 3.000 436.170 ;
    END
    PORT
      LAYER metal3 ;
      RECT 1.000 436.065 4.000 436.205 ;
    END
  END wd_in[116]
  PIN wd_in[117]
    DIRECTION INPUT ;
    USE SIGNAL ;
    PORT
      LAYER metal3 ;
      RECT 1.000 437.220 3.000 437.290 ;
    END
    PORT
      LAYER metal3 ;
      RECT 1.000 437.185 4.000 437.325 ;
    END
  END wd_in[117]
  PIN wd_in[118]
    DIRECTION INPUT ;
    USE SIGNAL ;
    PORT
      LAYER metal3 ;
      RECT 1.000 438.340 3.000 438.410 ;
    END
    PORT
      LAYER metal3 ;
      RECT 1.000 438.305 4.000 438.445 ;
    END
  END wd_in[118]
  PIN wd_in[119]
    DIRECTION INPUT ;
    USE SIGNAL ;
    PORT
      LAYER metal3 ;
      RECT 1.000 439.460 3.000 439.530 ;
    END
    PORT
      LAYER metal3 ;
      RECT 1.000 439.425 4.000 439.565 ;
    END
  END wd_in[119]
  PIN wd_in[120]
    DIRECTION INPUT ;
    USE SIGNAL ;
    PORT
      LAYER metal3 ;
      RECT 1.000 440.580 3.000 440.650 ;
    END
    PORT
      LAYER metal3 ;
      RECT 1.000 440.545 4.000 440.685 ;
    END
  END wd_in[120]
  PIN wd_in[121]
    DIRECTION INPUT ;
    USE SIGNAL ;
    PORT
      LAYER metal3 ;
      RECT 1.000 441.700 3.000 441.770 ;
    END
    PORT
      LAYER metal3 ;
      RECT 1.000 441.665 4.000 441.805 ;
    END
  END wd_in[121]
  PIN wd_in[122]
    DIRECTION INPUT ;
    USE SIGNAL ;
    PORT
      LAYER metal3 ;
      RECT 1.000 442.820 3.000 442.890 ;
    END
    PORT
      LAYER metal3 ;
      RECT 1.000 442.785 4.000 442.925 ;
    END
  END wd_in[122]
  PIN wd_in[123]
    DIRECTION INPUT ;
    USE SIGNAL ;
    PORT
      LAYER metal3 ;
      RECT 1.000 443.940 3.000 444.010 ;
    END
    PORT
      LAYER metal3 ;
      RECT 1.000 443.905 4.000 444.045 ;
    END
  END wd_in[123]
  PIN wd_in[124]
    DIRECTION INPUT ;
    USE SIGNAL ;
    PORT
      LAYER metal3 ;
      RECT 1.000 445.060 3.000 445.130 ;
    END
    PORT
      LAYER metal3 ;
      RECT 1.000 445.025 4.000 445.165 ;
    END
  END wd_in[124]
  PIN wd_in[125]
    DIRECTION INPUT ;
    USE SIGNAL ;
    PORT
      LAYER metal3 ;
      RECT 1.000 446.180 3.000 446.250 ;
    END
    PORT
      LAYER metal3 ;
      RECT 1.000 446.145 4.000 446.285 ;
    END
  END wd_in[125]
  PIN wd_in[126]
    DIRECTION INPUT ;
    USE SIGNAL ;
    PORT
      LAYER metal3 ;
      RECT 1.000 447.300 3.000 447.370 ;
    END
    PORT
      LAYER metal3 ;
      RECT 1.000 447.265 4.000 447.405 ;
    END
  END wd_in[126]
  PIN wd_in[127]
    DIRECTION INPUT ;
    USE SIGNAL ;
    PORT
      LAYER metal3 ;
      RECT 1.000 448.420 3.000 448.490 ;
    END
    PORT
      LAYER metal3 ;
      RECT 1.000 448.385 4.000 448.525 ;
    END
  END wd_in[127]
  PIN wd_in[128]
    DIRECTION INPUT ;
    USE SIGNAL ;
    PORT
      LAYER metal3 ;
      RECT 1.000 449.540 3.000 449.610 ;
    END
    PORT
      LAYER metal3 ;
      RECT 1.000 449.505 4.000 449.645 ;
    END
  END wd_in[128]
  PIN wd_in[129]
    DIRECTION INPUT ;
    USE SIGNAL ;
    PORT
      LAYER metal3 ;
      RECT 1.000 450.660 3.000 450.730 ;
    END
    PORT
      LAYER metal3 ;
      RECT 1.000 450.625 4.000 450.765 ;
    END
  END wd_in[129]
  PIN wd_in[130]
    DIRECTION INPUT ;
    USE SIGNAL ;
    PORT
      LAYER metal3 ;
      RECT 1.000 451.780 3.000 451.850 ;
    END
    PORT
      LAYER metal3 ;
      RECT 1.000 451.745 4.000 451.885 ;
    END
  END wd_in[130]
  PIN wd_in[131]
    DIRECTION INPUT ;
    USE SIGNAL ;
    PORT
      LAYER metal3 ;
      RECT 1.000 452.900 3.000 452.970 ;
    END
    PORT
      LAYER metal3 ;
      RECT 1.000 452.865 4.000 453.005 ;
    END
  END wd_in[131]
  PIN wd_in[132]
    DIRECTION INPUT ;
    USE SIGNAL ;
    PORT
      LAYER metal3 ;
      RECT 1.000 454.020 3.000 454.090 ;
    END
    PORT
      LAYER metal3 ;
      RECT 1.000 453.985 4.000 454.125 ;
    END
  END wd_in[132]
  PIN wd_in[133]
    DIRECTION INPUT ;
    USE SIGNAL ;
    PORT
      LAYER metal3 ;
      RECT 1.000 455.140 3.000 455.210 ;
    END
    PORT
      LAYER metal3 ;
      RECT 1.000 455.105 4.000 455.245 ;
    END
  END wd_in[133]
  PIN wd_in[134]
    DIRECTION INPUT ;
    USE SIGNAL ;
    PORT
      LAYER metal3 ;
      RECT 1.000 456.260 3.000 456.330 ;
    END
    PORT
      LAYER metal3 ;
      RECT 1.000 456.225 4.000 456.365 ;
    END
  END wd_in[134]
  PIN wd_in[135]
    DIRECTION INPUT ;
    USE SIGNAL ;
    PORT
      LAYER metal3 ;
      RECT 1.000 457.380 3.000 457.450 ;
    END
    PORT
      LAYER metal3 ;
      RECT 1.000 457.345 4.000 457.485 ;
    END
  END wd_in[135]
  PIN wd_in[136]
    DIRECTION INPUT ;
    USE SIGNAL ;
    PORT
      LAYER metal3 ;
      RECT 1.000 458.500 3.000 458.570 ;
    END
    PORT
      LAYER metal3 ;
      RECT 1.000 458.465 4.000 458.605 ;
    END
  END wd_in[136]
  PIN wd_in[137]
    DIRECTION INPUT ;
    USE SIGNAL ;
    PORT
      LAYER metal3 ;
      RECT 1.000 459.620 3.000 459.690 ;
    END
    PORT
      LAYER metal3 ;
      RECT 1.000 459.585 4.000 459.725 ;
    END
  END wd_in[137]
  PIN wd_in[138]
    DIRECTION INPUT ;
    USE SIGNAL ;
    PORT
      LAYER metal3 ;
      RECT 1.000 460.740 3.000 460.810 ;
    END
    PORT
      LAYER metal3 ;
      RECT 1.000 460.705 4.000 460.845 ;
    END
  END wd_in[138]
  PIN wd_in[139]
    DIRECTION INPUT ;
    USE SIGNAL ;
    PORT
      LAYER metal3 ;
      RECT 1.000 461.860 3.000 461.930 ;
    END
    PORT
      LAYER metal3 ;
      RECT 1.000 461.825 4.000 461.965 ;
    END
  END wd_in[139]
  PIN wd_in[140]
    DIRECTION INPUT ;
    USE SIGNAL ;
    PORT
      LAYER metal3 ;
      RECT 1.000 462.980 3.000 463.050 ;
    END
    PORT
      LAYER metal3 ;
      RECT 1.000 462.945 4.000 463.085 ;
    END
  END wd_in[140]
  PIN wd_in[141]
    DIRECTION INPUT ;
    USE SIGNAL ;
    PORT
      LAYER metal3 ;
      RECT 1.000 464.100 3.000 464.170 ;
    END
    PORT
      LAYER metal3 ;
      RECT 1.000 464.065 4.000 464.205 ;
    END
  END wd_in[141]
  PIN wd_in[142]
    DIRECTION INPUT ;
    USE SIGNAL ;
    PORT
      LAYER metal3 ;
      RECT 1.000 465.220 3.000 465.290 ;
    END
    PORT
      LAYER metal3 ;
      RECT 1.000 465.185 4.000 465.325 ;
    END
  END wd_in[142]
  PIN wd_in[143]
    DIRECTION INPUT ;
    USE SIGNAL ;
    PORT
      LAYER metal3 ;
      RECT 1.000 466.340 3.000 466.410 ;
    END
    PORT
      LAYER metal3 ;
      RECT 1.000 466.305 4.000 466.445 ;
    END
  END wd_in[143]
  PIN wd_in[144]
    DIRECTION INPUT ;
    USE SIGNAL ;
    PORT
      LAYER metal3 ;
      RECT 1.000 467.460 3.000 467.530 ;
    END
    PORT
      LAYER metal3 ;
      RECT 1.000 467.425 4.000 467.565 ;
    END
  END wd_in[144]
  PIN wd_in[145]
    DIRECTION INPUT ;
    USE SIGNAL ;
    PORT
      LAYER metal3 ;
      RECT 1.000 468.580 3.000 468.650 ;
    END
    PORT
      LAYER metal3 ;
      RECT 1.000 468.545 4.000 468.685 ;
    END
  END wd_in[145]
  PIN wd_in[146]
    DIRECTION INPUT ;
    USE SIGNAL ;
    PORT
      LAYER metal3 ;
      RECT 1.000 469.700 3.000 469.770 ;
    END
    PORT
      LAYER metal3 ;
      RECT 1.000 469.665 4.000 469.805 ;
    END
  END wd_in[146]
  PIN wd_in[147]
    DIRECTION INPUT ;
    USE SIGNAL ;
    PORT
      LAYER metal3 ;
      RECT 1.000 470.820 3.000 470.890 ;
    END
    PORT
      LAYER metal3 ;
      RECT 1.000 470.785 4.000 470.925 ;
    END
  END wd_in[147]
  PIN wd_in[148]
    DIRECTION INPUT ;
    USE SIGNAL ;
    PORT
      LAYER metal3 ;
      RECT 1.000 471.940 3.000 472.010 ;
    END
    PORT
      LAYER metal3 ;
      RECT 1.000 471.905 4.000 472.045 ;
    END
  END wd_in[148]
  PIN wd_in[149]
    DIRECTION INPUT ;
    USE SIGNAL ;
    PORT
      LAYER metal3 ;
      RECT 1.000 473.060 3.000 473.130 ;
    END
    PORT
      LAYER metal3 ;
      RECT 1.000 473.025 4.000 473.165 ;
    END
  END wd_in[149]
  PIN wd_in[150]
    DIRECTION INPUT ;
    USE SIGNAL ;
    PORT
      LAYER metal3 ;
      RECT 1.000 474.180 3.000 474.250 ;
    END
    PORT
      LAYER metal3 ;
      RECT 1.000 474.145 4.000 474.285 ;
    END
  END wd_in[150]
  PIN wd_in[151]
    DIRECTION INPUT ;
    USE SIGNAL ;
    PORT
      LAYER metal3 ;
      RECT 1.000 475.300 3.000 475.370 ;
    END
    PORT
      LAYER metal3 ;
      RECT 1.000 475.265 4.000 475.405 ;
    END
  END wd_in[151]
  PIN wd_in[152]
    DIRECTION INPUT ;
    USE SIGNAL ;
    PORT
      LAYER metal3 ;
      RECT 1.000 476.420 3.000 476.490 ;
    END
    PORT
      LAYER metal3 ;
      RECT 1.000 476.385 4.000 476.525 ;
    END
  END wd_in[152]
  PIN wd_in[153]
    DIRECTION INPUT ;
    USE SIGNAL ;
    PORT
      LAYER metal3 ;
      RECT 1.000 477.540 3.000 477.610 ;
    END
    PORT
      LAYER metal3 ;
      RECT 1.000 477.505 4.000 477.645 ;
    END
  END wd_in[153]
  PIN wd_in[154]
    DIRECTION INPUT ;
    USE SIGNAL ;
    PORT
      LAYER metal3 ;
      RECT 1.000 478.660 3.000 478.730 ;
    END
    PORT
      LAYER metal3 ;
      RECT 1.000 478.625 4.000 478.765 ;
    END
  END wd_in[154]
  PIN wd_in[155]
    DIRECTION INPUT ;
    USE SIGNAL ;
    PORT
      LAYER metal3 ;
      RECT 1.000 479.780 3.000 479.850 ;
    END
    PORT
      LAYER metal3 ;
      RECT 1.000 479.745 4.000 479.885 ;
    END
  END wd_in[155]
  PIN wd_in[156]
    DIRECTION INPUT ;
    USE SIGNAL ;
    PORT
      LAYER metal3 ;
      RECT 1.000 480.900 3.000 480.970 ;
    END
    PORT
      LAYER metal3 ;
      RECT 1.000 480.865 4.000 481.005 ;
    END
  END wd_in[156]
  PIN wd_in[157]
    DIRECTION INPUT ;
    USE SIGNAL ;
    PORT
      LAYER metal3 ;
      RECT 1.000 482.020 3.000 482.090 ;
    END
    PORT
      LAYER metal3 ;
      RECT 1.000 481.985 4.000 482.125 ;
    END
  END wd_in[157]
  PIN wd_in[158]
    DIRECTION INPUT ;
    USE SIGNAL ;
    PORT
      LAYER metal3 ;
      RECT 1.000 483.140 3.000 483.210 ;
    END
    PORT
      LAYER metal3 ;
      RECT 1.000 483.105 4.000 483.245 ;
    END
  END wd_in[158]
  PIN wd_in[159]
    DIRECTION INPUT ;
    USE SIGNAL ;
    PORT
      LAYER metal3 ;
      RECT 1.000 484.260 3.000 484.330 ;
    END
    PORT
      LAYER metal3 ;
      RECT 1.000 484.225 4.000 484.365 ;
    END
  END wd_in[159]
  PIN wd_in[160]
    DIRECTION INPUT ;
    USE SIGNAL ;
    PORT
      LAYER metal3 ;
      RECT 1.000 485.380 3.000 485.450 ;
    END
    PORT
      LAYER metal3 ;
      RECT 1.000 485.345 4.000 485.485 ;
    END
  END wd_in[160]
  PIN wd_in[161]
    DIRECTION INPUT ;
    USE SIGNAL ;
    PORT
      LAYER metal3 ;
      RECT 1.000 486.500 3.000 486.570 ;
    END
    PORT
      LAYER metal3 ;
      RECT 1.000 486.465 4.000 486.605 ;
    END
  END wd_in[161]
  PIN wd_in[162]
    DIRECTION INPUT ;
    USE SIGNAL ;
    PORT
      LAYER metal3 ;
      RECT 1.000 487.620 3.000 487.690 ;
    END
    PORT
      LAYER metal3 ;
      RECT 1.000 487.585 4.000 487.725 ;
    END
  END wd_in[162]
  PIN wd_in[163]
    DIRECTION INPUT ;
    USE SIGNAL ;
    PORT
      LAYER metal3 ;
      RECT 1.000 488.740 3.000 488.810 ;
    END
    PORT
      LAYER metal3 ;
      RECT 1.000 488.705 4.000 488.845 ;
    END
  END wd_in[163]
  PIN wd_in[164]
    DIRECTION INPUT ;
    USE SIGNAL ;
    PORT
      LAYER metal3 ;
      RECT 1.000 489.860 3.000 489.930 ;
    END
    PORT
      LAYER metal3 ;
      RECT 1.000 489.825 4.000 489.965 ;
    END
  END wd_in[164]
  PIN wd_in[165]
    DIRECTION INPUT ;
    USE SIGNAL ;
    PORT
      LAYER metal3 ;
      RECT 1.000 490.980 3.000 491.050 ;
    END
    PORT
      LAYER metal3 ;
      RECT 1.000 490.945 4.000 491.085 ;
    END
  END wd_in[165]
  PIN wd_in[166]
    DIRECTION INPUT ;
    USE SIGNAL ;
    PORT
      LAYER metal3 ;
      RECT 1.000 492.100 3.000 492.170 ;
    END
    PORT
      LAYER metal3 ;
      RECT 1.000 492.065 4.000 492.205 ;
    END
  END wd_in[166]
  PIN wd_in[167]
    DIRECTION INPUT ;
    USE SIGNAL ;
    PORT
      LAYER metal3 ;
      RECT 1.000 493.220 3.000 493.290 ;
    END
    PORT
      LAYER metal3 ;
      RECT 1.000 493.185 4.000 493.325 ;
    END
  END wd_in[167]
  PIN wd_in[168]
    DIRECTION INPUT ;
    USE SIGNAL ;
    PORT
      LAYER metal3 ;
      RECT 1.000 494.340 3.000 494.410 ;
    END
    PORT
      LAYER metal3 ;
      RECT 1.000 494.305 4.000 494.445 ;
    END
  END wd_in[168]
  PIN wd_in[169]
    DIRECTION INPUT ;
    USE SIGNAL ;
    PORT
      LAYER metal3 ;
      RECT 1.000 495.460 3.000 495.530 ;
    END
    PORT
      LAYER metal3 ;
      RECT 1.000 495.425 4.000 495.565 ;
    END
  END wd_in[169]
  PIN wd_in[170]
    DIRECTION INPUT ;
    USE SIGNAL ;
    PORT
      LAYER metal3 ;
      RECT 1.000 496.580 3.000 496.650 ;
    END
    PORT
      LAYER metal3 ;
      RECT 1.000 496.545 4.000 496.685 ;
    END
  END wd_in[170]
  PIN wd_in[171]
    DIRECTION INPUT ;
    USE SIGNAL ;
    PORT
      LAYER metal3 ;
      RECT 1.000 497.700 3.000 497.770 ;
    END
    PORT
      LAYER metal3 ;
      RECT 1.000 497.665 4.000 497.805 ;
    END
  END wd_in[171]
  PIN wd_in[172]
    DIRECTION INPUT ;
    USE SIGNAL ;
    PORT
      LAYER metal3 ;
      RECT 1.000 498.820 3.000 498.890 ;
    END
    PORT
      LAYER metal3 ;
      RECT 1.000 498.785 4.000 498.925 ;
    END
  END wd_in[172]
  PIN wd_in[173]
    DIRECTION INPUT ;
    USE SIGNAL ;
    PORT
      LAYER metal3 ;
      RECT 1.000 499.940 3.000 500.010 ;
    END
    PORT
      LAYER metal3 ;
      RECT 1.000 499.905 4.000 500.045 ;
    END
  END wd_in[173]
  PIN wd_in[174]
    DIRECTION INPUT ;
    USE SIGNAL ;
    PORT
      LAYER metal3 ;
      RECT 1.000 501.060 3.000 501.130 ;
    END
    PORT
      LAYER metal3 ;
      RECT 1.000 501.025 4.000 501.165 ;
    END
  END wd_in[174]
  PIN wd_in[175]
    DIRECTION INPUT ;
    USE SIGNAL ;
    PORT
      LAYER metal3 ;
      RECT 1.000 502.180 3.000 502.250 ;
    END
    PORT
      LAYER metal3 ;
      RECT 1.000 502.145 4.000 502.285 ;
    END
  END wd_in[175]
  PIN wd_in[176]
    DIRECTION INPUT ;
    USE SIGNAL ;
    PORT
      LAYER metal3 ;
      RECT 1.000 503.300 3.000 503.370 ;
    END
    PORT
      LAYER metal3 ;
      RECT 1.000 503.265 4.000 503.405 ;
    END
  END wd_in[176]
  PIN wd_in[177]
    DIRECTION INPUT ;
    USE SIGNAL ;
    PORT
      LAYER metal3 ;
      RECT 1.000 504.420 3.000 504.490 ;
    END
    PORT
      LAYER metal3 ;
      RECT 1.000 504.385 4.000 504.525 ;
    END
  END wd_in[177]
  PIN wd_in[178]
    DIRECTION INPUT ;
    USE SIGNAL ;
    PORT
      LAYER metal3 ;
      RECT 1.000 505.540 3.000 505.610 ;
    END
    PORT
      LAYER metal3 ;
      RECT 1.000 505.505 4.000 505.645 ;
    END
  END wd_in[178]
  PIN wd_in[179]
    DIRECTION INPUT ;
    USE SIGNAL ;
    PORT
      LAYER metal3 ;
      RECT 1.000 506.660 3.000 506.730 ;
    END
    PORT
      LAYER metal3 ;
      RECT 1.000 506.625 4.000 506.765 ;
    END
  END wd_in[179]
  PIN wd_in[180]
    DIRECTION INPUT ;
    USE SIGNAL ;
    PORT
      LAYER metal3 ;
      RECT 1.000 507.780 3.000 507.850 ;
    END
    PORT
      LAYER metal3 ;
      RECT 1.000 507.745 4.000 507.885 ;
    END
  END wd_in[180]
  PIN wd_in[181]
    DIRECTION INPUT ;
    USE SIGNAL ;
    PORT
      LAYER metal3 ;
      RECT 1.000 508.900 3.000 508.970 ;
    END
    PORT
      LAYER metal3 ;
      RECT 1.000 508.865 4.000 509.005 ;
    END
  END wd_in[181]
  PIN wd_in[182]
    DIRECTION INPUT ;
    USE SIGNAL ;
    PORT
      LAYER metal3 ;
      RECT 1.000 510.020 3.000 510.090 ;
    END
    PORT
      LAYER metal3 ;
      RECT 1.000 509.985 4.000 510.125 ;
    END
  END wd_in[182]
  PIN wd_in[183]
    DIRECTION INPUT ;
    USE SIGNAL ;
    PORT
      LAYER metal3 ;
      RECT 1.000 511.140 3.000 511.210 ;
    END
    PORT
      LAYER metal3 ;
      RECT 1.000 511.105 4.000 511.245 ;
    END
  END wd_in[183]
  PIN wd_in[184]
    DIRECTION INPUT ;
    USE SIGNAL ;
    PORT
      LAYER metal3 ;
      RECT 1.000 512.260 3.000 512.330 ;
    END
    PORT
      LAYER metal3 ;
      RECT 1.000 512.225 4.000 512.365 ;
    END
  END wd_in[184]
  PIN wd_in[185]
    DIRECTION INPUT ;
    USE SIGNAL ;
    PORT
      LAYER metal3 ;
      RECT 1.000 513.380 3.000 513.450 ;
    END
    PORT
      LAYER metal3 ;
      RECT 1.000 513.345 4.000 513.485 ;
    END
  END wd_in[185]
  PIN wd_in[186]
    DIRECTION INPUT ;
    USE SIGNAL ;
    PORT
      LAYER metal3 ;
      RECT 1.000 514.500 3.000 514.570 ;
    END
    PORT
      LAYER metal3 ;
      RECT 1.000 514.465 4.000 514.605 ;
    END
  END wd_in[186]
  PIN wd_in[187]
    DIRECTION INPUT ;
    USE SIGNAL ;
    PORT
      LAYER metal3 ;
      RECT 1.000 515.620 3.000 515.690 ;
    END
    PORT
      LAYER metal3 ;
      RECT 1.000 515.585 4.000 515.725 ;
    END
  END wd_in[187]
  PIN wd_in[188]
    DIRECTION INPUT ;
    USE SIGNAL ;
    PORT
      LAYER metal3 ;
      RECT 1.000 516.740 3.000 516.810 ;
    END
    PORT
      LAYER metal3 ;
      RECT 1.000 516.705 4.000 516.845 ;
    END
  END wd_in[188]
  PIN wd_in[189]
    DIRECTION INPUT ;
    USE SIGNAL ;
    PORT
      LAYER metal3 ;
      RECT 1.000 517.860 3.000 517.930 ;
    END
    PORT
      LAYER metal3 ;
      RECT 1.000 517.825 4.000 517.965 ;
    END
  END wd_in[189]
  PIN wd_in[190]
    DIRECTION INPUT ;
    USE SIGNAL ;
    PORT
      LAYER metal3 ;
      RECT 1.000 518.980 3.000 519.050 ;
    END
    PORT
      LAYER metal3 ;
      RECT 1.000 518.945 4.000 519.085 ;
    END
  END wd_in[190]
  PIN wd_in[191]
    DIRECTION INPUT ;
    USE SIGNAL ;
    PORT
      LAYER metal3 ;
      RECT 1.000 520.100 3.000 520.170 ;
    END
    PORT
      LAYER metal3 ;
      RECT 1.000 520.065 4.000 520.205 ;
    END
  END wd_in[191]
  PIN wd_in[192]
    DIRECTION INPUT ;
    USE SIGNAL ;
    PORT
      LAYER metal3 ;
      RECT 1.000 521.220 3.000 521.290 ;
    END
    PORT
      LAYER metal3 ;
      RECT 1.000 521.185 4.000 521.325 ;
    END
  END wd_in[192]
  PIN wd_in[193]
    DIRECTION INPUT ;
    USE SIGNAL ;
    PORT
      LAYER metal3 ;
      RECT 1.000 522.340 3.000 522.410 ;
    END
    PORT
      LAYER metal3 ;
      RECT 1.000 522.305 4.000 522.445 ;
    END
  END wd_in[193]
  PIN wd_in[194]
    DIRECTION INPUT ;
    USE SIGNAL ;
    PORT
      LAYER metal3 ;
      RECT 1.000 523.460 3.000 523.530 ;
    END
    PORT
      LAYER metal3 ;
      RECT 1.000 523.425 4.000 523.565 ;
    END
  END wd_in[194]
  PIN wd_in[195]
    DIRECTION INPUT ;
    USE SIGNAL ;
    PORT
      LAYER metal3 ;
      RECT 1.000 524.580 3.000 524.650 ;
    END
    PORT
      LAYER metal3 ;
      RECT 1.000 524.545 4.000 524.685 ;
    END
  END wd_in[195]
  PIN wd_in[196]
    DIRECTION INPUT ;
    USE SIGNAL ;
    PORT
      LAYER metal3 ;
      RECT 1.000 525.700 3.000 525.770 ;
    END
    PORT
      LAYER metal3 ;
      RECT 1.000 525.665 4.000 525.805 ;
    END
  END wd_in[196]
  PIN wd_in[197]
    DIRECTION INPUT ;
    USE SIGNAL ;
    PORT
      LAYER metal3 ;
      RECT 1.000 526.820 3.000 526.890 ;
    END
    PORT
      LAYER metal3 ;
      RECT 1.000 526.785 4.000 526.925 ;
    END
  END wd_in[197]
  PIN wd_in[198]
    DIRECTION INPUT ;
    USE SIGNAL ;
    PORT
      LAYER metal3 ;
      RECT 1.000 527.940 3.000 528.010 ;
    END
    PORT
      LAYER metal3 ;
      RECT 1.000 527.905 4.000 528.045 ;
    END
  END wd_in[198]
  PIN wd_in[199]
    DIRECTION INPUT ;
    USE SIGNAL ;
    PORT
      LAYER metal3 ;
      RECT 1.000 529.060 3.000 529.130 ;
    END
    PORT
      LAYER metal3 ;
      RECT 1.000 529.025 4.000 529.165 ;
    END
  END wd_in[199]
  PIN wd_in[200]
    DIRECTION INPUT ;
    USE SIGNAL ;
    PORT
      LAYER metal3 ;
      RECT 1.000 530.180 3.000 530.250 ;
    END
    PORT
      LAYER metal3 ;
      RECT 1.000 530.145 4.000 530.285 ;
    END
  END wd_in[200]
  PIN wd_in[201]
    DIRECTION INPUT ;
    USE SIGNAL ;
    PORT
      LAYER metal3 ;
      RECT 1.000 531.300 3.000 531.370 ;
    END
    PORT
      LAYER metal3 ;
      RECT 1.000 531.265 4.000 531.405 ;
    END
  END wd_in[201]
  PIN wd_in[202]
    DIRECTION INPUT ;
    USE SIGNAL ;
    PORT
      LAYER metal3 ;
      RECT 1.000 532.420 3.000 532.490 ;
    END
    PORT
      LAYER metal3 ;
      RECT 1.000 532.385 4.000 532.525 ;
    END
  END wd_in[202]
  PIN wd_in[203]
    DIRECTION INPUT ;
    USE SIGNAL ;
    PORT
      LAYER metal3 ;
      RECT 1.000 533.540 3.000 533.610 ;
    END
    PORT
      LAYER metal3 ;
      RECT 1.000 533.505 4.000 533.645 ;
    END
  END wd_in[203]
  PIN wd_in[204]
    DIRECTION INPUT ;
    USE SIGNAL ;
    PORT
      LAYER metal3 ;
      RECT 1.000 534.660 3.000 534.730 ;
    END
    PORT
      LAYER metal3 ;
      RECT 1.000 534.625 4.000 534.765 ;
    END
  END wd_in[204]
  PIN wd_in[205]
    DIRECTION INPUT ;
    USE SIGNAL ;
    PORT
      LAYER metal3 ;
      RECT 1.000 535.780 3.000 535.850 ;
    END
    PORT
      LAYER metal3 ;
      RECT 1.000 535.745 4.000 535.885 ;
    END
  END wd_in[205]
  PIN wd_in[206]
    DIRECTION INPUT ;
    USE SIGNAL ;
    PORT
      LAYER metal3 ;
      RECT 1.000 536.900 3.000 536.970 ;
    END
    PORT
      LAYER metal3 ;
      RECT 1.000 536.865 4.000 537.005 ;
    END
  END wd_in[206]
  PIN wd_in[207]
    DIRECTION INPUT ;
    USE SIGNAL ;
    PORT
      LAYER metal3 ;
      RECT 1.000 538.020 3.000 538.090 ;
    END
    PORT
      LAYER metal3 ;
      RECT 1.000 537.985 4.000 538.125 ;
    END
  END wd_in[207]
  PIN wd_in[208]
    DIRECTION INPUT ;
    USE SIGNAL ;
    PORT
      LAYER metal3 ;
      RECT 1.000 539.140 3.000 539.210 ;
    END
    PORT
      LAYER metal3 ;
      RECT 1.000 539.105 4.000 539.245 ;
    END
  END wd_in[208]
  PIN wd_in[209]
    DIRECTION INPUT ;
    USE SIGNAL ;
    PORT
      LAYER metal3 ;
      RECT 1.000 540.260 3.000 540.330 ;
    END
    PORT
      LAYER metal3 ;
      RECT 1.000 540.225 4.000 540.365 ;
    END
  END wd_in[209]
  PIN wd_in[210]
    DIRECTION INPUT ;
    USE SIGNAL ;
    PORT
      LAYER metal3 ;
      RECT 1.000 541.380 3.000 541.450 ;
    END
    PORT
      LAYER metal3 ;
      RECT 1.000 541.345 4.000 541.485 ;
    END
  END wd_in[210]
  PIN wd_in[211]
    DIRECTION INPUT ;
    USE SIGNAL ;
    PORT
      LAYER metal3 ;
      RECT 1.000 542.500 3.000 542.570 ;
    END
    PORT
      LAYER metal3 ;
      RECT 1.000 542.465 4.000 542.605 ;
    END
  END wd_in[211]
  PIN wd_in[212]
    DIRECTION INPUT ;
    USE SIGNAL ;
    PORT
      LAYER metal3 ;
      RECT 1.000 543.620 3.000 543.690 ;
    END
    PORT
      LAYER metal3 ;
      RECT 1.000 543.585 4.000 543.725 ;
    END
  END wd_in[212]
  PIN wd_in[213]
    DIRECTION INPUT ;
    USE SIGNAL ;
    PORT
      LAYER metal3 ;
      RECT 1.000 544.740 3.000 544.810 ;
    END
    PORT
      LAYER metal3 ;
      RECT 1.000 544.705 4.000 544.845 ;
    END
  END wd_in[213]
  PIN wd_in[214]
    DIRECTION INPUT ;
    USE SIGNAL ;
    PORT
      LAYER metal3 ;
      RECT 1.000 545.860 3.000 545.930 ;
    END
    PORT
      LAYER metal3 ;
      RECT 1.000 545.825 4.000 545.965 ;
    END
  END wd_in[214]
  PIN wd_in[215]
    DIRECTION INPUT ;
    USE SIGNAL ;
    PORT
      LAYER metal3 ;
      RECT 1.000 546.980 3.000 547.050 ;
    END
    PORT
      LAYER metal3 ;
      RECT 1.000 546.945 4.000 547.085 ;
    END
  END wd_in[215]
  PIN wd_in[216]
    DIRECTION INPUT ;
    USE SIGNAL ;
    PORT
      LAYER metal3 ;
      RECT 1.000 548.100 3.000 548.170 ;
    END
    PORT
      LAYER metal3 ;
      RECT 1.000 548.065 4.000 548.205 ;
    END
  END wd_in[216]
  PIN wd_in[217]
    DIRECTION INPUT ;
    USE SIGNAL ;
    PORT
      LAYER metal3 ;
      RECT 1.000 549.220 3.000 549.290 ;
    END
    PORT
      LAYER metal3 ;
      RECT 1.000 549.185 4.000 549.325 ;
    END
  END wd_in[217]
  PIN wd_in[218]
    DIRECTION INPUT ;
    USE SIGNAL ;
    PORT
      LAYER metal3 ;
      RECT 1.000 550.340 3.000 550.410 ;
    END
    PORT
      LAYER metal3 ;
      RECT 1.000 550.305 4.000 550.445 ;
    END
  END wd_in[218]
  PIN wd_in[219]
    DIRECTION INPUT ;
    USE SIGNAL ;
    PORT
      LAYER metal3 ;
      RECT 1.000 551.460 3.000 551.530 ;
    END
    PORT
      LAYER metal3 ;
      RECT 1.000 551.425 4.000 551.565 ;
    END
  END wd_in[219]
  PIN wd_in[220]
    DIRECTION INPUT ;
    USE SIGNAL ;
    PORT
      LAYER metal3 ;
      RECT 1.000 552.580 3.000 552.650 ;
    END
    PORT
      LAYER metal3 ;
      RECT 1.000 552.545 4.000 552.685 ;
    END
  END wd_in[220]
  PIN wd_in[221]
    DIRECTION INPUT ;
    USE SIGNAL ;
    PORT
      LAYER metal3 ;
      RECT 1.000 553.700 3.000 553.770 ;
    END
    PORT
      LAYER metal3 ;
      RECT 1.000 553.665 4.000 553.805 ;
    END
  END wd_in[221]
  PIN wd_in[222]
    DIRECTION INPUT ;
    USE SIGNAL ;
    PORT
      LAYER metal3 ;
      RECT 1.000 554.820 3.000 554.890 ;
    END
    PORT
      LAYER metal3 ;
      RECT 1.000 554.785 4.000 554.925 ;
    END
  END wd_in[222]
  PIN wd_in[223]
    DIRECTION INPUT ;
    USE SIGNAL ;
    PORT
      LAYER metal3 ;
      RECT 1.000 555.940 3.000 556.010 ;
    END
    PORT
      LAYER metal3 ;
      RECT 1.000 555.905 4.000 556.045 ;
    END
  END wd_in[223]
  PIN wd_in[224]
    DIRECTION INPUT ;
    USE SIGNAL ;
    PORT
      LAYER metal3 ;
      RECT 1.000 557.060 3.000 557.130 ;
    END
    PORT
      LAYER metal3 ;
      RECT 1.000 557.025 4.000 557.165 ;
    END
  END wd_in[224]
  PIN wd_in[225]
    DIRECTION INPUT ;
    USE SIGNAL ;
    PORT
      LAYER metal3 ;
      RECT 1.000 558.180 3.000 558.250 ;
    END
    PORT
      LAYER metal3 ;
      RECT 1.000 558.145 4.000 558.285 ;
    END
  END wd_in[225]
  PIN wd_in[226]
    DIRECTION INPUT ;
    USE SIGNAL ;
    PORT
      LAYER metal3 ;
      RECT 1.000 559.300 3.000 559.370 ;
    END
    PORT
      LAYER metal3 ;
      RECT 1.000 559.265 4.000 559.405 ;
    END
  END wd_in[226]
  PIN wd_in[227]
    DIRECTION INPUT ;
    USE SIGNAL ;
    PORT
      LAYER metal3 ;
      RECT 1.000 560.420 3.000 560.490 ;
    END
    PORT
      LAYER metal3 ;
      RECT 1.000 560.385 4.000 560.525 ;
    END
  END wd_in[227]
  PIN wd_in[228]
    DIRECTION INPUT ;
    USE SIGNAL ;
    PORT
      LAYER metal3 ;
      RECT 1.000 561.540 3.000 561.610 ;
    END
    PORT
      LAYER metal3 ;
      RECT 1.000 561.505 4.000 561.645 ;
    END
  END wd_in[228]
  PIN wd_in[229]
    DIRECTION INPUT ;
    USE SIGNAL ;
    PORT
      LAYER metal3 ;
      RECT 1.000 562.660 3.000 562.730 ;
    END
    PORT
      LAYER metal3 ;
      RECT 1.000 562.625 4.000 562.765 ;
    END
  END wd_in[229]
  PIN wd_in[230]
    DIRECTION INPUT ;
    USE SIGNAL ;
    PORT
      LAYER metal3 ;
      RECT 1.000 563.780 3.000 563.850 ;
    END
    PORT
      LAYER metal3 ;
      RECT 1.000 563.745 4.000 563.885 ;
    END
  END wd_in[230]
  PIN wd_in[231]
    DIRECTION INPUT ;
    USE SIGNAL ;
    PORT
      LAYER metal3 ;
      RECT 1.000 564.900 3.000 564.970 ;
    END
    PORT
      LAYER metal3 ;
      RECT 1.000 564.865 4.000 565.005 ;
    END
  END wd_in[231]
  PIN wd_in[232]
    DIRECTION INPUT ;
    USE SIGNAL ;
    PORT
      LAYER metal3 ;
      RECT 1.000 566.020 3.000 566.090 ;
    END
    PORT
      LAYER metal3 ;
      RECT 1.000 565.985 4.000 566.125 ;
    END
  END wd_in[232]
  PIN wd_in[233]
    DIRECTION INPUT ;
    USE SIGNAL ;
    PORT
      LAYER metal3 ;
      RECT 1.000 567.140 3.000 567.210 ;
    END
    PORT
      LAYER metal3 ;
      RECT 1.000 567.105 4.000 567.245 ;
    END
  END wd_in[233]
  PIN wd_in[234]
    DIRECTION INPUT ;
    USE SIGNAL ;
    PORT
      LAYER metal3 ;
      RECT 1.000 568.260 3.000 568.330 ;
    END
    PORT
      LAYER metal3 ;
      RECT 1.000 568.225 4.000 568.365 ;
    END
  END wd_in[234]
  PIN wd_in[235]
    DIRECTION INPUT ;
    USE SIGNAL ;
    PORT
      LAYER metal3 ;
      RECT 1.000 569.380 3.000 569.450 ;
    END
    PORT
      LAYER metal3 ;
      RECT 1.000 569.345 4.000 569.485 ;
    END
  END wd_in[235]
  PIN wd_in[236]
    DIRECTION INPUT ;
    USE SIGNAL ;
    PORT
      LAYER metal3 ;
      RECT 1.000 570.500 3.000 570.570 ;
    END
    PORT
      LAYER metal3 ;
      RECT 1.000 570.465 4.000 570.605 ;
    END
  END wd_in[236]
  PIN wd_in[237]
    DIRECTION INPUT ;
    USE SIGNAL ;
    PORT
      LAYER metal3 ;
      RECT 1.000 571.620 3.000 571.690 ;
    END
    PORT
      LAYER metal3 ;
      RECT 1.000 571.585 4.000 571.725 ;
    END
  END wd_in[237]
  PIN wd_in[238]
    DIRECTION INPUT ;
    USE SIGNAL ;
    PORT
      LAYER metal3 ;
      RECT 1.000 572.740 3.000 572.810 ;
    END
    PORT
      LAYER metal3 ;
      RECT 1.000 572.705 4.000 572.845 ;
    END
  END wd_in[238]
  PIN wd_in[239]
    DIRECTION INPUT ;
    USE SIGNAL ;
    PORT
      LAYER metal3 ;
      RECT 1.000 573.860 3.000 573.930 ;
    END
    PORT
      LAYER metal3 ;
      RECT 1.000 573.825 4.000 573.965 ;
    END
  END wd_in[239]
  PIN wd_in[240]
    DIRECTION INPUT ;
    USE SIGNAL ;
    PORT
      LAYER metal3 ;
      RECT 1.000 574.980 3.000 575.050 ;
    END
    PORT
      LAYER metal3 ;
      RECT 1.000 574.945 4.000 575.085 ;
    END
  END wd_in[240]
  PIN wd_in[241]
    DIRECTION INPUT ;
    USE SIGNAL ;
    PORT
      LAYER metal3 ;
      RECT 1.000 576.100 3.000 576.170 ;
    END
    PORT
      LAYER metal3 ;
      RECT 1.000 576.065 4.000 576.205 ;
    END
  END wd_in[241]
  PIN wd_in[242]
    DIRECTION INPUT ;
    USE SIGNAL ;
    PORT
      LAYER metal3 ;
      RECT 1.000 577.220 3.000 577.290 ;
    END
    PORT
      LAYER metal3 ;
      RECT 1.000 577.185 4.000 577.325 ;
    END
  END wd_in[242]
  PIN wd_in[243]
    DIRECTION INPUT ;
    USE SIGNAL ;
    PORT
      LAYER metal3 ;
      RECT 1.000 578.340 3.000 578.410 ;
    END
    PORT
      LAYER metal3 ;
      RECT 1.000 578.305 4.000 578.445 ;
    END
  END wd_in[243]
  PIN wd_in[244]
    DIRECTION INPUT ;
    USE SIGNAL ;
    PORT
      LAYER metal3 ;
      RECT 1.000 579.460 3.000 579.530 ;
    END
    PORT
      LAYER metal3 ;
      RECT 1.000 579.425 4.000 579.565 ;
    END
  END wd_in[244]
  PIN wd_in[245]
    DIRECTION INPUT ;
    USE SIGNAL ;
    PORT
      LAYER metal3 ;
      RECT 1.000 580.580 3.000 580.650 ;
    END
    PORT
      LAYER metal3 ;
      RECT 1.000 580.545 4.000 580.685 ;
    END
  END wd_in[245]
  PIN wd_in[246]
    DIRECTION INPUT ;
    USE SIGNAL ;
    PORT
      LAYER metal3 ;
      RECT 1.000 581.700 3.000 581.770 ;
    END
    PORT
      LAYER metal3 ;
      RECT 1.000 581.665 4.000 581.805 ;
    END
  END wd_in[246]
  PIN wd_in[247]
    DIRECTION INPUT ;
    USE SIGNAL ;
    PORT
      LAYER metal3 ;
      RECT 1.000 582.820 3.000 582.890 ;
    END
    PORT
      LAYER metal3 ;
      RECT 1.000 582.785 4.000 582.925 ;
    END
  END wd_in[247]
  PIN wd_in[248]
    DIRECTION INPUT ;
    USE SIGNAL ;
    PORT
      LAYER metal3 ;
      RECT 1.000 583.940 3.000 584.010 ;
    END
    PORT
      LAYER metal3 ;
      RECT 1.000 583.905 4.000 584.045 ;
    END
  END wd_in[248]
  PIN wd_in[249]
    DIRECTION INPUT ;
    USE SIGNAL ;
    PORT
      LAYER metal3 ;
      RECT 1.000 585.060 3.000 585.130 ;
    END
    PORT
      LAYER metal3 ;
      RECT 1.000 585.025 4.000 585.165 ;
    END
  END wd_in[249]
  PIN wd_in[250]
    DIRECTION INPUT ;
    USE SIGNAL ;
    PORT
      LAYER metal3 ;
      RECT 1.000 586.180 3.000 586.250 ;
    END
    PORT
      LAYER metal3 ;
      RECT 1.000 586.145 4.000 586.285 ;
    END
  END wd_in[250]
  PIN wd_in[251]
    DIRECTION INPUT ;
    USE SIGNAL ;
    PORT
      LAYER metal3 ;
      RECT 1.000 587.300 3.000 587.370 ;
    END
    PORT
      LAYER metal3 ;
      RECT 1.000 587.265 4.000 587.405 ;
    END
  END wd_in[251]
  PIN wd_in[252]
    DIRECTION INPUT ;
    USE SIGNAL ;
    PORT
      LAYER metal3 ;
      RECT 1.000 588.420 3.000 588.490 ;
    END
    PORT
      LAYER metal3 ;
      RECT 1.000 588.385 4.000 588.525 ;
    END
  END wd_in[252]
  PIN wd_in[253]
    DIRECTION INPUT ;
    USE SIGNAL ;
    PORT
      LAYER metal3 ;
      RECT 1.000 589.540 3.000 589.610 ;
    END
    PORT
      LAYER metal3 ;
      RECT 1.000 589.505 4.000 589.645 ;
    END
  END wd_in[253]
  PIN wd_in[254]
    DIRECTION INPUT ;
    USE SIGNAL ;
    PORT
      LAYER metal3 ;
      RECT 1.000 590.660 3.000 590.730 ;
    END
    PORT
      LAYER metal3 ;
      RECT 1.000 590.625 4.000 590.765 ;
    END
  END wd_in[254]
  PIN wd_in[255]
    DIRECTION INPUT ;
    USE SIGNAL ;
    PORT
      LAYER metal3 ;
      RECT 1.000 591.780 3.000 591.850 ;
    END
    PORT
      LAYER metal3 ;
      RECT 1.000 591.745 4.000 591.885 ;
    END
  END wd_in[255]
  PIN addr_in[0]
    DIRECTION INPUT ;
    USE SIGNAL ;
    PORT
      LAYER metal3 ;
      RECT 1.000 612.220 3.000 612.290 ;
    END
    PORT
      LAYER metal3 ;
      RECT 1.000 612.185 4.000 612.325 ;
    END
  END addr_in[0]
  PIN addr_in[1]
    DIRECTION INPUT ;
    USE SIGNAL ;
    PORT
      LAYER metal3 ;
      RECT 1.000 613.340 3.000 613.410 ;
    END
    PORT
      LAYER metal3 ;
      RECT 1.000 613.305 4.000 613.445 ;
    END
  END addr_in[1]
  PIN addr_in[2]
    DIRECTION INPUT ;
    USE SIGNAL ;
    PORT
      LAYER metal3 ;
      RECT 1.000 614.460 3.000 614.530 ;
    END
    PORT
      LAYER metal3 ;
      RECT 1.000 614.425 4.000 614.565 ;
    END
  END addr_in[2]
  PIN addr_in[3]
    DIRECTION INPUT ;
    USE SIGNAL ;
    PORT
      LAYER metal3 ;
      RECT 1.000 615.580 3.000 615.650 ;
    END
    PORT
      LAYER metal3 ;
      RECT 1.000 615.545 4.000 615.685 ;
    END
  END addr_in[3]
  PIN addr_in[4]
    DIRECTION INPUT ;
    USE SIGNAL ;
    PORT
      LAYER metal3 ;
      RECT 1.000 616.700 3.000 616.770 ;
    END
    PORT
      LAYER metal3 ;
      RECT 1.000 616.665 4.000 616.805 ;
    END
  END addr_in[4]
  PIN addr_in[5]
    DIRECTION INPUT ;
    USE SIGNAL ;
    PORT
      LAYER metal3 ;
      RECT 1.000 617.820 3.000 617.890 ;
    END
    PORT
      LAYER metal3 ;
      RECT 1.000 617.785 4.000 617.925 ;
    END
  END addr_in[5]
  PIN addr_in[6]
    DIRECTION INPUT ;
    USE SIGNAL ;
    PORT
      LAYER metal3 ;
      RECT 1.000 618.940 3.000 619.010 ;
    END
    PORT
      LAYER metal3 ;
      RECT 1.000 618.905 4.000 619.045 ;
    END
  END addr_in[6]
  PIN addr_in[7]
    DIRECTION INPUT ;
    USE SIGNAL ;
    PORT
      LAYER metal3 ;
      RECT 1.000 620.060 3.000 620.130 ;
    END
    PORT
      LAYER metal3 ;
      RECT 1.000 620.025 4.000 620.165 ;
    END
  END addr_in[7]
  PIN addr_in[8]
    DIRECTION INPUT ;
    USE SIGNAL ;
    PORT
      LAYER metal3 ;
      RECT 1.000 621.180 3.000 621.250 ;
    END
    PORT
      LAYER metal3 ;
      RECT 1.000 621.145 4.000 621.285 ;
    END
  END addr_in[8]
  PIN we_in
    DIRECTION INPUT ;
    USE SIGNAL ;
    PORT
      LAYER metal3 ;
      RECT 1.000 641.620 3.000 641.690 ;
    END
    PORT
      LAYER metal3 ;
      RECT 1.000 641.585 4.000 641.725 ;
    END
  END we_in
  PIN ce_in
    DIRECTION INPUT ;
    USE SIGNAL ;
    PORT
      LAYER metal3 ;
      RECT 1.000 642.740 3.000 642.810 ;
    END
    PORT
      LAYER metal3 ;
      RECT 1.000 642.705 4.000 642.845 ;
    END
  END ce_in
  PIN clk
    DIRECTION INPUT ;
    USE SIGNAL ;
    PORT
      LAYER metal3 ;
      RECT 1.000 643.860 3.000 643.930 ;
    END
    PORT
      LAYER metal3 ;
      RECT 1.000 643.825 4.000 643.965 ;
    END
  END clk
  PIN VSS
    DIRECTION INOUT ;
    USE GROUND ;
    PORT
      LAYER metal3 ;
      RECT 0.140 0.000 258.020 0.280 ;
      RECT 0.140 2.240 258.020 2.520 ;
      RECT 0.140 4.480 258.020 4.760 ;
      RECT 0.140 6.720 258.020 7.000 ;
      RECT 0.140 8.960 258.020 9.240 ;
      RECT 0.140 11.200 258.020 11.480 ;
      RECT 0.140 13.440 258.020 13.720 ;
      RECT 0.140 15.680 258.020 15.960 ;
      RECT 0.140 17.920 258.020 18.200 ;
      RECT 0.140 20.160 258.020 20.440 ;
      RECT 0.140 22.400 258.020 22.680 ;
      RECT 0.140 24.640 258.020 24.920 ;
      RECT 0.140 26.880 258.020 27.160 ;
      RECT 0.140 29.120 258.020 29.400 ;
      RECT 0.140 31.360 258.020 31.640 ;
      RECT 0.140 33.600 258.020 33.880 ;
      RECT 0.140 35.840 258.020 36.120 ;
      RECT 0.140 38.080 258.020 38.360 ;
      RECT 0.140 40.320 258.020 40.600 ;
      RECT 0.140 42.560 258.020 42.840 ;
      RECT 0.140 44.800 258.020 45.080 ;
      RECT 0.140 47.040 258.020 47.320 ;
      RECT 0.140 49.280 258.020 49.560 ;
      RECT 0.140 51.520 258.020 51.800 ;
      RECT 0.140 53.760 258.020 54.040 ;
      RECT 0.140 56.000 258.020 56.280 ;
      RECT 0.140 58.240 258.020 58.520 ;
      RECT 0.140 60.480 258.020 60.760 ;
      RECT 0.140 62.720 258.020 63.000 ;
      RECT 0.140 64.960 258.020 65.240 ;
      RECT 0.140 67.200 258.020 67.480 ;
      RECT 0.140 69.440 258.020 69.720 ;
      RECT 0.140 71.680 258.020 71.960 ;
      RECT 0.140 73.920 258.020 74.200 ;
      RECT 0.140 76.160 258.020 76.440 ;
      RECT 0.140 78.400 258.020 78.680 ;
      RECT 0.140 80.640 258.020 80.920 ;
      RECT 0.140 82.880 258.020 83.160 ;
      RECT 0.140 85.120 258.020 85.400 ;
      RECT 0.140 87.360 258.020 87.640 ;
      RECT 0.140 89.600 258.020 89.880 ;
      RECT 0.140 91.840 258.020 92.120 ;
      RECT 0.140 94.080 258.020 94.360 ;
      RECT 0.140 96.320 258.020 96.600 ;
      RECT 0.140 98.560 258.020 98.840 ;
      RECT 0.140 100.800 258.020 101.080 ;
      RECT 0.140 103.040 258.020 103.320 ;
      RECT 0.140 105.280 258.020 105.560 ;
      RECT 0.140 107.520 258.020 107.800 ;
      RECT 0.140 109.760 258.020 110.040 ;
      RECT 0.140 112.000 258.020 112.280 ;
      RECT 0.140 114.240 258.020 114.520 ;
      RECT 0.140 116.480 258.020 116.760 ;
      RECT 0.140 118.720 258.020 119.000 ;
      RECT 0.140 120.960 258.020 121.240 ;
      RECT 0.140 123.200 258.020 123.480 ;
      RECT 0.140 125.440 258.020 125.720 ;
      RECT 0.140 127.680 258.020 127.960 ;
      RECT 0.140 129.920 258.020 130.200 ;
      RECT 0.140 132.160 258.020 132.440 ;
      RECT 0.140 134.400 258.020 134.680 ;
      RECT 0.140 136.640 258.020 136.920 ;
      RECT 0.140 138.880 258.020 139.160 ;
      RECT 0.140 141.120 258.020 141.400 ;
      RECT 0.140 143.360 258.020 143.640 ;
      RECT 0.140 145.600 258.020 145.880 ;
      RECT 0.140 147.840 258.020 148.120 ;
      RECT 0.140 150.080 258.020 150.360 ;
      RECT 0.140 152.320 258.020 152.600 ;
      RECT 0.140 154.560 258.020 154.840 ;
      RECT 0.140 156.800 258.020 157.080 ;
      RECT 0.140 159.040 258.020 159.320 ;
      RECT 0.140 161.280 258.020 161.560 ;
      RECT 0.140 163.520 258.020 163.800 ;
      RECT 0.140 165.760 258.020 166.040 ;
      RECT 0.140 168.000 258.020 168.280 ;
      RECT 0.140 170.240 258.020 170.520 ;
      RECT 0.140 172.480 258.020 172.760 ;
      RECT 0.140 174.720 258.020 175.000 ;
      RECT 0.140 176.960 258.020 177.240 ;
      RECT 0.140 179.200 258.020 179.480 ;
      RECT 0.140 181.440 258.020 181.720 ;
      RECT 0.140 183.680 258.020 183.960 ;
      RECT 0.140 185.920 258.020 186.200 ;
      RECT 0.140 188.160 258.020 188.440 ;
      RECT 0.140 190.400 258.020 190.680 ;
      RECT 0.140 192.640 258.020 192.920 ;
      RECT 0.140 194.880 258.020 195.160 ;
      RECT 0.140 197.120 258.020 197.400 ;
      RECT 0.140 199.360 258.020 199.640 ;
      RECT 0.140 201.600 258.020 201.880 ;
      RECT 0.140 203.840 258.020 204.120 ;
      RECT 0.140 206.080 258.020 206.360 ;
      RECT 0.140 208.320 258.020 208.600 ;
      RECT 0.140 210.560 258.020 210.840 ;
      RECT 0.140 212.800 258.020 213.080 ;
      RECT 0.140 215.040 258.020 215.320 ;
      RECT 0.140 217.280 258.020 217.560 ;
      RECT 0.140 219.520 258.020 219.800 ;
      RECT 0.140 221.760 258.020 222.040 ;
      RECT 0.140 224.000 258.020 224.280 ;
      RECT 0.140 226.240 258.020 226.520 ;
      RECT 0.140 228.480 258.020 228.760 ;
      RECT 0.140 230.720 258.020 231.000 ;
      RECT 0.140 232.960 258.020 233.240 ;
      RECT 0.140 235.200 258.020 235.480 ;
      RECT 0.140 237.440 258.020 237.720 ;
      RECT 0.140 239.680 258.020 239.960 ;
      RECT 0.140 241.920 258.020 242.200 ;
      RECT 0.140 244.160 258.020 244.440 ;
      RECT 0.140 246.400 258.020 246.680 ;
      RECT 0.140 248.640 258.020 248.920 ;
      RECT 0.140 250.880 258.020 251.160 ;
      RECT 0.140 253.120 258.020 253.400 ;
      RECT 0.140 255.360 258.020 255.640 ;
      RECT 0.140 257.600 258.020 257.880 ;
      RECT 0.140 259.840 258.020 260.120 ;
      RECT 0.140 262.080 258.020 262.360 ;
      RECT 0.140 264.320 258.020 264.600 ;
      RECT 0.140 266.560 258.020 266.840 ;
      RECT 0.140 268.800 258.020 269.080 ;
      RECT 0.140 271.040 258.020 271.320 ;
      RECT 0.140 273.280 258.020 273.560 ;
      RECT 0.140 275.520 258.020 275.800 ;
      RECT 0.140 277.760 258.020 278.040 ;
      RECT 0.140 280.000 258.020 280.280 ;
      RECT 0.140 282.240 258.020 282.520 ;
      RECT 0.140 284.480 258.020 284.760 ;
      RECT 0.140 286.720 258.020 287.000 ;
      RECT 0.140 288.960 258.020 289.240 ;
      RECT 0.140 291.200 258.020 291.480 ;
      RECT 0.140 293.440 258.020 293.720 ;
      RECT 0.140 295.680 258.020 295.960 ;
      RECT 0.140 297.920 258.020 298.200 ;
      RECT 0.140 300.160 258.020 300.440 ;
      RECT 0.140 302.400 258.020 302.680 ;
      RECT 0.140 304.640 258.020 304.920 ;
      RECT 0.140 306.880 258.020 307.160 ;
      RECT 0.140 309.120 258.020 309.400 ;
      RECT 0.140 311.360 258.020 311.640 ;
      RECT 0.140 313.600 258.020 313.880 ;
      RECT 0.140 315.840 258.020 316.120 ;
      RECT 0.140 318.080 258.020 318.360 ;
      RECT 0.140 320.320 258.020 320.600 ;
      RECT 0.140 322.560 258.020 322.840 ;
      RECT 0.140 324.800 258.020 325.080 ;
      RECT 0.140 327.040 258.020 327.320 ;
      RECT 0.140 329.280 258.020 329.560 ;
      RECT 0.140 331.520 258.020 331.800 ;
      RECT 0.140 333.760 258.020 334.040 ;
      RECT 0.140 336.000 258.020 336.280 ;
      RECT 0.140 338.240 258.020 338.520 ;
      RECT 0.140 340.480 258.020 340.760 ;
      RECT 0.140 342.720 258.020 343.000 ;
      RECT 0.140 344.960 258.020 345.240 ;
      RECT 0.140 347.200 258.020 347.480 ;
      RECT 0.140 349.440 258.020 349.720 ;
      RECT 0.140 351.680 258.020 351.960 ;
      RECT 0.140 353.920 258.020 354.200 ;
      RECT 0.140 356.160 258.020 356.440 ;
      RECT 0.140 358.400 258.020 358.680 ;
      RECT 0.140 360.640 258.020 360.920 ;
      RECT 0.140 362.880 258.020 363.160 ;
      RECT 0.140 365.120 258.020 365.400 ;
      RECT 0.140 367.360 258.020 367.640 ;
      RECT 0.140 369.600 258.020 369.880 ;
      RECT 0.140 371.840 258.020 372.120 ;
      RECT 0.140 374.080 258.020 374.360 ;
      RECT 0.140 376.320 258.020 376.600 ;
      RECT 0.140 378.560 258.020 378.840 ;
      RECT 0.140 380.800 258.020 381.080 ;
      RECT 0.140 383.040 258.020 383.320 ;
      RECT 0.140 385.280 258.020 385.560 ;
      RECT 0.140 387.520 258.020 387.800 ;
      RECT 0.140 389.760 258.020 390.040 ;
      RECT 0.140 392.000 258.020 392.280 ;
      RECT 0.140 394.240 258.020 394.520 ;
      RECT 0.140 396.480 258.020 396.760 ;
      RECT 0.140 398.720 258.020 399.000 ;
      RECT 0.140 400.960 258.020 401.240 ;
      RECT 0.140 403.200 258.020 403.480 ;
      RECT 0.140 405.440 258.020 405.720 ;
      RECT 0.140 407.680 258.020 407.960 ;
      RECT 0.140 409.920 258.020 410.200 ;
      RECT 0.140 412.160 258.020 412.440 ;
      RECT 0.140 414.400 258.020 414.680 ;
      RECT 0.140 416.640 258.020 416.920 ;
      RECT 0.140 418.880 258.020 419.160 ;
      RECT 0.140 421.120 258.020 421.400 ;
      RECT 0.140 423.360 258.020 423.640 ;
      RECT 0.140 425.600 258.020 425.880 ;
      RECT 0.140 427.840 258.020 428.120 ;
      RECT 0.140 430.080 258.020 430.360 ;
      RECT 0.140 432.320 258.020 432.600 ;
      RECT 0.140 434.560 258.020 434.840 ;
      RECT 0.140 436.800 258.020 437.080 ;
      RECT 0.140 439.040 258.020 439.320 ;
      RECT 0.140 441.280 258.020 441.560 ;
      RECT 0.140 443.520 258.020 443.800 ;
      RECT 0.140 445.760 258.020 446.040 ;
      RECT 0.140 448.000 258.020 448.280 ;
      RECT 0.140 450.240 258.020 450.520 ;
      RECT 0.140 452.480 258.020 452.760 ;
      RECT 0.140 454.720 258.020 455.000 ;
      RECT 0.140 456.960 258.020 457.240 ;
      RECT 0.140 459.200 258.020 459.480 ;
      RECT 0.140 461.440 258.020 461.720 ;
      RECT 0.140 463.680 258.020 463.960 ;
      RECT 0.140 465.920 258.020 466.200 ;
      RECT 0.140 468.160 258.020 468.440 ;
      RECT 0.140 470.400 258.020 470.680 ;
      RECT 0.140 472.640 258.020 472.920 ;
      RECT 0.140 474.880 258.020 475.160 ;
      RECT 0.140 477.120 258.020 477.400 ;
      RECT 0.140 479.360 258.020 479.640 ;
      RECT 0.140 481.600 258.020 481.880 ;
      RECT 0.140 483.840 258.020 484.120 ;
      RECT 0.140 486.080 258.020 486.360 ;
      RECT 0.140 488.320 258.020 488.600 ;
      RECT 0.140 490.560 258.020 490.840 ;
      RECT 0.140 492.800 258.020 493.080 ;
      RECT 0.140 495.040 258.020 495.320 ;
      RECT 0.140 497.280 258.020 497.560 ;
      RECT 0.140 499.520 258.020 499.800 ;
      RECT 0.140 501.760 258.020 502.040 ;
      RECT 0.140 504.000 258.020 504.280 ;
      RECT 0.140 506.240 258.020 506.520 ;
      RECT 0.140 508.480 258.020 508.760 ;
      RECT 0.140 510.720 258.020 511.000 ;
      RECT 0.140 512.960 258.020 513.240 ;
      RECT 0.140 515.200 258.020 515.480 ;
      RECT 0.140 517.440 258.020 517.720 ;
      RECT 0.140 519.680 258.020 519.960 ;
      RECT 0.140 521.920 258.020 522.200 ;
      RECT 0.140 524.160 258.020 524.440 ;
      RECT 0.140 526.400 258.020 526.680 ;
      RECT 0.140 528.640 258.020 528.920 ;
      RECT 0.140 530.880 258.020 531.160 ;
      RECT 0.140 533.120 258.020 533.400 ;
      RECT 0.140 535.360 258.020 535.640 ;
      RECT 0.140 537.600 258.020 537.880 ;
      RECT 0.140 539.840 258.020 540.120 ;
      RECT 0.140 542.080 258.020 542.360 ;
      RECT 0.140 544.320 258.020 544.600 ;
      RECT 0.140 546.560 258.020 546.840 ;
      RECT 0.140 548.800 258.020 549.080 ;
      RECT 0.140 551.040 258.020 551.320 ;
      RECT 0.140 553.280 258.020 553.560 ;
      RECT 0.140 555.520 258.020 555.800 ;
      RECT 0.140 557.760 258.020 558.040 ;
      RECT 0.140 560.000 258.020 560.280 ;
      RECT 0.140 562.240 258.020 562.520 ;
      RECT 0.140 564.480 258.020 564.760 ;
      RECT 0.140 566.720 258.020 567.000 ;
      RECT 0.140 568.960 258.020 569.240 ;
      RECT 0.140 571.200 258.020 571.480 ;
      RECT 0.140 573.440 258.020 573.720 ;
      RECT 0.140 575.680 258.020 575.960 ;
      RECT 0.140 577.920 258.020 578.200 ;
      RECT 0.140 580.160 258.020 580.440 ;
      RECT 0.140 582.400 258.020 582.680 ;
      RECT 0.140 584.640 258.020 584.920 ;
      RECT 0.140 586.880 258.020 587.160 ;
      RECT 0.140 589.120 258.020 589.400 ;
      RECT 0.140 591.360 258.020 591.640 ;
      RECT 0.140 593.600 258.020 593.880 ;
      RECT 0.140 595.840 258.020 596.120 ;
      RECT 0.140 598.080 258.020 598.360 ;
      RECT 0.140 600.320 258.020 600.600 ;
      RECT 0.140 602.560 258.020 602.840 ;
      RECT 0.140 604.800 258.020 605.080 ;
      RECT 0.140 607.040 258.020 607.320 ;
      RECT 0.140 609.280 258.020 609.560 ;
      RECT 0.140 611.520 258.020 611.800 ;
      RECT 0.140 613.760 258.020 614.040 ;
      RECT 0.140 616.000 258.020 616.280 ;
      RECT 0.140 618.240 258.020 618.520 ;
      RECT 0.140 620.480 258.020 620.760 ;
      RECT 0.140 622.720 258.020 623.000 ;
      RECT 0.140 624.960 258.020 625.240 ;
      RECT 0.140 627.200 258.020 627.480 ;
      RECT 0.140 629.440 258.020 629.720 ;
      RECT 0.140 631.680 258.020 631.960 ;
      RECT 0.140 633.920 258.020 634.200 ;
      RECT 0.140 636.160 258.020 636.440 ;
      RECT 0.140 638.400 258.020 638.680 ;
      RECT 0.140 640.640 258.020 640.920 ;
      RECT 0.140 642.880 258.020 643.160 ;
    END
  END VSS
  PIN VDD
    DIRECTION INOUT ;
    USE POWER ;
    PORT
      LAYER metal3 ;
      RECT 0.140 1.120 258.020 1.400 ;
      RECT 0.140 3.360 258.020 3.640 ;
      RECT 0.140 5.600 258.020 5.880 ;
      RECT 0.140 7.840 258.020 8.120 ;
      RECT 0.140 10.080 258.020 10.360 ;
      RECT 0.140 12.320 258.020 12.600 ;
      RECT 0.140 14.560 258.020 14.840 ;
      RECT 0.140 16.800 258.020 17.080 ;
      RECT 0.140 19.040 258.020 19.320 ;
      RECT 0.140 21.280 258.020 21.560 ;
      RECT 0.140 23.520 258.020 23.800 ;
      RECT 0.140 25.760 258.020 26.040 ;
      RECT 0.140 28.000 258.020 28.280 ;
      RECT 0.140 30.240 258.020 30.520 ;
      RECT 0.140 32.480 258.020 32.760 ;
      RECT 0.140 34.720 258.020 35.000 ;
      RECT 0.140 36.960 258.020 37.240 ;
      RECT 0.140 39.200 258.020 39.480 ;
      RECT 0.140 41.440 258.020 41.720 ;
      RECT 0.140 43.680 258.020 43.960 ;
      RECT 0.140 45.920 258.020 46.200 ;
      RECT 0.140 48.160 258.020 48.440 ;
      RECT 0.140 50.400 258.020 50.680 ;
      RECT 0.140 52.640 258.020 52.920 ;
      RECT 0.140 54.880 258.020 55.160 ;
      RECT 0.140 57.120 258.020 57.400 ;
      RECT 0.140 59.360 258.020 59.640 ;
      RECT 0.140 61.600 258.020 61.880 ;
      RECT 0.140 63.840 258.020 64.120 ;
      RECT 0.140 66.080 258.020 66.360 ;
      RECT 0.140 68.320 258.020 68.600 ;
      RECT 0.140 70.560 258.020 70.840 ;
      RECT 0.140 72.800 258.020 73.080 ;
      RECT 0.140 75.040 258.020 75.320 ;
      RECT 0.140 77.280 258.020 77.560 ;
      RECT 0.140 79.520 258.020 79.800 ;
      RECT 0.140 81.760 258.020 82.040 ;
      RECT 0.140 84.000 258.020 84.280 ;
      RECT 0.140 86.240 258.020 86.520 ;
      RECT 0.140 88.480 258.020 88.760 ;
      RECT 0.140 90.720 258.020 91.000 ;
      RECT 0.140 92.960 258.020 93.240 ;
      RECT 0.140 95.200 258.020 95.480 ;
      RECT 0.140 97.440 258.020 97.720 ;
      RECT 0.140 99.680 258.020 99.960 ;
      RECT 0.140 101.920 258.020 102.200 ;
      RECT 0.140 104.160 258.020 104.440 ;
      RECT 0.140 106.400 258.020 106.680 ;
      RECT 0.140 108.640 258.020 108.920 ;
      RECT 0.140 110.880 258.020 111.160 ;
      RECT 0.140 113.120 258.020 113.400 ;
      RECT 0.140 115.360 258.020 115.640 ;
      RECT 0.140 117.600 258.020 117.880 ;
      RECT 0.140 119.840 258.020 120.120 ;
      RECT 0.140 122.080 258.020 122.360 ;
      RECT 0.140 124.320 258.020 124.600 ;
      RECT 0.140 126.560 258.020 126.840 ;
      RECT 0.140 128.800 258.020 129.080 ;
      RECT 0.140 131.040 258.020 131.320 ;
      RECT 0.140 133.280 258.020 133.560 ;
      RECT 0.140 135.520 258.020 135.800 ;
      RECT 0.140 137.760 258.020 138.040 ;
      RECT 0.140 140.000 258.020 140.280 ;
      RECT 0.140 142.240 258.020 142.520 ;
      RECT 0.140 144.480 258.020 144.760 ;
      RECT 0.140 146.720 258.020 147.000 ;
      RECT 0.140 148.960 258.020 149.240 ;
      RECT 0.140 151.200 258.020 151.480 ;
      RECT 0.140 153.440 258.020 153.720 ;
      RECT 0.140 155.680 258.020 155.960 ;
      RECT 0.140 157.920 258.020 158.200 ;
      RECT 0.140 160.160 258.020 160.440 ;
      RECT 0.140 162.400 258.020 162.680 ;
      RECT 0.140 164.640 258.020 164.920 ;
      RECT 0.140 166.880 258.020 167.160 ;
      RECT 0.140 169.120 258.020 169.400 ;
      RECT 0.140 171.360 258.020 171.640 ;
      RECT 0.140 173.600 258.020 173.880 ;
      RECT 0.140 175.840 258.020 176.120 ;
      RECT 0.140 178.080 258.020 178.360 ;
      RECT 0.140 180.320 258.020 180.600 ;
      RECT 0.140 182.560 258.020 182.840 ;
      RECT 0.140 184.800 258.020 185.080 ;
      RECT 0.140 187.040 258.020 187.320 ;
      RECT 0.140 189.280 258.020 189.560 ;
      RECT 0.140 191.520 258.020 191.800 ;
      RECT 0.140 193.760 258.020 194.040 ;
      RECT 0.140 196.000 258.020 196.280 ;
      RECT 0.140 198.240 258.020 198.520 ;
      RECT 0.140 200.480 258.020 200.760 ;
      RECT 0.140 202.720 258.020 203.000 ;
      RECT 0.140 204.960 258.020 205.240 ;
      RECT 0.140 207.200 258.020 207.480 ;
      RECT 0.140 209.440 258.020 209.720 ;
      RECT 0.140 211.680 258.020 211.960 ;
      RECT 0.140 213.920 258.020 214.200 ;
      RECT 0.140 216.160 258.020 216.440 ;
      RECT 0.140 218.400 258.020 218.680 ;
      RECT 0.140 220.640 258.020 220.920 ;
      RECT 0.140 222.880 258.020 223.160 ;
      RECT 0.140 225.120 258.020 225.400 ;
      RECT 0.140 227.360 258.020 227.640 ;
      RECT 0.140 229.600 258.020 229.880 ;
      RECT 0.140 231.840 258.020 232.120 ;
      RECT 0.140 234.080 258.020 234.360 ;
      RECT 0.140 236.320 258.020 236.600 ;
      RECT 0.140 238.560 258.020 238.840 ;
      RECT 0.140 240.800 258.020 241.080 ;
      RECT 0.140 243.040 258.020 243.320 ;
      RECT 0.140 245.280 258.020 245.560 ;
      RECT 0.140 247.520 258.020 247.800 ;
      RECT 0.140 249.760 258.020 250.040 ;
      RECT 0.140 252.000 258.020 252.280 ;
      RECT 0.140 254.240 258.020 254.520 ;
      RECT 0.140 256.480 258.020 256.760 ;
      RECT 0.140 258.720 258.020 259.000 ;
      RECT 0.140 260.960 258.020 261.240 ;
      RECT 0.140 263.200 258.020 263.480 ;
      RECT 0.140 265.440 258.020 265.720 ;
      RECT 0.140 267.680 258.020 267.960 ;
      RECT 0.140 269.920 258.020 270.200 ;
      RECT 0.140 272.160 258.020 272.440 ;
      RECT 0.140 274.400 258.020 274.680 ;
      RECT 0.140 276.640 258.020 276.920 ;
      RECT 0.140 278.880 258.020 279.160 ;
      RECT 0.140 281.120 258.020 281.400 ;
      RECT 0.140 283.360 258.020 283.640 ;
      RECT 0.140 285.600 258.020 285.880 ;
      RECT 0.140 287.840 258.020 288.120 ;
      RECT 0.140 290.080 258.020 290.360 ;
      RECT 0.140 292.320 258.020 292.600 ;
      RECT 0.140 294.560 258.020 294.840 ;
      RECT 0.140 296.800 258.020 297.080 ;
      RECT 0.140 299.040 258.020 299.320 ;
      RECT 0.140 301.280 258.020 301.560 ;
      RECT 0.140 303.520 258.020 303.800 ;
      RECT 0.140 305.760 258.020 306.040 ;
      RECT 0.140 308.000 258.020 308.280 ;
      RECT 0.140 310.240 258.020 310.520 ;
      RECT 0.140 312.480 258.020 312.760 ;
      RECT 0.140 314.720 258.020 315.000 ;
      RECT 0.140 316.960 258.020 317.240 ;
      RECT 0.140 319.200 258.020 319.480 ;
      RECT 0.140 321.440 258.020 321.720 ;
      RECT 0.140 323.680 258.020 323.960 ;
      RECT 0.140 325.920 258.020 326.200 ;
      RECT 0.140 328.160 258.020 328.440 ;
      RECT 0.140 330.400 258.020 330.680 ;
      RECT 0.140 332.640 258.020 332.920 ;
      RECT 0.140 334.880 258.020 335.160 ;
      RECT 0.140 337.120 258.020 337.400 ;
      RECT 0.140 339.360 258.020 339.640 ;
      RECT 0.140 341.600 258.020 341.880 ;
      RECT 0.140 343.840 258.020 344.120 ;
      RECT 0.140 346.080 258.020 346.360 ;
      RECT 0.140 348.320 258.020 348.600 ;
      RECT 0.140 350.560 258.020 350.840 ;
      RECT 0.140 352.800 258.020 353.080 ;
      RECT 0.140 355.040 258.020 355.320 ;
      RECT 0.140 357.280 258.020 357.560 ;
      RECT 0.140 359.520 258.020 359.800 ;
      RECT 0.140 361.760 258.020 362.040 ;
      RECT 0.140 364.000 258.020 364.280 ;
      RECT 0.140 366.240 258.020 366.520 ;
      RECT 0.140 368.480 258.020 368.760 ;
      RECT 0.140 370.720 258.020 371.000 ;
      RECT 0.140 372.960 258.020 373.240 ;
      RECT 0.140 375.200 258.020 375.480 ;
      RECT 0.140 377.440 258.020 377.720 ;
      RECT 0.140 379.680 258.020 379.960 ;
      RECT 0.140 381.920 258.020 382.200 ;
      RECT 0.140 384.160 258.020 384.440 ;
      RECT 0.140 386.400 258.020 386.680 ;
      RECT 0.140 388.640 258.020 388.920 ;
      RECT 0.140 390.880 258.020 391.160 ;
      RECT 0.140 393.120 258.020 393.400 ;
      RECT 0.140 395.360 258.020 395.640 ;
      RECT 0.140 397.600 258.020 397.880 ;
      RECT 0.140 399.840 258.020 400.120 ;
      RECT 0.140 402.080 258.020 402.360 ;
      RECT 0.140 404.320 258.020 404.600 ;
      RECT 0.140 406.560 258.020 406.840 ;
      RECT 0.140 408.800 258.020 409.080 ;
      RECT 0.140 411.040 258.020 411.320 ;
      RECT 0.140 413.280 258.020 413.560 ;
      RECT 0.140 415.520 258.020 415.800 ;
      RECT 0.140 417.760 258.020 418.040 ;
      RECT 0.140 420.000 258.020 420.280 ;
      RECT 0.140 422.240 258.020 422.520 ;
      RECT 0.140 424.480 258.020 424.760 ;
      RECT 0.140 426.720 258.020 427.000 ;
      RECT 0.140 428.960 258.020 429.240 ;
      RECT 0.140 431.200 258.020 431.480 ;
      RECT 0.140 433.440 258.020 433.720 ;
      RECT 0.140 435.680 258.020 435.960 ;
      RECT 0.140 437.920 258.020 438.200 ;
      RECT 0.140 440.160 258.020 440.440 ;
      RECT 0.140 442.400 258.020 442.680 ;
      RECT 0.140 444.640 258.020 444.920 ;
      RECT 0.140 446.880 258.020 447.160 ;
      RECT 0.140 449.120 258.020 449.400 ;
      RECT 0.140 451.360 258.020 451.640 ;
      RECT 0.140 453.600 258.020 453.880 ;
      RECT 0.140 455.840 258.020 456.120 ;
      RECT 0.140 458.080 258.020 458.360 ;
      RECT 0.140 460.320 258.020 460.600 ;
      RECT 0.140 462.560 258.020 462.840 ;
      RECT 0.140 464.800 258.020 465.080 ;
      RECT 0.140 467.040 258.020 467.320 ;
      RECT 0.140 469.280 258.020 469.560 ;
      RECT 0.140 471.520 258.020 471.800 ;
      RECT 0.140 473.760 258.020 474.040 ;
      RECT 0.140 476.000 258.020 476.280 ;
      RECT 0.140 478.240 258.020 478.520 ;
      RECT 0.140 480.480 258.020 480.760 ;
      RECT 0.140 482.720 258.020 483.000 ;
      RECT 0.140 484.960 258.020 485.240 ;
      RECT 0.140 487.200 258.020 487.480 ;
      RECT 0.140 489.440 258.020 489.720 ;
      RECT 0.140 491.680 258.020 491.960 ;
      RECT 0.140 493.920 258.020 494.200 ;
      RECT 0.140 496.160 258.020 496.440 ;
      RECT 0.140 498.400 258.020 498.680 ;
      RECT 0.140 500.640 258.020 500.920 ;
      RECT 0.140 502.880 258.020 503.160 ;
      RECT 0.140 505.120 258.020 505.400 ;
      RECT 0.140 507.360 258.020 507.640 ;
      RECT 0.140 509.600 258.020 509.880 ;
      RECT 0.140 511.840 258.020 512.120 ;
      RECT 0.140 514.080 258.020 514.360 ;
      RECT 0.140 516.320 258.020 516.600 ;
      RECT 0.140 518.560 258.020 518.840 ;
      RECT 0.140 520.800 258.020 521.080 ;
      RECT 0.140 523.040 258.020 523.320 ;
      RECT 0.140 525.280 258.020 525.560 ;
      RECT 0.140 527.520 258.020 527.800 ;
      RECT 0.140 529.760 258.020 530.040 ;
      RECT 0.140 532.000 258.020 532.280 ;
      RECT 0.140 534.240 258.020 534.520 ;
      RECT 0.140 536.480 258.020 536.760 ;
      RECT 0.140 538.720 258.020 539.000 ;
      RECT 0.140 540.960 258.020 541.240 ;
      RECT 0.140 543.200 258.020 543.480 ;
      RECT 0.140 545.440 258.020 545.720 ;
      RECT 0.140 547.680 258.020 547.960 ;
      RECT 0.140 549.920 258.020 550.200 ;
      RECT 0.140 552.160 258.020 552.440 ;
      RECT 0.140 554.400 258.020 554.680 ;
      RECT 0.140 556.640 258.020 556.920 ;
      RECT 0.140 558.880 258.020 559.160 ;
      RECT 0.140 561.120 258.020 561.400 ;
      RECT 0.140 563.360 258.020 563.640 ;
      RECT 0.140 565.600 258.020 565.880 ;
      RECT 0.140 567.840 258.020 568.120 ;
      RECT 0.140 570.080 258.020 570.360 ;
      RECT 0.140 572.320 258.020 572.600 ;
      RECT 0.140 574.560 258.020 574.840 ;
      RECT 0.140 576.800 258.020 577.080 ;
      RECT 0.140 579.040 258.020 579.320 ;
      RECT 0.140 581.280 258.020 581.560 ;
      RECT 0.140 583.520 258.020 583.800 ;
      RECT 0.140 585.760 258.020 586.040 ;
      RECT 0.140 588.000 258.020 588.280 ;
      RECT 0.140 590.240 258.020 590.520 ;
      RECT 0.140 592.480 258.020 592.760 ;
      RECT 0.140 594.720 258.020 595.000 ;
      RECT 0.140 596.960 258.020 597.240 ;
      RECT 0.140 599.200 258.020 599.480 ;
      RECT 0.140 601.440 258.020 601.720 ;
      RECT 0.140 603.680 258.020 603.960 ;
      RECT 0.140 605.920 258.020 606.200 ;
      RECT 0.140 608.160 258.020 608.440 ;
      RECT 0.140 610.400 258.020 610.680 ;
      RECT 0.140 612.640 258.020 612.920 ;
      RECT 0.140 614.880 258.020 615.160 ;
      RECT 0.140 617.120 258.020 617.400 ;
      RECT 0.140 619.360 258.020 619.640 ;
      RECT 0.140 621.600 258.020 621.880 ;
      RECT 0.140 623.840 258.020 624.120 ;
      RECT 0.140 626.080 258.020 626.360 ;
      RECT 0.140 628.320 258.020 628.600 ;
      RECT 0.140 630.560 258.020 630.840 ;
      RECT 0.140 632.800 258.020 633.080 ;
      RECT 0.140 635.040 258.020 635.320 ;
      RECT 0.140 637.280 258.020 637.560 ;
      RECT 0.140 639.520 258.020 639.800 ;
      RECT 0.140 641.760 258.020 642.040 ;
      RECT 0.140 644.000 258.020 644.280 ;
    END
  END VDD
  OBS
    LAYER metal1 ;
    RECT 0 0 258.160 645.400 ;
    LAYER metal2 ;
    RECT 0 0 258.160 645.400 ;
  END
END fakeram_256x512
END LIBRARY
